VERSION 5.8 ;
BUSBITCHARS "[]" ;
DIVIDERCHAR "/" ;
UNITS
    DATABASE MICRONS 1000 ;
END UNITS

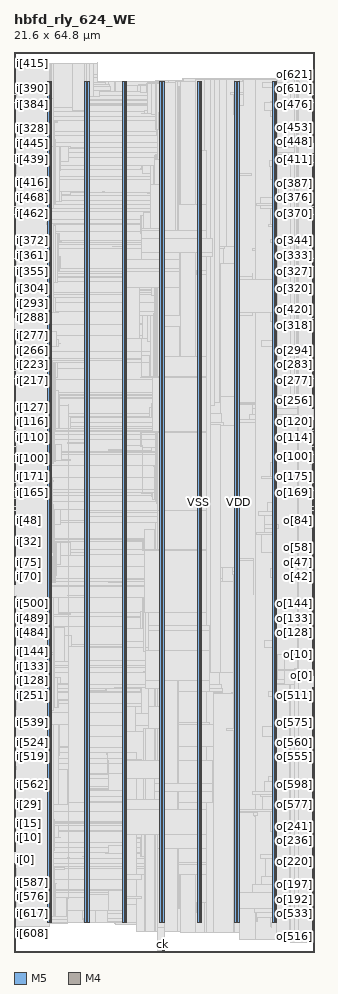
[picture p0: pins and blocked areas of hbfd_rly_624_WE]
MACRO hbfd_rly_624_WE
  FOREIGN hbfd_rly_624_WE 0 0 ;
  CLASS BLOCK ;
  SIZE 21.6 BY 64.8 ;
  PIN ck
    DIRECTION INPUT ;
    USE SIGNAL ;
    PORT
      LAYER M5 ;
        RECT  10.704 0 10.728 0.084 ;
    END
  END ck
  PIN i[0]
    DIRECTION INPUT ;
    USE SIGNAL ;
    PORT
      LAYER M4 ;
        RECT  0 7.248 0.084 7.272 ;
    END
  END i[0]
  PIN i[100]
    DIRECTION INPUT ;
    USE SIGNAL ;
    PORT
      LAYER M4 ;
        RECT  0 36.048 0.084 36.072 ;
    END
  END i[100]
  PIN i[101]
    DIRECTION INPUT ;
    USE SIGNAL ;
    PORT
      LAYER M4 ;
        RECT  0 36.144 0.084 36.168 ;
    END
  END i[101]
  PIN i[102]
    DIRECTION INPUT ;
    USE SIGNAL ;
    PORT
      LAYER M4 ;
        RECT  0 36.24 0.084 36.264 ;
    END
  END i[102]
  PIN i[103]
    DIRECTION INPUT ;
    USE SIGNAL ;
    PORT
      LAYER M4 ;
        RECT  0 36.336 0.084 36.36 ;
    END
  END i[103]
  PIN i[104]
    DIRECTION INPUT ;
    USE SIGNAL ;
    PORT
      LAYER M4 ;
        RECT  0 36.432 0.084 36.456 ;
    END
  END i[104]
  PIN i[105]
    DIRECTION INPUT ;
    USE SIGNAL ;
    PORT
      LAYER M4 ;
        RECT  0 36.528 0.084 36.552 ;
    END
  END i[105]
  PIN i[106]
    DIRECTION INPUT ;
    USE SIGNAL ;
    PORT
      LAYER M4 ;
        RECT  0 36.624 0.084 36.648 ;
    END
  END i[106]
  PIN i[107]
    DIRECTION INPUT ;
    USE SIGNAL ;
    PORT
      LAYER M4 ;
        RECT  0 36.72 0.084 36.744 ;
    END
  END i[107]
  PIN i[108]
    DIRECTION INPUT ;
    USE SIGNAL ;
    PORT
      LAYER M4 ;
        RECT  0 36.816 0.084 36.84 ;
    END
  END i[108]
  PIN i[109]
    DIRECTION INPUT ;
    USE SIGNAL ;
    PORT
      LAYER M4 ;
        RECT  0 36.912 0.084 36.936 ;
    END
  END i[109]
  PIN i[10]
    DIRECTION INPUT ;
    USE SIGNAL ;
    PORT
      LAYER M4 ;
        RECT  0 8.208 0.084 8.232 ;
    END
  END i[10]
  PIN i[110]
    DIRECTION INPUT ;
    USE SIGNAL ;
    PORT
      LAYER M4 ;
        RECT  0 37.008 0.084 37.032 ;
    END
  END i[110]
  PIN i[111]
    DIRECTION INPUT ;
    USE SIGNAL ;
    PORT
      LAYER M4 ;
        RECT  0 37.104 0.084 37.128 ;
    END
  END i[111]
  PIN i[112]
    DIRECTION INPUT ;
    USE SIGNAL ;
    PORT
      LAYER M4 ;
        RECT  0 37.2 0.084 37.224 ;
    END
  END i[112]
  PIN i[113]
    DIRECTION INPUT ;
    USE SIGNAL ;
    PORT
      LAYER M4 ;
        RECT  0 37.296 0.084 37.32 ;
    END
  END i[113]
  PIN i[114]
    DIRECTION INPUT ;
    USE SIGNAL ;
    PORT
      LAYER M4 ;
        RECT  0 37.392 0.084 37.416 ;
    END
  END i[114]
  PIN i[115]
    DIRECTION INPUT ;
    USE SIGNAL ;
    PORT
      LAYER M4 ;
        RECT  0 37.488 0.084 37.512 ;
    END
  END i[115]
  PIN i[116]
    DIRECTION INPUT ;
    USE SIGNAL ;
    PORT
      LAYER M4 ;
        RECT  0 37.584 0.084 37.608 ;
    END
  END i[116]
  PIN i[117]
    DIRECTION INPUT ;
    USE SIGNAL ;
    PORT
      LAYER M4 ;
        RECT  0 37.68 0.084 37.704 ;
    END
  END i[117]
  PIN i[118]
    DIRECTION INPUT ;
    USE SIGNAL ;
    PORT
      LAYER M4 ;
        RECT  0 37.776 0.084 37.8 ;
    END
  END i[118]
  PIN i[119]
    DIRECTION INPUT ;
    USE SIGNAL ;
    PORT
      LAYER M4 ;
        RECT  0 37.872 0.084 37.896 ;
    END
  END i[119]
  PIN i[11]
    DIRECTION INPUT ;
    USE SIGNAL ;
    PORT
      LAYER M4 ;
        RECT  0 8.304 0.084 8.328 ;
    END
  END i[11]
  PIN i[120]
    DIRECTION INPUT ;
    USE SIGNAL ;
    PORT
      LAYER M4 ;
        RECT  0 37.968 0.084 37.992 ;
    END
  END i[120]
  PIN i[121]
    DIRECTION INPUT ;
    USE SIGNAL ;
    PORT
      LAYER M4 ;
        RECT  0 38.064 0.084 38.088 ;
    END
  END i[121]
  PIN i[122]
    DIRECTION INPUT ;
    USE SIGNAL ;
    PORT
      LAYER M4 ;
        RECT  0 38.16 0.084 38.184 ;
    END
  END i[122]
  PIN i[123]
    DIRECTION INPUT ;
    USE SIGNAL ;
    PORT
      LAYER M4 ;
        RECT  0 38.256 0.084 38.28 ;
    END
  END i[123]
  PIN i[124]
    DIRECTION INPUT ;
    USE SIGNAL ;
    PORT
      LAYER M4 ;
        RECT  0 38.352 0.084 38.376 ;
    END
  END i[124]
  PIN i[125]
    DIRECTION INPUT ;
    USE SIGNAL ;
    PORT
      LAYER M4 ;
        RECT  0 38.448 0.084 38.472 ;
    END
  END i[125]
  PIN i[126]
    DIRECTION INPUT ;
    USE SIGNAL ;
    PORT
      LAYER M4 ;
        RECT  0 38.544 0.084 38.568 ;
    END
  END i[126]
  PIN i[127]
    DIRECTION INPUT ;
    USE SIGNAL ;
    PORT
      LAYER M4 ;
        RECT  0 38.64 0.084 38.664 ;
    END
  END i[127]
  PIN i[128]
    DIRECTION INPUT ;
    USE SIGNAL ;
    PORT
      LAYER M4 ;
        RECT  0 19.536 0.084 19.56 ;
    END
  END i[128]
  PIN i[129]
    DIRECTION INPUT ;
    USE SIGNAL ;
    PORT
      LAYER M4 ;
        RECT  0 19.632 0.084 19.656 ;
    END
  END i[129]
  PIN i[12]
    DIRECTION INPUT ;
    USE SIGNAL ;
    PORT
      LAYER M4 ;
        RECT  0 8.4 0.084 8.424 ;
    END
  END i[12]
  PIN i[130]
    DIRECTION INPUT ;
    USE SIGNAL ;
    PORT
      LAYER M4 ;
        RECT  0 19.728 0.084 19.752 ;
    END
  END i[130]
  PIN i[131]
    DIRECTION INPUT ;
    USE SIGNAL ;
    PORT
      LAYER M4 ;
        RECT  0 19.824 0.084 19.848 ;
    END
  END i[131]
  PIN i[132]
    DIRECTION INPUT ;
    USE SIGNAL ;
    PORT
      LAYER M4 ;
        RECT  0 19.92 0.084 19.944 ;
    END
  END i[132]
  PIN i[133]
    DIRECTION INPUT ;
    USE SIGNAL ;
    PORT
      LAYER M4 ;
        RECT  0 20.016 0.084 20.04 ;
    END
  END i[133]
  PIN i[134]
    DIRECTION INPUT ;
    USE SIGNAL ;
    PORT
      LAYER M4 ;
        RECT  0 20.112 0.084 20.136 ;
    END
  END i[134]
  PIN i[135]
    DIRECTION INPUT ;
    USE SIGNAL ;
    PORT
      LAYER M4 ;
        RECT  0 20.208 0.084 20.232 ;
    END
  END i[135]
  PIN i[136]
    DIRECTION INPUT ;
    USE SIGNAL ;
    PORT
      LAYER M4 ;
        RECT  0 20.304 0.084 20.328 ;
    END
  END i[136]
  PIN i[137]
    DIRECTION INPUT ;
    USE SIGNAL ;
    PORT
      LAYER M4 ;
        RECT  0 20.4 0.084 20.424 ;
    END
  END i[137]
  PIN i[138]
    DIRECTION INPUT ;
    USE SIGNAL ;
    PORT
      LAYER M4 ;
        RECT  0 20.496 0.084 20.52 ;
    END
  END i[138]
  PIN i[139]
    DIRECTION INPUT ;
    USE SIGNAL ;
    PORT
      LAYER M4 ;
        RECT  0 20.592 0.084 20.616 ;
    END
  END i[139]
  PIN i[13]
    DIRECTION INPUT ;
    USE SIGNAL ;
    PORT
      LAYER M4 ;
        RECT  0 8.496 0.084 8.52 ;
    END
  END i[13]
  PIN i[140]
    DIRECTION INPUT ;
    USE SIGNAL ;
    PORT
      LAYER M4 ;
        RECT  0 20.688 0.084 20.712 ;
    END
  END i[140]
  PIN i[141]
    DIRECTION INPUT ;
    USE SIGNAL ;
    PORT
      LAYER M4 ;
        RECT  0 20.784 0.084 20.808 ;
    END
  END i[141]
  PIN i[142]
    DIRECTION INPUT ;
    USE SIGNAL ;
    PORT
      LAYER M4 ;
        RECT  0 20.88 0.084 20.904 ;
    END
  END i[142]
  PIN i[143]
    DIRECTION INPUT ;
    USE SIGNAL ;
    PORT
      LAYER M4 ;
        RECT  0 20.976 0.084 21 ;
    END
  END i[143]
  PIN i[144]
    DIRECTION INPUT ;
    USE SIGNAL ;
    PORT
      LAYER M4 ;
        RECT  0 21.072 0.084 21.096 ;
    END
  END i[144]
  PIN i[145]
    DIRECTION INPUT ;
    USE SIGNAL ;
    PORT
      LAYER M4 ;
        RECT  0 21.168 0.084 21.192 ;
    END
  END i[145]
  PIN i[146]
    DIRECTION INPUT ;
    USE SIGNAL ;
    PORT
      LAYER M4 ;
        RECT  0 21.264 0.084 21.288 ;
    END
  END i[146]
  PIN i[147]
    DIRECTION INPUT ;
    USE SIGNAL ;
    PORT
      LAYER M4 ;
        RECT  0 21.36 0.084 21.384 ;
    END
  END i[147]
  PIN i[148]
    DIRECTION INPUT ;
    USE SIGNAL ;
    PORT
      LAYER M4 ;
        RECT  0 21.456 0.084 21.48 ;
    END
  END i[148]
  PIN i[149]
    DIRECTION INPUT ;
    USE SIGNAL ;
    PORT
      LAYER M4 ;
        RECT  0 21.552 0.084 21.576 ;
    END
  END i[149]
  PIN i[14]
    DIRECTION INPUT ;
    USE SIGNAL ;
    PORT
      LAYER M4 ;
        RECT  0 8.592 0.084 8.616 ;
    END
  END i[14]
  PIN i[150]
    DIRECTION INPUT ;
    USE SIGNAL ;
    PORT
      LAYER M4 ;
        RECT  0 21.648 0.084 21.672 ;
    END
  END i[150]
  PIN i[151]
    DIRECTION INPUT ;
    USE SIGNAL ;
    PORT
      LAYER M4 ;
        RECT  0 21.744 0.084 21.768 ;
    END
  END i[151]
  PIN i[152]
    DIRECTION INPUT ;
    USE SIGNAL ;
    PORT
      LAYER M4 ;
        RECT  0 21.84 0.084 21.864 ;
    END
  END i[152]
  PIN i[153]
    DIRECTION INPUT ;
    USE SIGNAL ;
    PORT
      LAYER M4 ;
        RECT  0 21.936 0.084 21.96 ;
    END
  END i[153]
  PIN i[154]
    DIRECTION INPUT ;
    USE SIGNAL ;
    PORT
      LAYER M4 ;
        RECT  0 22.032 0.084 22.056 ;
    END
  END i[154]
  PIN i[155]
    DIRECTION INPUT ;
    USE SIGNAL ;
    PORT
      LAYER M4 ;
        RECT  0 22.128 0.084 22.152 ;
    END
  END i[155]
  PIN i[156]
    DIRECTION INPUT ;
    USE SIGNAL ;
    PORT
      LAYER M4 ;
        RECT  0 22.224 0.084 22.248 ;
    END
  END i[156]
  PIN i[157]
    DIRECTION INPUT ;
    USE SIGNAL ;
    PORT
      LAYER M4 ;
        RECT  0 22.32 0.084 22.344 ;
    END
  END i[157]
  PIN i[158]
    DIRECTION INPUT ;
    USE SIGNAL ;
    PORT
      LAYER M4 ;
        RECT  0 22.416 0.084 22.44 ;
    END
  END i[158]
  PIN i[159]
    DIRECTION INPUT ;
    USE SIGNAL ;
    PORT
      LAYER M4 ;
        RECT  0 22.512 0.084 22.536 ;
    END
  END i[159]
  PIN i[15]
    DIRECTION INPUT ;
    USE SIGNAL ;
    PORT
      LAYER M4 ;
        RECT  0 8.688 0.084 8.712 ;
    END
  END i[15]
  PIN i[160]
    DIRECTION INPUT ;
    USE SIGNAL ;
    PORT
      LAYER M4 ;
        RECT  0 32.592 0.084 32.616 ;
    END
  END i[160]
  PIN i[161]
    DIRECTION INPUT ;
    USE SIGNAL ;
    PORT
      LAYER M4 ;
        RECT  0 32.688 0.084 32.712 ;
    END
  END i[161]
  PIN i[162]
    DIRECTION INPUT ;
    USE SIGNAL ;
    PORT
      LAYER M4 ;
        RECT  0 32.784 0.084 32.808 ;
    END
  END i[162]
  PIN i[163]
    DIRECTION INPUT ;
    USE SIGNAL ;
    PORT
      LAYER M4 ;
        RECT  0 32.88 0.084 32.904 ;
    END
  END i[163]
  PIN i[164]
    DIRECTION INPUT ;
    USE SIGNAL ;
    PORT
      LAYER M4 ;
        RECT  0 32.976 0.084 33 ;
    END
  END i[164]
  PIN i[165]
    DIRECTION INPUT ;
    USE SIGNAL ;
    PORT
      LAYER M4 ;
        RECT  0 33.072 0.084 33.096 ;
    END
  END i[165]
  PIN i[166]
    DIRECTION INPUT ;
    USE SIGNAL ;
    PORT
      LAYER M4 ;
        RECT  0 33.168 0.084 33.192 ;
    END
  END i[166]
  PIN i[167]
    DIRECTION INPUT ;
    USE SIGNAL ;
    PORT
      LAYER M4 ;
        RECT  0 33.264 0.084 33.288 ;
    END
  END i[167]
  PIN i[168]
    DIRECTION INPUT ;
    USE SIGNAL ;
    PORT
      LAYER M4 ;
        RECT  0 33.36 0.084 33.384 ;
    END
  END i[168]
  PIN i[169]
    DIRECTION INPUT ;
    USE SIGNAL ;
    PORT
      LAYER M4 ;
        RECT  0 33.456 0.084 33.48 ;
    END
  END i[169]
  PIN i[16]
    DIRECTION INPUT ;
    USE SIGNAL ;
    PORT
      LAYER M4 ;
        RECT  0 8.784 0.084 8.808 ;
    END
  END i[16]
  PIN i[170]
    DIRECTION INPUT ;
    USE SIGNAL ;
    PORT
      LAYER M4 ;
        RECT  0 33.552 0.084 33.576 ;
    END
  END i[170]
  PIN i[171]
    DIRECTION INPUT ;
    USE SIGNAL ;
    PORT
      LAYER M4 ;
        RECT  0 33.648 0.084 33.672 ;
    END
  END i[171]
  PIN i[172]
    DIRECTION INPUT ;
    USE SIGNAL ;
    PORT
      LAYER M4 ;
        RECT  0 33.744 0.084 33.768 ;
    END
  END i[172]
  PIN i[173]
    DIRECTION INPUT ;
    USE SIGNAL ;
    PORT
      LAYER M4 ;
        RECT  0 33.84 0.084 33.864 ;
    END
  END i[173]
  PIN i[174]
    DIRECTION INPUT ;
    USE SIGNAL ;
    PORT
      LAYER M4 ;
        RECT  0 33.936 0.084 33.96 ;
    END
  END i[174]
  PIN i[175]
    DIRECTION INPUT ;
    USE SIGNAL ;
    PORT
      LAYER M4 ;
        RECT  0 34.032 0.084 34.056 ;
    END
  END i[175]
  PIN i[176]
    DIRECTION INPUT ;
    USE SIGNAL ;
    PORT
      LAYER M4 ;
        RECT  0 34.128 0.084 34.152 ;
    END
  END i[176]
  PIN i[177]
    DIRECTION INPUT ;
    USE SIGNAL ;
    PORT
      LAYER M4 ;
        RECT  0 34.224 0.084 34.248 ;
    END
  END i[177]
  PIN i[178]
    DIRECTION INPUT ;
    USE SIGNAL ;
    PORT
      LAYER M4 ;
        RECT  0 34.32 0.084 34.344 ;
    END
  END i[178]
  PIN i[179]
    DIRECTION INPUT ;
    USE SIGNAL ;
    PORT
      LAYER M4 ;
        RECT  0 34.416 0.084 34.44 ;
    END
  END i[179]
  PIN i[17]
    DIRECTION INPUT ;
    USE SIGNAL ;
    PORT
      LAYER M4 ;
        RECT  0 8.88 0.084 8.904 ;
    END
  END i[17]
  PIN i[180]
    DIRECTION INPUT ;
    USE SIGNAL ;
    PORT
      LAYER M4 ;
        RECT  0 34.512 0.084 34.536 ;
    END
  END i[180]
  PIN i[181]
    DIRECTION INPUT ;
    USE SIGNAL ;
    PORT
      LAYER M4 ;
        RECT  0 34.608 0.084 34.632 ;
    END
  END i[181]
  PIN i[182]
    DIRECTION INPUT ;
    USE SIGNAL ;
    PORT
      LAYER M4 ;
        RECT  0 34.704 0.084 34.728 ;
    END
  END i[182]
  PIN i[183]
    DIRECTION INPUT ;
    USE SIGNAL ;
    PORT
      LAYER M4 ;
        RECT  0 34.8 0.084 34.824 ;
    END
  END i[183]
  PIN i[184]
    DIRECTION INPUT ;
    USE SIGNAL ;
    PORT
      LAYER M4 ;
        RECT  0 34.896 0.084 34.92 ;
    END
  END i[184]
  PIN i[185]
    DIRECTION INPUT ;
    USE SIGNAL ;
    PORT
      LAYER M4 ;
        RECT  0 34.992 0.084 35.016 ;
    END
  END i[185]
  PIN i[186]
    DIRECTION INPUT ;
    USE SIGNAL ;
    PORT
      LAYER M4 ;
        RECT  0 35.088 0.084 35.112 ;
    END
  END i[186]
  PIN i[187]
    DIRECTION INPUT ;
    USE SIGNAL ;
    PORT
      LAYER M4 ;
        RECT  0 35.184 0.084 35.208 ;
    END
  END i[187]
  PIN i[188]
    DIRECTION INPUT ;
    USE SIGNAL ;
    PORT
      LAYER M4 ;
        RECT  0 35.28 0.084 35.304 ;
    END
  END i[188]
  PIN i[189]
    DIRECTION INPUT ;
    USE SIGNAL ;
    PORT
      LAYER M4 ;
        RECT  0 35.376 0.084 35.4 ;
    END
  END i[189]
  PIN i[18]
    DIRECTION INPUT ;
    USE SIGNAL ;
    PORT
      LAYER M4 ;
        RECT  0 8.976 0.084 9 ;
    END
  END i[18]
  PIN i[190]
    DIRECTION INPUT ;
    USE SIGNAL ;
    PORT
      LAYER M4 ;
        RECT  0 35.472 0.084 35.496 ;
    END
  END i[190]
  PIN i[191]
    DIRECTION INPUT ;
    USE SIGNAL ;
    PORT
      LAYER M4 ;
        RECT  0 35.568 0.084 35.592 ;
    END
  END i[191]
  PIN i[192]
    DIRECTION INPUT ;
    USE SIGNAL ;
    PORT
      LAYER M4 ;
        RECT  0 38.736 0.084 38.76 ;
    END
  END i[192]
  PIN i[193]
    DIRECTION INPUT ;
    USE SIGNAL ;
    PORT
      LAYER M4 ;
        RECT  0 38.832 0.084 38.856 ;
    END
  END i[193]
  PIN i[194]
    DIRECTION INPUT ;
    USE SIGNAL ;
    PORT
      LAYER M4 ;
        RECT  0 38.928 0.084 38.952 ;
    END
  END i[194]
  PIN i[195]
    DIRECTION INPUT ;
    USE SIGNAL ;
    PORT
      LAYER M4 ;
        RECT  0 39.024 0.084 39.048 ;
    END
  END i[195]
  PIN i[196]
    DIRECTION INPUT ;
    USE SIGNAL ;
    PORT
      LAYER M4 ;
        RECT  0 39.12 0.084 39.144 ;
    END
  END i[196]
  PIN i[197]
    DIRECTION INPUT ;
    USE SIGNAL ;
    PORT
      LAYER M4 ;
        RECT  0 39.216 0.084 39.24 ;
    END
  END i[197]
  PIN i[198]
    DIRECTION INPUT ;
    USE SIGNAL ;
    PORT
      LAYER M4 ;
        RECT  0 39.312 0.084 39.336 ;
    END
  END i[198]
  PIN i[199]
    DIRECTION INPUT ;
    USE SIGNAL ;
    PORT
      LAYER M4 ;
        RECT  0 39.408 0.084 39.432 ;
    END
  END i[199]
  PIN i[19]
    DIRECTION INPUT ;
    USE SIGNAL ;
    PORT
      LAYER M4 ;
        RECT  0 9.072 0.084 9.096 ;
    END
  END i[19]
  PIN i[1]
    DIRECTION INPUT ;
    USE SIGNAL ;
    PORT
      LAYER M4 ;
        RECT  0 7.344 0.084 7.368 ;
    END
  END i[1]
  PIN i[200]
    DIRECTION INPUT ;
    USE SIGNAL ;
    PORT
      LAYER M4 ;
        RECT  0 39.504 0.084 39.528 ;
    END
  END i[200]
  PIN i[201]
    DIRECTION INPUT ;
    USE SIGNAL ;
    PORT
      LAYER M4 ;
        RECT  0 39.6 0.084 39.624 ;
    END
  END i[201]
  PIN i[202]
    DIRECTION INPUT ;
    USE SIGNAL ;
    PORT
      LAYER M4 ;
        RECT  0 39.696 0.084 39.72 ;
    END
  END i[202]
  PIN i[203]
    DIRECTION INPUT ;
    USE SIGNAL ;
    PORT
      LAYER M4 ;
        RECT  0 39.792 0.084 39.816 ;
    END
  END i[203]
  PIN i[204]
    DIRECTION INPUT ;
    USE SIGNAL ;
    PORT
      LAYER M4 ;
        RECT  0 39.888 0.084 39.912 ;
    END
  END i[204]
  PIN i[205]
    DIRECTION INPUT ;
    USE SIGNAL ;
    PORT
      LAYER M4 ;
        RECT  0 39.984 0.084 40.008 ;
    END
  END i[205]
  PIN i[206]
    DIRECTION INPUT ;
    USE SIGNAL ;
    PORT
      LAYER M4 ;
        RECT  0 40.08 0.084 40.104 ;
    END
  END i[206]
  PIN i[207]
    DIRECTION INPUT ;
    USE SIGNAL ;
    PORT
      LAYER M4 ;
        RECT  0 40.176 0.084 40.2 ;
    END
  END i[207]
  PIN i[208]
    DIRECTION INPUT ;
    USE SIGNAL ;
    PORT
      LAYER M4 ;
        RECT  0 40.272 0.084 40.296 ;
    END
  END i[208]
  PIN i[209]
    DIRECTION INPUT ;
    USE SIGNAL ;
    PORT
      LAYER M4 ;
        RECT  0 40.368 0.084 40.392 ;
    END
  END i[209]
  PIN i[20]
    DIRECTION INPUT ;
    USE SIGNAL ;
    PORT
      LAYER M4 ;
        RECT  0 9.168 0.084 9.192 ;
    END
  END i[20]
  PIN i[210]
    DIRECTION INPUT ;
    USE SIGNAL ;
    PORT
      LAYER M4 ;
        RECT  0 40.464 0.084 40.488 ;
    END
  END i[210]
  PIN i[211]
    DIRECTION INPUT ;
    USE SIGNAL ;
    PORT
      LAYER M4 ;
        RECT  0 40.56 0.084 40.584 ;
    END
  END i[211]
  PIN i[212]
    DIRECTION INPUT ;
    USE SIGNAL ;
    PORT
      LAYER M4 ;
        RECT  0 40.656 0.084 40.68 ;
    END
  END i[212]
  PIN i[213]
    DIRECTION INPUT ;
    USE SIGNAL ;
    PORT
      LAYER M4 ;
        RECT  0 40.752 0.084 40.776 ;
    END
  END i[213]
  PIN i[214]
    DIRECTION INPUT ;
    USE SIGNAL ;
    PORT
      LAYER M4 ;
        RECT  0 40.848 0.084 40.872 ;
    END
  END i[214]
  PIN i[215]
    DIRECTION INPUT ;
    USE SIGNAL ;
    PORT
      LAYER M4 ;
        RECT  0 40.944 0.084 40.968 ;
    END
  END i[215]
  PIN i[216]
    DIRECTION INPUT ;
    USE SIGNAL ;
    PORT
      LAYER M4 ;
        RECT  0 41.04 0.084 41.064 ;
    END
  END i[216]
  PIN i[217]
    DIRECTION INPUT ;
    USE SIGNAL ;
    PORT
      LAYER M4 ;
        RECT  0 41.136 0.084 41.16 ;
    END
  END i[217]
  PIN i[218]
    DIRECTION INPUT ;
    USE SIGNAL ;
    PORT
      LAYER M4 ;
        RECT  0 41.232 0.084 41.256 ;
    END
  END i[218]
  PIN i[219]
    DIRECTION INPUT ;
    USE SIGNAL ;
    PORT
      LAYER M4 ;
        RECT  0 41.328 0.084 41.352 ;
    END
  END i[219]
  PIN i[21]
    DIRECTION INPUT ;
    USE SIGNAL ;
    PORT
      LAYER M4 ;
        RECT  0 9.264 0.084 9.288 ;
    END
  END i[21]
  PIN i[220]
    DIRECTION INPUT ;
    USE SIGNAL ;
    PORT
      LAYER M4 ;
        RECT  0 41.424 0.084 41.448 ;
    END
  END i[220]
  PIN i[221]
    DIRECTION INPUT ;
    USE SIGNAL ;
    PORT
      LAYER M4 ;
        RECT  0 41.52 0.084 41.544 ;
    END
  END i[221]
  PIN i[222]
    DIRECTION INPUT ;
    USE SIGNAL ;
    PORT
      LAYER M4 ;
        RECT  0 41.616 0.084 41.64 ;
    END
  END i[222]
  PIN i[223]
    DIRECTION INPUT ;
    USE SIGNAL ;
    PORT
      LAYER M4 ;
        RECT  0 41.712 0.084 41.736 ;
    END
  END i[223]
  PIN i[224]
    DIRECTION INPUT ;
    USE SIGNAL ;
    PORT
      LAYER M4 ;
        RECT  0 16.464 0.084 16.488 ;
    END
  END i[224]
  PIN i[225]
    DIRECTION INPUT ;
    USE SIGNAL ;
    PORT
      LAYER M4 ;
        RECT  0 16.56 0.084 16.584 ;
    END
  END i[225]
  PIN i[226]
    DIRECTION INPUT ;
    USE SIGNAL ;
    PORT
      LAYER M4 ;
        RECT  0 16.656 0.084 16.68 ;
    END
  END i[226]
  PIN i[227]
    DIRECTION INPUT ;
    USE SIGNAL ;
    PORT
      LAYER M4 ;
        RECT  0 16.752 0.084 16.776 ;
    END
  END i[227]
  PIN i[228]
    DIRECTION INPUT ;
    USE SIGNAL ;
    PORT
      LAYER M4 ;
        RECT  0 16.848 0.084 16.872 ;
    END
  END i[228]
  PIN i[229]
    DIRECTION INPUT ;
    USE SIGNAL ;
    PORT
      LAYER M4 ;
        RECT  0 16.944 0.084 16.968 ;
    END
  END i[229]
  PIN i[22]
    DIRECTION INPUT ;
    USE SIGNAL ;
    PORT
      LAYER M4 ;
        RECT  0 9.36 0.084 9.384 ;
    END
  END i[22]
  PIN i[230]
    DIRECTION INPUT ;
    USE SIGNAL ;
    PORT
      LAYER M4 ;
        RECT  0 17.04 0.084 17.064 ;
    END
  END i[230]
  PIN i[231]
    DIRECTION INPUT ;
    USE SIGNAL ;
    PORT
      LAYER M4 ;
        RECT  0 17.136 0.084 17.16 ;
    END
  END i[231]
  PIN i[232]
    DIRECTION INPUT ;
    USE SIGNAL ;
    PORT
      LAYER M4 ;
        RECT  0 17.232 0.084 17.256 ;
    END
  END i[232]
  PIN i[233]
    DIRECTION INPUT ;
    USE SIGNAL ;
    PORT
      LAYER M4 ;
        RECT  0 17.328 0.084 17.352 ;
    END
  END i[233]
  PIN i[234]
    DIRECTION INPUT ;
    USE SIGNAL ;
    PORT
      LAYER M4 ;
        RECT  0 17.424 0.084 17.448 ;
    END
  END i[234]
  PIN i[235]
    DIRECTION INPUT ;
    USE SIGNAL ;
    PORT
      LAYER M4 ;
        RECT  0 17.52 0.084 17.544 ;
    END
  END i[235]
  PIN i[236]
    DIRECTION INPUT ;
    USE SIGNAL ;
    PORT
      LAYER M4 ;
        RECT  0 17.616 0.084 17.64 ;
    END
  END i[236]
  PIN i[237]
    DIRECTION INPUT ;
    USE SIGNAL ;
    PORT
      LAYER M4 ;
        RECT  0 17.712 0.084 17.736 ;
    END
  END i[237]
  PIN i[238]
    DIRECTION INPUT ;
    USE SIGNAL ;
    PORT
      LAYER M4 ;
        RECT  0 17.808 0.084 17.832 ;
    END
  END i[238]
  PIN i[239]
    DIRECTION INPUT ;
    USE SIGNAL ;
    PORT
      LAYER M4 ;
        RECT  0 17.904 0.084 17.928 ;
    END
  END i[239]
  PIN i[23]
    DIRECTION INPUT ;
    USE SIGNAL ;
    PORT
      LAYER M4 ;
        RECT  0 9.456 0.084 9.48 ;
    END
  END i[23]
  PIN i[240]
    DIRECTION INPUT ;
    USE SIGNAL ;
    PORT
      LAYER M4 ;
        RECT  0 18 0.084 18.024 ;
    END
  END i[240]
  PIN i[241]
    DIRECTION INPUT ;
    USE SIGNAL ;
    PORT
      LAYER M4 ;
        RECT  0 18.096 0.084 18.12 ;
    END
  END i[241]
  PIN i[242]
    DIRECTION INPUT ;
    USE SIGNAL ;
    PORT
      LAYER M4 ;
        RECT  0 18.192 0.084 18.216 ;
    END
  END i[242]
  PIN i[243]
    DIRECTION INPUT ;
    USE SIGNAL ;
    PORT
      LAYER M4 ;
        RECT  0 18.288 0.084 18.312 ;
    END
  END i[243]
  PIN i[244]
    DIRECTION INPUT ;
    USE SIGNAL ;
    PORT
      LAYER M4 ;
        RECT  0 18.384 0.084 18.408 ;
    END
  END i[244]
  PIN i[245]
    DIRECTION INPUT ;
    USE SIGNAL ;
    PORT
      LAYER M4 ;
        RECT  0 18.48 0.084 18.504 ;
    END
  END i[245]
  PIN i[246]
    DIRECTION INPUT ;
    USE SIGNAL ;
    PORT
      LAYER M4 ;
        RECT  0 18.576 0.084 18.6 ;
    END
  END i[246]
  PIN i[247]
    DIRECTION INPUT ;
    USE SIGNAL ;
    PORT
      LAYER M4 ;
        RECT  0 18.672 0.084 18.696 ;
    END
  END i[247]
  PIN i[248]
    DIRECTION INPUT ;
    USE SIGNAL ;
    PORT
      LAYER M4 ;
        RECT  0 18.768 0.084 18.792 ;
    END
  END i[248]
  PIN i[249]
    DIRECTION INPUT ;
    USE SIGNAL ;
    PORT
      LAYER M4 ;
        RECT  0 18.864 0.084 18.888 ;
    END
  END i[249]
  PIN i[24]
    DIRECTION INPUT ;
    USE SIGNAL ;
    PORT
      LAYER M4 ;
        RECT  0 9.552 0.084 9.576 ;
    END
  END i[24]
  PIN i[250]
    DIRECTION INPUT ;
    USE SIGNAL ;
    PORT
      LAYER M4 ;
        RECT  0 18.96 0.084 18.984 ;
    END
  END i[250]
  PIN i[251]
    DIRECTION INPUT ;
    USE SIGNAL ;
    PORT
      LAYER M4 ;
        RECT  0 19.056 0.084 19.08 ;
    END
  END i[251]
  PIN i[252]
    DIRECTION INPUT ;
    USE SIGNAL ;
    PORT
      LAYER M4 ;
        RECT  0 19.152 0.084 19.176 ;
    END
  END i[252]
  PIN i[253]
    DIRECTION INPUT ;
    USE SIGNAL ;
    PORT
      LAYER M4 ;
        RECT  0 19.248 0.084 19.272 ;
    END
  END i[253]
  PIN i[254]
    DIRECTION INPUT ;
    USE SIGNAL ;
    PORT
      LAYER M4 ;
        RECT  0 19.344 0.084 19.368 ;
    END
  END i[254]
  PIN i[255]
    DIRECTION INPUT ;
    USE SIGNAL ;
    PORT
      LAYER M4 ;
        RECT  0 19.44 0.084 19.464 ;
    END
  END i[255]
  PIN i[256]
    DIRECTION INPUT ;
    USE SIGNAL ;
    PORT
      LAYER M4 ;
        RECT  0 41.808 0.084 41.832 ;
    END
  END i[256]
  PIN i[257]
    DIRECTION INPUT ;
    USE SIGNAL ;
    PORT
      LAYER M4 ;
        RECT  0 41.904 0.084 41.928 ;
    END
  END i[257]
  PIN i[258]
    DIRECTION INPUT ;
    USE SIGNAL ;
    PORT
      LAYER M4 ;
        RECT  0 42 0.084 42.024 ;
    END
  END i[258]
  PIN i[259]
    DIRECTION INPUT ;
    USE SIGNAL ;
    PORT
      LAYER M4 ;
        RECT  0 42.096 0.084 42.12 ;
    END
  END i[259]
  PIN i[25]
    DIRECTION INPUT ;
    USE SIGNAL ;
    PORT
      LAYER M4 ;
        RECT  0 9.648 0.084 9.672 ;
    END
  END i[25]
  PIN i[260]
    DIRECTION INPUT ;
    USE SIGNAL ;
    PORT
      LAYER M4 ;
        RECT  0 42.192 0.084 42.216 ;
    END
  END i[260]
  PIN i[261]
    DIRECTION INPUT ;
    USE SIGNAL ;
    PORT
      LAYER M4 ;
        RECT  0 42.288 0.084 42.312 ;
    END
  END i[261]
  PIN i[262]
    DIRECTION INPUT ;
    USE SIGNAL ;
    PORT
      LAYER M4 ;
        RECT  0 42.384 0.084 42.408 ;
    END
  END i[262]
  PIN i[263]
    DIRECTION INPUT ;
    USE SIGNAL ;
    PORT
      LAYER M4 ;
        RECT  0 42.48 0.084 42.504 ;
    END
  END i[263]
  PIN i[264]
    DIRECTION INPUT ;
    USE SIGNAL ;
    PORT
      LAYER M4 ;
        RECT  0 42.576 0.084 42.6 ;
    END
  END i[264]
  PIN i[265]
    DIRECTION INPUT ;
    USE SIGNAL ;
    PORT
      LAYER M4 ;
        RECT  0 42.672 0.084 42.696 ;
    END
  END i[265]
  PIN i[266]
    DIRECTION INPUT ;
    USE SIGNAL ;
    PORT
      LAYER M4 ;
        RECT  0 42.768 0.084 42.792 ;
    END
  END i[266]
  PIN i[267]
    DIRECTION INPUT ;
    USE SIGNAL ;
    PORT
      LAYER M4 ;
        RECT  0 42.864 0.084 42.888 ;
    END
  END i[267]
  PIN i[268]
    DIRECTION INPUT ;
    USE SIGNAL ;
    PORT
      LAYER M4 ;
        RECT  0 42.96 0.084 42.984 ;
    END
  END i[268]
  PIN i[269]
    DIRECTION INPUT ;
    USE SIGNAL ;
    PORT
      LAYER M4 ;
        RECT  0 43.056 0.084 43.08 ;
    END
  END i[269]
  PIN i[26]
    DIRECTION INPUT ;
    USE SIGNAL ;
    PORT
      LAYER M4 ;
        RECT  0 9.744 0.084 9.768 ;
    END
  END i[26]
  PIN i[270]
    DIRECTION INPUT ;
    USE SIGNAL ;
    PORT
      LAYER M4 ;
        RECT  0 43.152 0.084 43.176 ;
    END
  END i[270]
  PIN i[271]
    DIRECTION INPUT ;
    USE SIGNAL ;
    PORT
      LAYER M4 ;
        RECT  0 43.248 0.084 43.272 ;
    END
  END i[271]
  PIN i[272]
    DIRECTION INPUT ;
    USE SIGNAL ;
    PORT
      LAYER M4 ;
        RECT  0 43.344 0.084 43.368 ;
    END
  END i[272]
  PIN i[273]
    DIRECTION INPUT ;
    USE SIGNAL ;
    PORT
      LAYER M4 ;
        RECT  0 43.44 0.084 43.464 ;
    END
  END i[273]
  PIN i[274]
    DIRECTION INPUT ;
    USE SIGNAL ;
    PORT
      LAYER M4 ;
        RECT  0 43.536 0.084 43.56 ;
    END
  END i[274]
  PIN i[275]
    DIRECTION INPUT ;
    USE SIGNAL ;
    PORT
      LAYER M4 ;
        RECT  0 43.632 0.084 43.656 ;
    END
  END i[275]
  PIN i[276]
    DIRECTION INPUT ;
    USE SIGNAL ;
    PORT
      LAYER M4 ;
        RECT  0 43.728 0.084 43.752 ;
    END
  END i[276]
  PIN i[277]
    DIRECTION INPUT ;
    USE SIGNAL ;
    PORT
      LAYER M4 ;
        RECT  0 43.824 0.084 43.848 ;
    END
  END i[277]
  PIN i[278]
    DIRECTION INPUT ;
    USE SIGNAL ;
    PORT
      LAYER M4 ;
        RECT  0 43.92 0.084 43.944 ;
    END
  END i[278]
  PIN i[279]
    DIRECTION INPUT ;
    USE SIGNAL ;
    PORT
      LAYER M4 ;
        RECT  0 44.016 0.084 44.04 ;
    END
  END i[279]
  PIN i[27]
    DIRECTION INPUT ;
    USE SIGNAL ;
    PORT
      LAYER M4 ;
        RECT  0 9.84 0.084 9.864 ;
    END
  END i[27]
  PIN i[280]
    DIRECTION INPUT ;
    USE SIGNAL ;
    PORT
      LAYER M4 ;
        RECT  0 44.112 0.084 44.136 ;
    END
  END i[280]
  PIN i[281]
    DIRECTION INPUT ;
    USE SIGNAL ;
    PORT
      LAYER M4 ;
        RECT  0 44.208 0.084 44.232 ;
    END
  END i[281]
  PIN i[282]
    DIRECTION INPUT ;
    USE SIGNAL ;
    PORT
      LAYER M4 ;
        RECT  0 44.304 0.084 44.328 ;
    END
  END i[282]
  PIN i[283]
    DIRECTION INPUT ;
    USE SIGNAL ;
    PORT
      LAYER M4 ;
        RECT  0 44.4 0.084 44.424 ;
    END
  END i[283]
  PIN i[284]
    DIRECTION INPUT ;
    USE SIGNAL ;
    PORT
      LAYER M4 ;
        RECT  0 44.496 0.084 44.52 ;
    END
  END i[284]
  PIN i[285]
    DIRECTION INPUT ;
    USE SIGNAL ;
    PORT
      LAYER M4 ;
        RECT  0 44.592 0.084 44.616 ;
    END
  END i[285]
  PIN i[286]
    DIRECTION INPUT ;
    USE SIGNAL ;
    PORT
      LAYER M4 ;
        RECT  0 44.688 0.084 44.712 ;
    END
  END i[286]
  PIN i[287]
    DIRECTION INPUT ;
    USE SIGNAL ;
    PORT
      LAYER M4 ;
        RECT  0 44.784 0.084 44.808 ;
    END
  END i[287]
  PIN i[288]
    DIRECTION INPUT ;
    USE SIGNAL ;
    PORT
      LAYER M4 ;
        RECT  0 45.648 0.084 45.672 ;
    END
  END i[288]
  PIN i[289]
    DIRECTION INPUT ;
    USE SIGNAL ;
    PORT
      LAYER M4 ;
        RECT  0 45.744 0.084 45.768 ;
    END
  END i[289]
  PIN i[28]
    DIRECTION INPUT ;
    USE SIGNAL ;
    PORT
      LAYER M4 ;
        RECT  0 9.936 0.084 9.96 ;
    END
  END i[28]
  PIN i[290]
    DIRECTION INPUT ;
    USE SIGNAL ;
    PORT
      LAYER M4 ;
        RECT  0 45.84 0.084 45.864 ;
    END
  END i[290]
  PIN i[291]
    DIRECTION INPUT ;
    USE SIGNAL ;
    PORT
      LAYER M4 ;
        RECT  0 45.936 0.084 45.96 ;
    END
  END i[291]
  PIN i[292]
    DIRECTION INPUT ;
    USE SIGNAL ;
    PORT
      LAYER M4 ;
        RECT  0 46.032 0.084 46.056 ;
    END
  END i[292]
  PIN i[293]
    DIRECTION INPUT ;
    USE SIGNAL ;
    PORT
      LAYER M4 ;
        RECT  0 46.128 0.084 46.152 ;
    END
  END i[293]
  PIN i[294]
    DIRECTION INPUT ;
    USE SIGNAL ;
    PORT
      LAYER M4 ;
        RECT  0 46.224 0.084 46.248 ;
    END
  END i[294]
  PIN i[295]
    DIRECTION INPUT ;
    USE SIGNAL ;
    PORT
      LAYER M4 ;
        RECT  0 46.32 0.084 46.344 ;
    END
  END i[295]
  PIN i[296]
    DIRECTION INPUT ;
    USE SIGNAL ;
    PORT
      LAYER M4 ;
        RECT  0 46.416 0.084 46.44 ;
    END
  END i[296]
  PIN i[297]
    DIRECTION INPUT ;
    USE SIGNAL ;
    PORT
      LAYER M4 ;
        RECT  0 46.512 0.084 46.536 ;
    END
  END i[297]
  PIN i[298]
    DIRECTION INPUT ;
    USE SIGNAL ;
    PORT
      LAYER M4 ;
        RECT  0 46.608 0.084 46.632 ;
    END
  END i[298]
  PIN i[299]
    DIRECTION INPUT ;
    USE SIGNAL ;
    PORT
      LAYER M4 ;
        RECT  0 46.704 0.084 46.728 ;
    END
  END i[299]
  PIN i[29]
    DIRECTION INPUT ;
    USE SIGNAL ;
    PORT
      LAYER M4 ;
        RECT  0 10.032 0.084 10.056 ;
    END
  END i[29]
  PIN i[2]
    DIRECTION INPUT ;
    USE SIGNAL ;
    PORT
      LAYER M4 ;
        RECT  0 7.44 0.084 7.464 ;
    END
  END i[2]
  PIN i[300]
    DIRECTION INPUT ;
    USE SIGNAL ;
    PORT
      LAYER M4 ;
        RECT  0 46.8 0.084 46.824 ;
    END
  END i[300]
  PIN i[301]
    DIRECTION INPUT ;
    USE SIGNAL ;
    PORT
      LAYER M4 ;
        RECT  0 46.896 0.084 46.92 ;
    END
  END i[301]
  PIN i[302]
    DIRECTION INPUT ;
    USE SIGNAL ;
    PORT
      LAYER M4 ;
        RECT  0 46.992 0.084 47.016 ;
    END
  END i[302]
  PIN i[303]
    DIRECTION INPUT ;
    USE SIGNAL ;
    PORT
      LAYER M4 ;
        RECT  0 47.088 0.084 47.112 ;
    END
  END i[303]
  PIN i[304]
    DIRECTION INPUT ;
    USE SIGNAL ;
    PORT
      LAYER M4 ;
        RECT  0 47.184 0.084 47.208 ;
    END
  END i[304]
  PIN i[305]
    DIRECTION INPUT ;
    USE SIGNAL ;
    PORT
      LAYER M4 ;
        RECT  0 47.28 0.084 47.304 ;
    END
  END i[305]
  PIN i[306]
    DIRECTION INPUT ;
    USE SIGNAL ;
    PORT
      LAYER M4 ;
        RECT  0 47.376 0.084 47.4 ;
    END
  END i[306]
  PIN i[307]
    DIRECTION INPUT ;
    USE SIGNAL ;
    PORT
      LAYER M4 ;
        RECT  0 47.472 0.084 47.496 ;
    END
  END i[307]
  PIN i[308]
    DIRECTION INPUT ;
    USE SIGNAL ;
    PORT
      LAYER M4 ;
        RECT  0 47.568 0.084 47.592 ;
    END
  END i[308]
  PIN i[309]
    DIRECTION INPUT ;
    USE SIGNAL ;
    PORT
      LAYER M4 ;
        RECT  0 47.664 0.084 47.688 ;
    END
  END i[309]
  PIN i[30]
    DIRECTION INPUT ;
    USE SIGNAL ;
    PORT
      LAYER M4 ;
        RECT  0 10.128 0.084 10.152 ;
    END
  END i[30]
  PIN i[310]
    DIRECTION INPUT ;
    USE SIGNAL ;
    PORT
      LAYER M4 ;
        RECT  0 47.76 0.084 47.784 ;
    END
  END i[310]
  PIN i[311]
    DIRECTION INPUT ;
    USE SIGNAL ;
    PORT
      LAYER M4 ;
        RECT  0 47.856 0.084 47.88 ;
    END
  END i[311]
  PIN i[312]
    DIRECTION INPUT ;
    USE SIGNAL ;
    PORT
      LAYER M4 ;
        RECT  0 47.952 0.084 47.976 ;
    END
  END i[312]
  PIN i[313]
    DIRECTION INPUT ;
    USE SIGNAL ;
    PORT
      LAYER M4 ;
        RECT  0 48.048 0.084 48.072 ;
    END
  END i[313]
  PIN i[314]
    DIRECTION INPUT ;
    USE SIGNAL ;
    PORT
      LAYER M4 ;
        RECT  0 48.144 0.084 48.168 ;
    END
  END i[314]
  PIN i[315]
    DIRECTION INPUT ;
    USE SIGNAL ;
    PORT
      LAYER M4 ;
        RECT  0 48.24 0.084 48.264 ;
    END
  END i[315]
  PIN i[316]
    DIRECTION INPUT ;
    USE SIGNAL ;
    PORT
      LAYER M4 ;
        RECT  0 48.336 0.084 48.36 ;
    END
  END i[316]
  PIN i[317]
    DIRECTION INPUT ;
    USE SIGNAL ;
    PORT
      LAYER M4 ;
        RECT  0 48.432 0.084 48.456 ;
    END
  END i[317]
  PIN i[318]
    DIRECTION INPUT ;
    USE SIGNAL ;
    PORT
      LAYER M4 ;
        RECT  0 48.528 0.084 48.552 ;
    END
  END i[318]
  PIN i[319]
    DIRECTION INPUT ;
    USE SIGNAL ;
    PORT
      LAYER M4 ;
        RECT  0 48.624 0.084 48.648 ;
    END
  END i[319]
  PIN i[31]
    DIRECTION INPUT ;
    USE SIGNAL ;
    PORT
      LAYER M4 ;
        RECT  0 10.224 0.084 10.248 ;
    END
  END i[31]
  PIN i[320]
    DIRECTION INPUT ;
    USE SIGNAL ;
    PORT
      LAYER M4 ;
        RECT  0 57.936 0.084 57.96 ;
    END
  END i[320]
  PIN i[321]
    DIRECTION INPUT ;
    USE SIGNAL ;
    PORT
      LAYER M4 ;
        RECT  0 58.032 0.084 58.056 ;
    END
  END i[321]
  PIN i[322]
    DIRECTION INPUT ;
    USE SIGNAL ;
    PORT
      LAYER M4 ;
        RECT  0 58.128 0.084 58.152 ;
    END
  END i[322]
  PIN i[323]
    DIRECTION INPUT ;
    USE SIGNAL ;
    PORT
      LAYER M4 ;
        RECT  0 58.224 0.084 58.248 ;
    END
  END i[323]
  PIN i[324]
    DIRECTION INPUT ;
    USE SIGNAL ;
    PORT
      LAYER M4 ;
        RECT  0 58.32 0.084 58.344 ;
    END
  END i[324]
  PIN i[325]
    DIRECTION INPUT ;
    USE SIGNAL ;
    PORT
      LAYER M4 ;
        RECT  0 58.416 0.084 58.44 ;
    END
  END i[325]
  PIN i[326]
    DIRECTION INPUT ;
    USE SIGNAL ;
    PORT
      LAYER M4 ;
        RECT  0 58.512 0.084 58.536 ;
    END
  END i[326]
  PIN i[327]
    DIRECTION INPUT ;
    USE SIGNAL ;
    PORT
      LAYER M4 ;
        RECT  0 58.608 0.084 58.632 ;
    END
  END i[327]
  PIN i[328]
    DIRECTION INPUT ;
    USE SIGNAL ;
    PORT
      LAYER M4 ;
        RECT  0 58.704 0.084 58.728 ;
    END
  END i[328]
  PIN i[329]
    DIRECTION INPUT ;
    USE SIGNAL ;
    PORT
      LAYER M4 ;
        RECT  0 58.8 0.084 58.824 ;
    END
  END i[329]
  PIN i[32]
    DIRECTION INPUT ;
    USE SIGNAL ;
    PORT
      LAYER M4 ;
        RECT  0 29.52 0.084 29.544 ;
    END
  END i[32]
  PIN i[330]
    DIRECTION INPUT ;
    USE SIGNAL ;
    PORT
      LAYER M4 ;
        RECT  0 58.896 0.084 58.92 ;
    END
  END i[330]
  PIN i[331]
    DIRECTION INPUT ;
    USE SIGNAL ;
    PORT
      LAYER M4 ;
        RECT  0 58.992 0.084 59.016 ;
    END
  END i[331]
  PIN i[332]
    DIRECTION INPUT ;
    USE SIGNAL ;
    PORT
      LAYER M4 ;
        RECT  0 59.088 0.084 59.112 ;
    END
  END i[332]
  PIN i[333]
    DIRECTION INPUT ;
    USE SIGNAL ;
    PORT
      LAYER M4 ;
        RECT  0 59.184 0.084 59.208 ;
    END
  END i[333]
  PIN i[334]
    DIRECTION INPUT ;
    USE SIGNAL ;
    PORT
      LAYER M4 ;
        RECT  0 59.28 0.084 59.304 ;
    END
  END i[334]
  PIN i[335]
    DIRECTION INPUT ;
    USE SIGNAL ;
    PORT
      LAYER M4 ;
        RECT  0 59.376 0.084 59.4 ;
    END
  END i[335]
  PIN i[336]
    DIRECTION INPUT ;
    USE SIGNAL ;
    PORT
      LAYER M4 ;
        RECT  0 59.472 0.084 59.496 ;
    END
  END i[336]
  PIN i[337]
    DIRECTION INPUT ;
    USE SIGNAL ;
    PORT
      LAYER M4 ;
        RECT  0 59.568 0.084 59.592 ;
    END
  END i[337]
  PIN i[338]
    DIRECTION INPUT ;
    USE SIGNAL ;
    PORT
      LAYER M4 ;
        RECT  0 59.664 0.084 59.688 ;
    END
  END i[338]
  PIN i[339]
    DIRECTION INPUT ;
    USE SIGNAL ;
    PORT
      LAYER M4 ;
        RECT  0 59.76 0.084 59.784 ;
    END
  END i[339]
  PIN i[33]
    DIRECTION INPUT ;
    USE SIGNAL ;
    PORT
      LAYER M4 ;
        RECT  0 29.616 0.084 29.64 ;
    END
  END i[33]
  PIN i[340]
    DIRECTION INPUT ;
    USE SIGNAL ;
    PORT
      LAYER M4 ;
        RECT  0 59.856 0.084 59.88 ;
    END
  END i[340]
  PIN i[341]
    DIRECTION INPUT ;
    USE SIGNAL ;
    PORT
      LAYER M4 ;
        RECT  0 59.952 0.084 59.976 ;
    END
  END i[341]
  PIN i[342]
    DIRECTION INPUT ;
    USE SIGNAL ;
    PORT
      LAYER M4 ;
        RECT  0 60.048 0.084 60.072 ;
    END
  END i[342]
  PIN i[343]
    DIRECTION INPUT ;
    USE SIGNAL ;
    PORT
      LAYER M4 ;
        RECT  0 60.144 0.084 60.168 ;
    END
  END i[343]
  PIN i[344]
    DIRECTION INPUT ;
    USE SIGNAL ;
    PORT
      LAYER M4 ;
        RECT  0 60.24 0.084 60.264 ;
    END
  END i[344]
  PIN i[345]
    DIRECTION INPUT ;
    USE SIGNAL ;
    PORT
      LAYER M4 ;
        RECT  0 60.336 0.084 60.36 ;
    END
  END i[345]
  PIN i[346]
    DIRECTION INPUT ;
    USE SIGNAL ;
    PORT
      LAYER M4 ;
        RECT  0 60.432 0.084 60.456 ;
    END
  END i[346]
  PIN i[347]
    DIRECTION INPUT ;
    USE SIGNAL ;
    PORT
      LAYER M4 ;
        RECT  0 60.528 0.084 60.552 ;
    END
  END i[347]
  PIN i[348]
    DIRECTION INPUT ;
    USE SIGNAL ;
    PORT
      LAYER M4 ;
        RECT  0 60.624 0.084 60.648 ;
    END
  END i[348]
  PIN i[349]
    DIRECTION INPUT ;
    USE SIGNAL ;
    PORT
      LAYER M4 ;
        RECT  0 60.72 0.084 60.744 ;
    END
  END i[349]
  PIN i[34]
    DIRECTION INPUT ;
    USE SIGNAL ;
    PORT
      LAYER M4 ;
        RECT  0 29.712 0.084 29.736 ;
    END
  END i[34]
  PIN i[350]
    DIRECTION INPUT ;
    USE SIGNAL ;
    PORT
      LAYER M4 ;
        RECT  0 60.816 0.084 60.84 ;
    END
  END i[350]
  PIN i[351]
    DIRECTION INPUT ;
    USE SIGNAL ;
    PORT
      LAYER M4 ;
        RECT  0 60.912 0.084 60.936 ;
    END
  END i[351]
  PIN i[352]
    DIRECTION INPUT ;
    USE SIGNAL ;
    PORT
      LAYER M4 ;
        RECT  0 48.72 0.084 48.744 ;
    END
  END i[352]
  PIN i[353]
    DIRECTION INPUT ;
    USE SIGNAL ;
    PORT
      LAYER M4 ;
        RECT  0 48.816 0.084 48.84 ;
    END
  END i[353]
  PIN i[354]
    DIRECTION INPUT ;
    USE SIGNAL ;
    PORT
      LAYER M4 ;
        RECT  0 48.912 0.084 48.936 ;
    END
  END i[354]
  PIN i[355]
    DIRECTION INPUT ;
    USE SIGNAL ;
    PORT
      LAYER M4 ;
        RECT  0 49.008 0.084 49.032 ;
    END
  END i[355]
  PIN i[356]
    DIRECTION INPUT ;
    USE SIGNAL ;
    PORT
      LAYER M4 ;
        RECT  0 49.104 0.084 49.128 ;
    END
  END i[356]
  PIN i[357]
    DIRECTION INPUT ;
    USE SIGNAL ;
    PORT
      LAYER M4 ;
        RECT  0 49.2 0.084 49.224 ;
    END
  END i[357]
  PIN i[358]
    DIRECTION INPUT ;
    USE SIGNAL ;
    PORT
      LAYER M4 ;
        RECT  0 49.296 0.084 49.32 ;
    END
  END i[358]
  PIN i[359]
    DIRECTION INPUT ;
    USE SIGNAL ;
    PORT
      LAYER M4 ;
        RECT  0 49.392 0.084 49.416 ;
    END
  END i[359]
  PIN i[35]
    DIRECTION INPUT ;
    USE SIGNAL ;
    PORT
      LAYER M4 ;
        RECT  0 29.808 0.084 29.832 ;
    END
  END i[35]
  PIN i[360]
    DIRECTION INPUT ;
    USE SIGNAL ;
    PORT
      LAYER M4 ;
        RECT  0 49.488 0.084 49.512 ;
    END
  END i[360]
  PIN i[361]
    DIRECTION INPUT ;
    USE SIGNAL ;
    PORT
      LAYER M4 ;
        RECT  0 49.584 0.084 49.608 ;
    END
  END i[361]
  PIN i[362]
    DIRECTION INPUT ;
    USE SIGNAL ;
    PORT
      LAYER M4 ;
        RECT  0 49.68 0.084 49.704 ;
    END
  END i[362]
  PIN i[363]
    DIRECTION INPUT ;
    USE SIGNAL ;
    PORT
      LAYER M4 ;
        RECT  0 49.776 0.084 49.8 ;
    END
  END i[363]
  PIN i[364]
    DIRECTION INPUT ;
    USE SIGNAL ;
    PORT
      LAYER M4 ;
        RECT  0 49.872 0.084 49.896 ;
    END
  END i[364]
  PIN i[365]
    DIRECTION INPUT ;
    USE SIGNAL ;
    PORT
      LAYER M4 ;
        RECT  0 49.968 0.084 49.992 ;
    END
  END i[365]
  PIN i[366]
    DIRECTION INPUT ;
    USE SIGNAL ;
    PORT
      LAYER M4 ;
        RECT  0 50.064 0.084 50.088 ;
    END
  END i[366]
  PIN i[367]
    DIRECTION INPUT ;
    USE SIGNAL ;
    PORT
      LAYER M4 ;
        RECT  0 50.16 0.084 50.184 ;
    END
  END i[367]
  PIN i[368]
    DIRECTION INPUT ;
    USE SIGNAL ;
    PORT
      LAYER M4 ;
        RECT  0 50.256 0.084 50.28 ;
    END
  END i[368]
  PIN i[369]
    DIRECTION INPUT ;
    USE SIGNAL ;
    PORT
      LAYER M4 ;
        RECT  0 50.352 0.084 50.376 ;
    END
  END i[369]
  PIN i[36]
    DIRECTION INPUT ;
    USE SIGNAL ;
    PORT
      LAYER M4 ;
        RECT  0 29.904 0.084 29.928 ;
    END
  END i[36]
  PIN i[370]
    DIRECTION INPUT ;
    USE SIGNAL ;
    PORT
      LAYER M4 ;
        RECT  0 50.448 0.084 50.472 ;
    END
  END i[370]
  PIN i[371]
    DIRECTION INPUT ;
    USE SIGNAL ;
    PORT
      LAYER M4 ;
        RECT  0 50.544 0.084 50.568 ;
    END
  END i[371]
  PIN i[372]
    DIRECTION INPUT ;
    USE SIGNAL ;
    PORT
      LAYER M4 ;
        RECT  0 50.64 0.084 50.664 ;
    END
  END i[372]
  PIN i[373]
    DIRECTION INPUT ;
    USE SIGNAL ;
    PORT
      LAYER M4 ;
        RECT  0 50.736 0.084 50.76 ;
    END
  END i[373]
  PIN i[374]
    DIRECTION INPUT ;
    USE SIGNAL ;
    PORT
      LAYER M4 ;
        RECT  0 50.832 0.084 50.856 ;
    END
  END i[374]
  PIN i[375]
    DIRECTION INPUT ;
    USE SIGNAL ;
    PORT
      LAYER M4 ;
        RECT  0 50.928 0.084 50.952 ;
    END
  END i[375]
  PIN i[376]
    DIRECTION INPUT ;
    USE SIGNAL ;
    PORT
      LAYER M4 ;
        RECT  0 51.024 0.084 51.048 ;
    END
  END i[376]
  PIN i[377]
    DIRECTION INPUT ;
    USE SIGNAL ;
    PORT
      LAYER M4 ;
        RECT  0 51.12 0.084 51.144 ;
    END
  END i[377]
  PIN i[378]
    DIRECTION INPUT ;
    USE SIGNAL ;
    PORT
      LAYER M4 ;
        RECT  0 51.216 0.084 51.24 ;
    END
  END i[378]
  PIN i[379]
    DIRECTION INPUT ;
    USE SIGNAL ;
    PORT
      LAYER M4 ;
        RECT  0 51.312 0.084 51.336 ;
    END
  END i[379]
  PIN i[37]
    DIRECTION INPUT ;
    USE SIGNAL ;
    PORT
      LAYER M4 ;
        RECT  0 30 0.084 30.024 ;
    END
  END i[37]
  PIN i[380]
    DIRECTION INPUT ;
    USE SIGNAL ;
    PORT
      LAYER M4 ;
        RECT  0 51.408 0.084 51.432 ;
    END
  END i[380]
  PIN i[381]
    DIRECTION INPUT ;
    USE SIGNAL ;
    PORT
      LAYER M4 ;
        RECT  0 51.504 0.084 51.528 ;
    END
  END i[381]
  PIN i[382]
    DIRECTION INPUT ;
    USE SIGNAL ;
    PORT
      LAYER M4 ;
        RECT  0 51.6 0.084 51.624 ;
    END
  END i[382]
  PIN i[383]
    DIRECTION INPUT ;
    USE SIGNAL ;
    PORT
      LAYER M4 ;
        RECT  0 51.696 0.084 51.72 ;
    END
  END i[383]
  PIN i[384]
    DIRECTION INPUT ;
    USE SIGNAL ;
    PORT
      LAYER M4 ;
        RECT  0 61.008 0.084 61.032 ;
    END
  END i[384]
  PIN i[385]
    DIRECTION INPUT ;
    USE SIGNAL ;
    PORT
      LAYER M4 ;
        RECT  0 61.104 0.084 61.128 ;
    END
  END i[385]
  PIN i[386]
    DIRECTION INPUT ;
    USE SIGNAL ;
    PORT
      LAYER M4 ;
        RECT  0 61.2 0.084 61.224 ;
    END
  END i[386]
  PIN i[387]
    DIRECTION INPUT ;
    USE SIGNAL ;
    PORT
      LAYER M4 ;
        RECT  0 61.296 0.084 61.32 ;
    END
  END i[387]
  PIN i[388]
    DIRECTION INPUT ;
    USE SIGNAL ;
    PORT
      LAYER M4 ;
        RECT  0 61.392 0.084 61.416 ;
    END
  END i[388]
  PIN i[389]
    DIRECTION INPUT ;
    USE SIGNAL ;
    PORT
      LAYER M4 ;
        RECT  0 61.488 0.084 61.512 ;
    END
  END i[389]
  PIN i[38]
    DIRECTION INPUT ;
    USE SIGNAL ;
    PORT
      LAYER M4 ;
        RECT  0 30.096 0.084 30.12 ;
    END
  END i[38]
  PIN i[390]
    DIRECTION INPUT ;
    USE SIGNAL ;
    PORT
      LAYER M4 ;
        RECT  0 61.584 0.084 61.608 ;
    END
  END i[390]
  PIN i[391]
    DIRECTION INPUT ;
    USE SIGNAL ;
    PORT
      LAYER M4 ;
        RECT  0 61.68 0.084 61.704 ;
    END
  END i[391]
  PIN i[392]
    DIRECTION INPUT ;
    USE SIGNAL ;
    PORT
      LAYER M4 ;
        RECT  0 61.776 0.084 61.8 ;
    END
  END i[392]
  PIN i[393]
    DIRECTION INPUT ;
    USE SIGNAL ;
    PORT
      LAYER M4 ;
        RECT  0 61.872 0.084 61.896 ;
    END
  END i[393]
  PIN i[394]
    DIRECTION INPUT ;
    USE SIGNAL ;
    PORT
      LAYER M4 ;
        RECT  0 61.968 0.084 61.992 ;
    END
  END i[394]
  PIN i[395]
    DIRECTION INPUT ;
    USE SIGNAL ;
    PORT
      LAYER M4 ;
        RECT  0 62.064 0.084 62.088 ;
    END
  END i[395]
  PIN i[396]
    DIRECTION INPUT ;
    USE SIGNAL ;
    PORT
      LAYER M4 ;
        RECT  0 62.16 0.084 62.184 ;
    END
  END i[396]
  PIN i[397]
    DIRECTION INPUT ;
    USE SIGNAL ;
    PORT
      LAYER M4 ;
        RECT  0 62.256 0.084 62.28 ;
    END
  END i[397]
  PIN i[398]
    DIRECTION INPUT ;
    USE SIGNAL ;
    PORT
      LAYER M4 ;
        RECT  0 62.352 0.084 62.376 ;
    END
  END i[398]
  PIN i[399]
    DIRECTION INPUT ;
    USE SIGNAL ;
    PORT
      LAYER M4 ;
        RECT  0 62.448 0.084 62.472 ;
    END
  END i[399]
  PIN i[39]
    DIRECTION INPUT ;
    USE SIGNAL ;
    PORT
      LAYER M4 ;
        RECT  0 30.192 0.084 30.216 ;
    END
  END i[39]
  PIN i[3]
    DIRECTION INPUT ;
    USE SIGNAL ;
    PORT
      LAYER M4 ;
        RECT  0 7.536 0.084 7.56 ;
    END
  END i[3]
  PIN i[400]
    DIRECTION INPUT ;
    USE SIGNAL ;
    PORT
      LAYER M4 ;
        RECT  0 62.544 0.084 62.568 ;
    END
  END i[400]
  PIN i[401]
    DIRECTION INPUT ;
    USE SIGNAL ;
    PORT
      LAYER M4 ;
        RECT  0 62.64 0.084 62.664 ;
    END
  END i[401]
  PIN i[402]
    DIRECTION INPUT ;
    USE SIGNAL ;
    PORT
      LAYER M4 ;
        RECT  0 62.736 0.084 62.76 ;
    END
  END i[402]
  PIN i[403]
    DIRECTION INPUT ;
    USE SIGNAL ;
    PORT
      LAYER M4 ;
        RECT  0 62.832 0.084 62.856 ;
    END
  END i[403]
  PIN i[404]
    DIRECTION INPUT ;
    USE SIGNAL ;
    PORT
      LAYER M4 ;
        RECT  0 62.928 0.084 62.952 ;
    END
  END i[404]
  PIN i[405]
    DIRECTION INPUT ;
    USE SIGNAL ;
    PORT
      LAYER M4 ;
        RECT  0 63.024 0.084 63.048 ;
    END
  END i[405]
  PIN i[406]
    DIRECTION INPUT ;
    USE SIGNAL ;
    PORT
      LAYER M4 ;
        RECT  0 63.12 0.084 63.144 ;
    END
  END i[406]
  PIN i[407]
    DIRECTION INPUT ;
    USE SIGNAL ;
    PORT
      LAYER M4 ;
        RECT  0 63.216 0.084 63.24 ;
    END
  END i[407]
  PIN i[408]
    DIRECTION INPUT ;
    USE SIGNAL ;
    PORT
      LAYER M4 ;
        RECT  0 63.312 0.084 63.336 ;
    END
  END i[408]
  PIN i[409]
    DIRECTION INPUT ;
    USE SIGNAL ;
    PORT
      LAYER M4 ;
        RECT  0 63.408 0.084 63.432 ;
    END
  END i[409]
  PIN i[40]
    DIRECTION INPUT ;
    USE SIGNAL ;
    PORT
      LAYER M4 ;
        RECT  0 30.288 0.084 30.312 ;
    END
  END i[40]
  PIN i[410]
    DIRECTION INPUT ;
    USE SIGNAL ;
    PORT
      LAYER M4 ;
        RECT  0 63.504 0.084 63.528 ;
    END
  END i[410]
  PIN i[411]
    DIRECTION INPUT ;
    USE SIGNAL ;
    PORT
      LAYER M4 ;
        RECT  0 63.6 0.084 63.624 ;
    END
  END i[411]
  PIN i[412]
    DIRECTION INPUT ;
    USE SIGNAL ;
    PORT
      LAYER M4 ;
        RECT  0 63.696 0.084 63.72 ;
    END
  END i[412]
  PIN i[413]
    DIRECTION INPUT ;
    USE SIGNAL ;
    PORT
      LAYER M4 ;
        RECT  0 63.792 0.084 63.816 ;
    END
  END i[413]
  PIN i[414]
    DIRECTION INPUT ;
    USE SIGNAL ;
    PORT
      LAYER M4 ;
        RECT  0 63.888 0.084 63.912 ;
    END
  END i[414]
  PIN i[415]
    DIRECTION INPUT ;
    USE SIGNAL ;
    PORT
      LAYER M4 ;
        RECT  0 63.984 0.084 64.008 ;
    END
  END i[415]
  PIN i[416]
    DIRECTION INPUT ;
    USE SIGNAL ;
    PORT
      LAYER M4 ;
        RECT  0 54.864 0.084 54.888 ;
    END
  END i[416]
  PIN i[417]
    DIRECTION INPUT ;
    USE SIGNAL ;
    PORT
      LAYER M4 ;
        RECT  0 54.96 0.084 54.984 ;
    END
  END i[417]
  PIN i[418]
    DIRECTION INPUT ;
    USE SIGNAL ;
    PORT
      LAYER M4 ;
        RECT  0 55.056 0.084 55.08 ;
    END
  END i[418]
  PIN i[419]
    DIRECTION INPUT ;
    USE SIGNAL ;
    PORT
      LAYER M4 ;
        RECT  0 55.152 0.084 55.176 ;
    END
  END i[419]
  PIN i[41]
    DIRECTION INPUT ;
    USE SIGNAL ;
    PORT
      LAYER M4 ;
        RECT  0 30.384 0.084 30.408 ;
    END
  END i[41]
  PIN i[420]
    DIRECTION INPUT ;
    USE SIGNAL ;
    PORT
      LAYER M4 ;
        RECT  0 55.248 0.084 55.272 ;
    END
  END i[420]
  PIN i[421]
    DIRECTION INPUT ;
    USE SIGNAL ;
    PORT
      LAYER M4 ;
        RECT  0 55.344 0.084 55.368 ;
    END
  END i[421]
  PIN i[422]
    DIRECTION INPUT ;
    USE SIGNAL ;
    PORT
      LAYER M4 ;
        RECT  0 55.44 0.084 55.464 ;
    END
  END i[422]
  PIN i[423]
    DIRECTION INPUT ;
    USE SIGNAL ;
    PORT
      LAYER M4 ;
        RECT  0 55.536 0.084 55.56 ;
    END
  END i[423]
  PIN i[424]
    DIRECTION INPUT ;
    USE SIGNAL ;
    PORT
      LAYER M4 ;
        RECT  0 55.632 0.084 55.656 ;
    END
  END i[424]
  PIN i[425]
    DIRECTION INPUT ;
    USE SIGNAL ;
    PORT
      LAYER M4 ;
        RECT  0 55.728 0.084 55.752 ;
    END
  END i[425]
  PIN i[426]
    DIRECTION INPUT ;
    USE SIGNAL ;
    PORT
      LAYER M4 ;
        RECT  0 55.824 0.084 55.848 ;
    END
  END i[426]
  PIN i[427]
    DIRECTION INPUT ;
    USE SIGNAL ;
    PORT
      LAYER M4 ;
        RECT  0 55.92 0.084 55.944 ;
    END
  END i[427]
  PIN i[428]
    DIRECTION INPUT ;
    USE SIGNAL ;
    PORT
      LAYER M4 ;
        RECT  0 56.016 0.084 56.04 ;
    END
  END i[428]
  PIN i[429]
    DIRECTION INPUT ;
    USE SIGNAL ;
    PORT
      LAYER M4 ;
        RECT  0 56.112 0.084 56.136 ;
    END
  END i[429]
  PIN i[42]
    DIRECTION INPUT ;
    USE SIGNAL ;
    PORT
      LAYER M4 ;
        RECT  0 30.48 0.084 30.504 ;
    END
  END i[42]
  PIN i[430]
    DIRECTION INPUT ;
    USE SIGNAL ;
    PORT
      LAYER M4 ;
        RECT  0 56.208 0.084 56.232 ;
    END
  END i[430]
  PIN i[431]
    DIRECTION INPUT ;
    USE SIGNAL ;
    PORT
      LAYER M4 ;
        RECT  0 56.304 0.084 56.328 ;
    END
  END i[431]
  PIN i[432]
    DIRECTION INPUT ;
    USE SIGNAL ;
    PORT
      LAYER M4 ;
        RECT  0 56.4 0.084 56.424 ;
    END
  END i[432]
  PIN i[433]
    DIRECTION INPUT ;
    USE SIGNAL ;
    PORT
      LAYER M4 ;
        RECT  0 56.496 0.084 56.52 ;
    END
  END i[433]
  PIN i[434]
    DIRECTION INPUT ;
    USE SIGNAL ;
    PORT
      LAYER M4 ;
        RECT  0 56.592 0.084 56.616 ;
    END
  END i[434]
  PIN i[435]
    DIRECTION INPUT ;
    USE SIGNAL ;
    PORT
      LAYER M4 ;
        RECT  0 56.688 0.084 56.712 ;
    END
  END i[435]
  PIN i[436]
    DIRECTION INPUT ;
    USE SIGNAL ;
    PORT
      LAYER M4 ;
        RECT  0 56.784 0.084 56.808 ;
    END
  END i[436]
  PIN i[437]
    DIRECTION INPUT ;
    USE SIGNAL ;
    PORT
      LAYER M4 ;
        RECT  0 56.88 0.084 56.904 ;
    END
  END i[437]
  PIN i[438]
    DIRECTION INPUT ;
    USE SIGNAL ;
    PORT
      LAYER M4 ;
        RECT  0 56.976 0.084 57 ;
    END
  END i[438]
  PIN i[439]
    DIRECTION INPUT ;
    USE SIGNAL ;
    PORT
      LAYER M4 ;
        RECT  0 57.072 0.084 57.096 ;
    END
  END i[439]
  PIN i[43]
    DIRECTION INPUT ;
    USE SIGNAL ;
    PORT
      LAYER M4 ;
        RECT  0 30.576 0.084 30.6 ;
    END
  END i[43]
  PIN i[440]
    DIRECTION INPUT ;
    USE SIGNAL ;
    PORT
      LAYER M4 ;
        RECT  0 57.168 0.084 57.192 ;
    END
  END i[440]
  PIN i[441]
    DIRECTION INPUT ;
    USE SIGNAL ;
    PORT
      LAYER M4 ;
        RECT  0 57.264 0.084 57.288 ;
    END
  END i[441]
  PIN i[442]
    DIRECTION INPUT ;
    USE SIGNAL ;
    PORT
      LAYER M4 ;
        RECT  0 57.36 0.084 57.384 ;
    END
  END i[442]
  PIN i[443]
    DIRECTION INPUT ;
    USE SIGNAL ;
    PORT
      LAYER M4 ;
        RECT  0 57.456 0.084 57.48 ;
    END
  END i[443]
  PIN i[444]
    DIRECTION INPUT ;
    USE SIGNAL ;
    PORT
      LAYER M4 ;
        RECT  0 57.552 0.084 57.576 ;
    END
  END i[444]
  PIN i[445]
    DIRECTION INPUT ;
    USE SIGNAL ;
    PORT
      LAYER M4 ;
        RECT  0 57.648 0.084 57.672 ;
    END
  END i[445]
  PIN i[446]
    DIRECTION INPUT ;
    USE SIGNAL ;
    PORT
      LAYER M4 ;
        RECT  0 57.744 0.084 57.768 ;
    END
  END i[446]
  PIN i[447]
    DIRECTION INPUT ;
    USE SIGNAL ;
    PORT
      LAYER M4 ;
        RECT  0 57.84 0.084 57.864 ;
    END
  END i[447]
  PIN i[448]
    DIRECTION INPUT ;
    USE SIGNAL ;
    PORT
      LAYER M4 ;
        RECT  0 51.792 0.084 51.816 ;
    END
  END i[448]
  PIN i[449]
    DIRECTION INPUT ;
    USE SIGNAL ;
    PORT
      LAYER M4 ;
        RECT  0 51.888 0.084 51.912 ;
    END
  END i[449]
  PIN i[44]
    DIRECTION INPUT ;
    USE SIGNAL ;
    PORT
      LAYER M4 ;
        RECT  0 30.672 0.084 30.696 ;
    END
  END i[44]
  PIN i[450]
    DIRECTION INPUT ;
    USE SIGNAL ;
    PORT
      LAYER M4 ;
        RECT  0 51.984 0.084 52.008 ;
    END
  END i[450]
  PIN i[451]
    DIRECTION INPUT ;
    USE SIGNAL ;
    PORT
      LAYER M4 ;
        RECT  0 52.08 0.084 52.104 ;
    END
  END i[451]
  PIN i[452]
    DIRECTION INPUT ;
    USE SIGNAL ;
    PORT
      LAYER M4 ;
        RECT  0 52.176 0.084 52.2 ;
    END
  END i[452]
  PIN i[453]
    DIRECTION INPUT ;
    USE SIGNAL ;
    PORT
      LAYER M4 ;
        RECT  0 52.272 0.084 52.296 ;
    END
  END i[453]
  PIN i[454]
    DIRECTION INPUT ;
    USE SIGNAL ;
    PORT
      LAYER M4 ;
        RECT  0 52.368 0.084 52.392 ;
    END
  END i[454]
  PIN i[455]
    DIRECTION INPUT ;
    USE SIGNAL ;
    PORT
      LAYER M4 ;
        RECT  0 52.464 0.084 52.488 ;
    END
  END i[455]
  PIN i[456]
    DIRECTION INPUT ;
    USE SIGNAL ;
    PORT
      LAYER M4 ;
        RECT  0 52.56 0.084 52.584 ;
    END
  END i[456]
  PIN i[457]
    DIRECTION INPUT ;
    USE SIGNAL ;
    PORT
      LAYER M4 ;
        RECT  0 52.656 0.084 52.68 ;
    END
  END i[457]
  PIN i[458]
    DIRECTION INPUT ;
    USE SIGNAL ;
    PORT
      LAYER M4 ;
        RECT  0 52.752 0.084 52.776 ;
    END
  END i[458]
  PIN i[459]
    DIRECTION INPUT ;
    USE SIGNAL ;
    PORT
      LAYER M4 ;
        RECT  0 52.848 0.084 52.872 ;
    END
  END i[459]
  PIN i[45]
    DIRECTION INPUT ;
    USE SIGNAL ;
    PORT
      LAYER M4 ;
        RECT  0 30.768 0.084 30.792 ;
    END
  END i[45]
  PIN i[460]
    DIRECTION INPUT ;
    USE SIGNAL ;
    PORT
      LAYER M4 ;
        RECT  0 52.944 0.084 52.968 ;
    END
  END i[460]
  PIN i[461]
    DIRECTION INPUT ;
    USE SIGNAL ;
    PORT
      LAYER M4 ;
        RECT  0 53.04 0.084 53.064 ;
    END
  END i[461]
  PIN i[462]
    DIRECTION INPUT ;
    USE SIGNAL ;
    PORT
      LAYER M4 ;
        RECT  0 53.136 0.084 53.16 ;
    END
  END i[462]
  PIN i[463]
    DIRECTION INPUT ;
    USE SIGNAL ;
    PORT
      LAYER M4 ;
        RECT  0 53.232 0.084 53.256 ;
    END
  END i[463]
  PIN i[464]
    DIRECTION INPUT ;
    USE SIGNAL ;
    PORT
      LAYER M4 ;
        RECT  0 53.328 0.084 53.352 ;
    END
  END i[464]
  PIN i[465]
    DIRECTION INPUT ;
    USE SIGNAL ;
    PORT
      LAYER M4 ;
        RECT  0 53.424 0.084 53.448 ;
    END
  END i[465]
  PIN i[466]
    DIRECTION INPUT ;
    USE SIGNAL ;
    PORT
      LAYER M4 ;
        RECT  0 53.52 0.084 53.544 ;
    END
  END i[466]
  PIN i[467]
    DIRECTION INPUT ;
    USE SIGNAL ;
    PORT
      LAYER M4 ;
        RECT  0 53.616 0.084 53.64 ;
    END
  END i[467]
  PIN i[468]
    DIRECTION INPUT ;
    USE SIGNAL ;
    PORT
      LAYER M4 ;
        RECT  0 53.712 0.084 53.736 ;
    END
  END i[468]
  PIN i[469]
    DIRECTION INPUT ;
    USE SIGNAL ;
    PORT
      LAYER M4 ;
        RECT  0 53.808 0.084 53.832 ;
    END
  END i[469]
  PIN i[46]
    DIRECTION INPUT ;
    USE SIGNAL ;
    PORT
      LAYER M4 ;
        RECT  0 30.864 0.084 30.888 ;
    END
  END i[46]
  PIN i[470]
    DIRECTION INPUT ;
    USE SIGNAL ;
    PORT
      LAYER M4 ;
        RECT  0 53.904 0.084 53.928 ;
    END
  END i[470]
  PIN i[471]
    DIRECTION INPUT ;
    USE SIGNAL ;
    PORT
      LAYER M4 ;
        RECT  0 54 0.084 54.024 ;
    END
  END i[471]
  PIN i[472]
    DIRECTION INPUT ;
    USE SIGNAL ;
    PORT
      LAYER M4 ;
        RECT  0 54.096 0.084 54.12 ;
    END
  END i[472]
  PIN i[473]
    DIRECTION INPUT ;
    USE SIGNAL ;
    PORT
      LAYER M4 ;
        RECT  0 54.192 0.084 54.216 ;
    END
  END i[473]
  PIN i[474]
    DIRECTION INPUT ;
    USE SIGNAL ;
    PORT
      LAYER M4 ;
        RECT  0 54.288 0.084 54.312 ;
    END
  END i[474]
  PIN i[475]
    DIRECTION INPUT ;
    USE SIGNAL ;
    PORT
      LAYER M4 ;
        RECT  0 54.384 0.084 54.408 ;
    END
  END i[475]
  PIN i[476]
    DIRECTION INPUT ;
    USE SIGNAL ;
    PORT
      LAYER M4 ;
        RECT  0 54.48 0.084 54.504 ;
    END
  END i[476]
  PIN i[477]
    DIRECTION INPUT ;
    USE SIGNAL ;
    PORT
      LAYER M4 ;
        RECT  0 54.576 0.084 54.6 ;
    END
  END i[477]
  PIN i[478]
    DIRECTION INPUT ;
    USE SIGNAL ;
    PORT
      LAYER M4 ;
        RECT  0 54.672 0.084 54.696 ;
    END
  END i[478]
  PIN i[479]
    DIRECTION INPUT ;
    USE SIGNAL ;
    PORT
      LAYER M4 ;
        RECT  0 54.768 0.084 54.792 ;
    END
  END i[479]
  PIN i[47]
    DIRECTION INPUT ;
    USE SIGNAL ;
    PORT
      LAYER M4 ;
        RECT  0 30.96 0.084 30.984 ;
    END
  END i[47]
  PIN i[480]
    DIRECTION INPUT ;
    USE SIGNAL ;
    PORT
      LAYER M4 ;
        RECT  0 22.608 0.084 22.632 ;
    END
  END i[480]
  PIN i[481]
    DIRECTION INPUT ;
    USE SIGNAL ;
    PORT
      LAYER M4 ;
        RECT  0 22.704 0.084 22.728 ;
    END
  END i[481]
  PIN i[482]
    DIRECTION INPUT ;
    USE SIGNAL ;
    PORT
      LAYER M4 ;
        RECT  0 22.8 0.084 22.824 ;
    END
  END i[482]
  PIN i[483]
    DIRECTION INPUT ;
    USE SIGNAL ;
    PORT
      LAYER M4 ;
        RECT  0 22.896 0.084 22.92 ;
    END
  END i[483]
  PIN i[484]
    DIRECTION INPUT ;
    USE SIGNAL ;
    PORT
      LAYER M4 ;
        RECT  0 22.992 0.084 23.016 ;
    END
  END i[484]
  PIN i[485]
    DIRECTION INPUT ;
    USE SIGNAL ;
    PORT
      LAYER M4 ;
        RECT  0 23.088 0.084 23.112 ;
    END
  END i[485]
  PIN i[486]
    DIRECTION INPUT ;
    USE SIGNAL ;
    PORT
      LAYER M4 ;
        RECT  0 23.184 0.084 23.208 ;
    END
  END i[486]
  PIN i[487]
    DIRECTION INPUT ;
    USE SIGNAL ;
    PORT
      LAYER M4 ;
        RECT  0 23.28 0.084 23.304 ;
    END
  END i[487]
  PIN i[488]
    DIRECTION INPUT ;
    USE SIGNAL ;
    PORT
      LAYER M4 ;
        RECT  0 23.376 0.084 23.4 ;
    END
  END i[488]
  PIN i[489]
    DIRECTION INPUT ;
    USE SIGNAL ;
    PORT
      LAYER M4 ;
        RECT  0 23.472 0.084 23.496 ;
    END
  END i[489]
  PIN i[48]
    DIRECTION INPUT ;
    USE SIGNAL ;
    PORT
      LAYER M4 ;
        RECT  0 31.056 0.084 31.08 ;
    END
  END i[48]
  PIN i[490]
    DIRECTION INPUT ;
    USE SIGNAL ;
    PORT
      LAYER M4 ;
        RECT  0 23.568 0.084 23.592 ;
    END
  END i[490]
  PIN i[491]
    DIRECTION INPUT ;
    USE SIGNAL ;
    PORT
      LAYER M4 ;
        RECT  0 23.664 0.084 23.688 ;
    END
  END i[491]
  PIN i[492]
    DIRECTION INPUT ;
    USE SIGNAL ;
    PORT
      LAYER M4 ;
        RECT  0 23.76 0.084 23.784 ;
    END
  END i[492]
  PIN i[493]
    DIRECTION INPUT ;
    USE SIGNAL ;
    PORT
      LAYER M4 ;
        RECT  0 23.856 0.084 23.88 ;
    END
  END i[493]
  PIN i[494]
    DIRECTION INPUT ;
    USE SIGNAL ;
    PORT
      LAYER M4 ;
        RECT  0 23.952 0.084 23.976 ;
    END
  END i[494]
  PIN i[495]
    DIRECTION INPUT ;
    USE SIGNAL ;
    PORT
      LAYER M4 ;
        RECT  0 24.048 0.084 24.072 ;
    END
  END i[495]
  PIN i[496]
    DIRECTION INPUT ;
    USE SIGNAL ;
    PORT
      LAYER M4 ;
        RECT  0 24.144 0.084 24.168 ;
    END
  END i[496]
  PIN i[497]
    DIRECTION INPUT ;
    USE SIGNAL ;
    PORT
      LAYER M4 ;
        RECT  0 24.24 0.084 24.264 ;
    END
  END i[497]
  PIN i[498]
    DIRECTION INPUT ;
    USE SIGNAL ;
    PORT
      LAYER M4 ;
        RECT  0 24.336 0.084 24.36 ;
    END
  END i[498]
  PIN i[499]
    DIRECTION INPUT ;
    USE SIGNAL ;
    PORT
      LAYER M4 ;
        RECT  0 24.432 0.084 24.456 ;
    END
  END i[499]
  PIN i[49]
    DIRECTION INPUT ;
    USE SIGNAL ;
    PORT
      LAYER M4 ;
        RECT  0 31.152 0.084 31.176 ;
    END
  END i[49]
  PIN i[4]
    DIRECTION INPUT ;
    USE SIGNAL ;
    PORT
      LAYER M4 ;
        RECT  0 7.632 0.084 7.656 ;
    END
  END i[4]
  PIN i[500]
    DIRECTION INPUT ;
    USE SIGNAL ;
    PORT
      LAYER M4 ;
        RECT  0 24.528 0.084 24.552 ;
    END
  END i[500]
  PIN i[501]
    DIRECTION INPUT ;
    USE SIGNAL ;
    PORT
      LAYER M4 ;
        RECT  0 24.624 0.084 24.648 ;
    END
  END i[501]
  PIN i[502]
    DIRECTION INPUT ;
    USE SIGNAL ;
    PORT
      LAYER M4 ;
        RECT  0 24.72 0.084 24.744 ;
    END
  END i[502]
  PIN i[503]
    DIRECTION INPUT ;
    USE SIGNAL ;
    PORT
      LAYER M4 ;
        RECT  0 24.816 0.084 24.84 ;
    END
  END i[503]
  PIN i[504]
    DIRECTION INPUT ;
    USE SIGNAL ;
    PORT
      LAYER M4 ;
        RECT  0 24.912 0.084 24.936 ;
    END
  END i[504]
  PIN i[505]
    DIRECTION INPUT ;
    USE SIGNAL ;
    PORT
      LAYER M4 ;
        RECT  0 25.008 0.084 25.032 ;
    END
  END i[505]
  PIN i[506]
    DIRECTION INPUT ;
    USE SIGNAL ;
    PORT
      LAYER M4 ;
        RECT  0 25.104 0.084 25.128 ;
    END
  END i[506]
  PIN i[507]
    DIRECTION INPUT ;
    USE SIGNAL ;
    PORT
      LAYER M4 ;
        RECT  0 25.2 0.084 25.224 ;
    END
  END i[507]
  PIN i[508]
    DIRECTION INPUT ;
    USE SIGNAL ;
    PORT
      LAYER M4 ;
        RECT  0 25.296 0.084 25.32 ;
    END
  END i[508]
  PIN i[509]
    DIRECTION INPUT ;
    USE SIGNAL ;
    PORT
      LAYER M4 ;
        RECT  0 25.392 0.084 25.416 ;
    END
  END i[509]
  PIN i[50]
    DIRECTION INPUT ;
    USE SIGNAL ;
    PORT
      LAYER M4 ;
        RECT  0 31.248 0.084 31.272 ;
    END
  END i[50]
  PIN i[510]
    DIRECTION INPUT ;
    USE SIGNAL ;
    PORT
      LAYER M4 ;
        RECT  0 25.488 0.084 25.512 ;
    END
  END i[510]
  PIN i[511]
    DIRECTION INPUT ;
    USE SIGNAL ;
    PORT
      LAYER M4 ;
        RECT  0 25.584 0.084 25.608 ;
    END
  END i[511]
  PIN i[512]
    DIRECTION INPUT ;
    USE SIGNAL ;
    PORT
      LAYER M4 ;
        RECT  0 13.392 0.084 13.416 ;
    END
  END i[512]
  PIN i[513]
    DIRECTION INPUT ;
    USE SIGNAL ;
    PORT
      LAYER M4 ;
        RECT  0 13.488 0.084 13.512 ;
    END
  END i[513]
  PIN i[514]
    DIRECTION INPUT ;
    USE SIGNAL ;
    PORT
      LAYER M4 ;
        RECT  0 13.584 0.084 13.608 ;
    END
  END i[514]
  PIN i[515]
    DIRECTION INPUT ;
    USE SIGNAL ;
    PORT
      LAYER M4 ;
        RECT  0 13.68 0.084 13.704 ;
    END
  END i[515]
  PIN i[516]
    DIRECTION INPUT ;
    USE SIGNAL ;
    PORT
      LAYER M4 ;
        RECT  0 13.776 0.084 13.8 ;
    END
  END i[516]
  PIN i[517]
    DIRECTION INPUT ;
    USE SIGNAL ;
    PORT
      LAYER M4 ;
        RECT  0 13.872 0.084 13.896 ;
    END
  END i[517]
  PIN i[518]
    DIRECTION INPUT ;
    USE SIGNAL ;
    PORT
      LAYER M4 ;
        RECT  0 13.968 0.084 13.992 ;
    END
  END i[518]
  PIN i[519]
    DIRECTION INPUT ;
    USE SIGNAL ;
    PORT
      LAYER M4 ;
        RECT  0 14.064 0.084 14.088 ;
    END
  END i[519]
  PIN i[51]
    DIRECTION INPUT ;
    USE SIGNAL ;
    PORT
      LAYER M4 ;
        RECT  0 31.344 0.084 31.368 ;
    END
  END i[51]
  PIN i[520]
    DIRECTION INPUT ;
    USE SIGNAL ;
    PORT
      LAYER M4 ;
        RECT  0 14.16 0.084 14.184 ;
    END
  END i[520]
  PIN i[521]
    DIRECTION INPUT ;
    USE SIGNAL ;
    PORT
      LAYER M4 ;
        RECT  0 14.256 0.084 14.28 ;
    END
  END i[521]
  PIN i[522]
    DIRECTION INPUT ;
    USE SIGNAL ;
    PORT
      LAYER M4 ;
        RECT  0 14.352 0.084 14.376 ;
    END
  END i[522]
  PIN i[523]
    DIRECTION INPUT ;
    USE SIGNAL ;
    PORT
      LAYER M4 ;
        RECT  0 14.448 0.084 14.472 ;
    END
  END i[523]
  PIN i[524]
    DIRECTION INPUT ;
    USE SIGNAL ;
    PORT
      LAYER M4 ;
        RECT  0 14.544 0.084 14.568 ;
    END
  END i[524]
  PIN i[525]
    DIRECTION INPUT ;
    USE SIGNAL ;
    PORT
      LAYER M4 ;
        RECT  0 14.64 0.084 14.664 ;
    END
  END i[525]
  PIN i[526]
    DIRECTION INPUT ;
    USE SIGNAL ;
    PORT
      LAYER M4 ;
        RECT  0 14.736 0.084 14.76 ;
    END
  END i[526]
  PIN i[527]
    DIRECTION INPUT ;
    USE SIGNAL ;
    PORT
      LAYER M4 ;
        RECT  0 14.832 0.084 14.856 ;
    END
  END i[527]
  PIN i[528]
    DIRECTION INPUT ;
    USE SIGNAL ;
    PORT
      LAYER M4 ;
        RECT  0 14.928 0.084 14.952 ;
    END
  END i[528]
  PIN i[529]
    DIRECTION INPUT ;
    USE SIGNAL ;
    PORT
      LAYER M4 ;
        RECT  0 15.024 0.084 15.048 ;
    END
  END i[529]
  PIN i[52]
    DIRECTION INPUT ;
    USE SIGNAL ;
    PORT
      LAYER M4 ;
        RECT  0 31.44 0.084 31.464 ;
    END
  END i[52]
  PIN i[530]
    DIRECTION INPUT ;
    USE SIGNAL ;
    PORT
      LAYER M4 ;
        RECT  0 15.12 0.084 15.144 ;
    END
  END i[530]
  PIN i[531]
    DIRECTION INPUT ;
    USE SIGNAL ;
    PORT
      LAYER M4 ;
        RECT  0 15.216 0.084 15.24 ;
    END
  END i[531]
  PIN i[532]
    DIRECTION INPUT ;
    USE SIGNAL ;
    PORT
      LAYER M4 ;
        RECT  0 15.312 0.084 15.336 ;
    END
  END i[532]
  PIN i[533]
    DIRECTION INPUT ;
    USE SIGNAL ;
    PORT
      LAYER M4 ;
        RECT  0 15.408 0.084 15.432 ;
    END
  END i[533]
  PIN i[534]
    DIRECTION INPUT ;
    USE SIGNAL ;
    PORT
      LAYER M4 ;
        RECT  0 15.504 0.084 15.528 ;
    END
  END i[534]
  PIN i[535]
    DIRECTION INPUT ;
    USE SIGNAL ;
    PORT
      LAYER M4 ;
        RECT  0 15.6 0.084 15.624 ;
    END
  END i[535]
  PIN i[536]
    DIRECTION INPUT ;
    USE SIGNAL ;
    PORT
      LAYER M4 ;
        RECT  0 15.696 0.084 15.72 ;
    END
  END i[536]
  PIN i[537]
    DIRECTION INPUT ;
    USE SIGNAL ;
    PORT
      LAYER M4 ;
        RECT  0 15.792 0.084 15.816 ;
    END
  END i[537]
  PIN i[538]
    DIRECTION INPUT ;
    USE SIGNAL ;
    PORT
      LAYER M4 ;
        RECT  0 15.888 0.084 15.912 ;
    END
  END i[538]
  PIN i[539]
    DIRECTION INPUT ;
    USE SIGNAL ;
    PORT
      LAYER M4 ;
        RECT  0 15.984 0.084 16.008 ;
    END
  END i[539]
  PIN i[53]
    DIRECTION INPUT ;
    USE SIGNAL ;
    PORT
      LAYER M4 ;
        RECT  0 31.536 0.084 31.56 ;
    END
  END i[53]
  PIN i[540]
    DIRECTION INPUT ;
    USE SIGNAL ;
    PORT
      LAYER M4 ;
        RECT  0 16.08 0.084 16.104 ;
    END
  END i[540]
  PIN i[541]
    DIRECTION INPUT ;
    USE SIGNAL ;
    PORT
      LAYER M4 ;
        RECT  0 16.176 0.084 16.2 ;
    END
  END i[541]
  PIN i[542]
    DIRECTION INPUT ;
    USE SIGNAL ;
    PORT
      LAYER M4 ;
        RECT  0 16.272 0.084 16.296 ;
    END
  END i[542]
  PIN i[543]
    DIRECTION INPUT ;
    USE SIGNAL ;
    PORT
      LAYER M4 ;
        RECT  0 16.368 0.084 16.392 ;
    END
  END i[543]
  PIN i[544]
    DIRECTION INPUT ;
    USE SIGNAL ;
    PORT
      LAYER M4 ;
        RECT  0 10.32 0.084 10.344 ;
    END
  END i[544]
  PIN i[545]
    DIRECTION INPUT ;
    USE SIGNAL ;
    PORT
      LAYER M4 ;
        RECT  0 10.416 0.084 10.44 ;
    END
  END i[545]
  PIN i[546]
    DIRECTION INPUT ;
    USE SIGNAL ;
    PORT
      LAYER M4 ;
        RECT  0 10.512 0.084 10.536 ;
    END
  END i[546]
  PIN i[547]
    DIRECTION INPUT ;
    USE SIGNAL ;
    PORT
      LAYER M4 ;
        RECT  0 10.608 0.084 10.632 ;
    END
  END i[547]
  PIN i[548]
    DIRECTION INPUT ;
    USE SIGNAL ;
    PORT
      LAYER M4 ;
        RECT  0 10.704 0.084 10.728 ;
    END
  END i[548]
  PIN i[549]
    DIRECTION INPUT ;
    USE SIGNAL ;
    PORT
      LAYER M4 ;
        RECT  0 10.8 0.084 10.824 ;
    END
  END i[549]
  PIN i[54]
    DIRECTION INPUT ;
    USE SIGNAL ;
    PORT
      LAYER M4 ;
        RECT  0 31.632 0.084 31.656 ;
    END
  END i[54]
  PIN i[550]
    DIRECTION INPUT ;
    USE SIGNAL ;
    PORT
      LAYER M4 ;
        RECT  0 10.896 0.084 10.92 ;
    END
  END i[550]
  PIN i[551]
    DIRECTION INPUT ;
    USE SIGNAL ;
    PORT
      LAYER M4 ;
        RECT  0 10.992 0.084 11.016 ;
    END
  END i[551]
  PIN i[552]
    DIRECTION INPUT ;
    USE SIGNAL ;
    PORT
      LAYER M4 ;
        RECT  0 11.088 0.084 11.112 ;
    END
  END i[552]
  PIN i[553]
    DIRECTION INPUT ;
    USE SIGNAL ;
    PORT
      LAYER M4 ;
        RECT  0 11.184 0.084 11.208 ;
    END
  END i[553]
  PIN i[554]
    DIRECTION INPUT ;
    USE SIGNAL ;
    PORT
      LAYER M4 ;
        RECT  0 11.28 0.084 11.304 ;
    END
  END i[554]
  PIN i[555]
    DIRECTION INPUT ;
    USE SIGNAL ;
    PORT
      LAYER M4 ;
        RECT  0 11.376 0.084 11.4 ;
    END
  END i[555]
  PIN i[556]
    DIRECTION INPUT ;
    USE SIGNAL ;
    PORT
      LAYER M4 ;
        RECT  0 11.472 0.084 11.496 ;
    END
  END i[556]
  PIN i[557]
    DIRECTION INPUT ;
    USE SIGNAL ;
    PORT
      LAYER M4 ;
        RECT  0 11.568 0.084 11.592 ;
    END
  END i[557]
  PIN i[558]
    DIRECTION INPUT ;
    USE SIGNAL ;
    PORT
      LAYER M4 ;
        RECT  0 11.664 0.084 11.688 ;
    END
  END i[558]
  PIN i[559]
    DIRECTION INPUT ;
    USE SIGNAL ;
    PORT
      LAYER M4 ;
        RECT  0 11.76 0.084 11.784 ;
    END
  END i[559]
  PIN i[55]
    DIRECTION INPUT ;
    USE SIGNAL ;
    PORT
      LAYER M4 ;
        RECT  0 31.728 0.084 31.752 ;
    END
  END i[55]
  PIN i[560]
    DIRECTION INPUT ;
    USE SIGNAL ;
    PORT
      LAYER M4 ;
        RECT  0 11.856 0.084 11.88 ;
    END
  END i[560]
  PIN i[561]
    DIRECTION INPUT ;
    USE SIGNAL ;
    PORT
      LAYER M4 ;
        RECT  0 11.952 0.084 11.976 ;
    END
  END i[561]
  PIN i[562]
    DIRECTION INPUT ;
    USE SIGNAL ;
    PORT
      LAYER M4 ;
        RECT  0 12.048 0.084 12.072 ;
    END
  END i[562]
  PIN i[563]
    DIRECTION INPUT ;
    USE SIGNAL ;
    PORT
      LAYER M4 ;
        RECT  0 12.144 0.084 12.168 ;
    END
  END i[563]
  PIN i[564]
    DIRECTION INPUT ;
    USE SIGNAL ;
    PORT
      LAYER M4 ;
        RECT  0 12.24 0.084 12.264 ;
    END
  END i[564]
  PIN i[565]
    DIRECTION INPUT ;
    USE SIGNAL ;
    PORT
      LAYER M4 ;
        RECT  0 12.336 0.084 12.36 ;
    END
  END i[565]
  PIN i[566]
    DIRECTION INPUT ;
    USE SIGNAL ;
    PORT
      LAYER M4 ;
        RECT  0 12.432 0.084 12.456 ;
    END
  END i[566]
  PIN i[567]
    DIRECTION INPUT ;
    USE SIGNAL ;
    PORT
      LAYER M4 ;
        RECT  0 12.528 0.084 12.552 ;
    END
  END i[567]
  PIN i[568]
    DIRECTION INPUT ;
    USE SIGNAL ;
    PORT
      LAYER M4 ;
        RECT  0 12.624 0.084 12.648 ;
    END
  END i[568]
  PIN i[569]
    DIRECTION INPUT ;
    USE SIGNAL ;
    PORT
      LAYER M4 ;
        RECT  0 12.72 0.084 12.744 ;
    END
  END i[569]
  PIN i[56]
    DIRECTION INPUT ;
    USE SIGNAL ;
    PORT
      LAYER M4 ;
        RECT  0 31.824 0.084 31.848 ;
    END
  END i[56]
  PIN i[570]
    DIRECTION INPUT ;
    USE SIGNAL ;
    PORT
      LAYER M4 ;
        RECT  0 12.816 0.084 12.84 ;
    END
  END i[570]
  PIN i[571]
    DIRECTION INPUT ;
    USE SIGNAL ;
    PORT
      LAYER M4 ;
        RECT  0 12.912 0.084 12.936 ;
    END
  END i[571]
  PIN i[572]
    DIRECTION INPUT ;
    USE SIGNAL ;
    PORT
      LAYER M4 ;
        RECT  0 13.008 0.084 13.032 ;
    END
  END i[572]
  PIN i[573]
    DIRECTION INPUT ;
    USE SIGNAL ;
    PORT
      LAYER M4 ;
        RECT  0 13.104 0.084 13.128 ;
    END
  END i[573]
  PIN i[574]
    DIRECTION INPUT ;
    USE SIGNAL ;
    PORT
      LAYER M4 ;
        RECT  0 13.2 0.084 13.224 ;
    END
  END i[574]
  PIN i[575]
    DIRECTION INPUT ;
    USE SIGNAL ;
    PORT
      LAYER M4 ;
        RECT  0 13.296 0.084 13.32 ;
    END
  END i[575]
  PIN i[576]
    DIRECTION INPUT ;
    USE SIGNAL ;
    PORT
      LAYER M4 ;
        RECT  0 3.408 0.084 3.432 ;
    END
  END i[576]
  PIN i[577]
    DIRECTION INPUT ;
    USE SIGNAL ;
    PORT
      LAYER M4 ;
        RECT  0 3.504 0.084 3.528 ;
    END
  END i[577]
  PIN i[578]
    DIRECTION INPUT ;
    USE SIGNAL ;
    PORT
      LAYER M4 ;
        RECT  0 3.6 0.084 3.624 ;
    END
  END i[578]
  PIN i[579]
    DIRECTION INPUT ;
    USE SIGNAL ;
    PORT
      LAYER M4 ;
        RECT  0 3.696 0.084 3.72 ;
    END
  END i[579]
  PIN i[57]
    DIRECTION INPUT ;
    USE SIGNAL ;
    PORT
      LAYER M4 ;
        RECT  0 31.92 0.084 31.944 ;
    END
  END i[57]
  PIN i[580]
    DIRECTION INPUT ;
    USE SIGNAL ;
    PORT
      LAYER M4 ;
        RECT  0 3.792 0.084 3.816 ;
    END
  END i[580]
  PIN i[581]
    DIRECTION INPUT ;
    USE SIGNAL ;
    PORT
      LAYER M4 ;
        RECT  0 3.888 0.084 3.912 ;
    END
  END i[581]
  PIN i[582]
    DIRECTION INPUT ;
    USE SIGNAL ;
    PORT
      LAYER M4 ;
        RECT  0 3.984 0.084 4.008 ;
    END
  END i[582]
  PIN i[583]
    DIRECTION INPUT ;
    USE SIGNAL ;
    PORT
      LAYER M4 ;
        RECT  0 4.08 0.084 4.104 ;
    END
  END i[583]
  PIN i[584]
    DIRECTION INPUT ;
    USE SIGNAL ;
    PORT
      LAYER M4 ;
        RECT  0 4.176 0.084 4.2 ;
    END
  END i[584]
  PIN i[585]
    DIRECTION INPUT ;
    USE SIGNAL ;
    PORT
      LAYER M4 ;
        RECT  0 4.272 0.084 4.296 ;
    END
  END i[585]
  PIN i[586]
    DIRECTION INPUT ;
    USE SIGNAL ;
    PORT
      LAYER M4 ;
        RECT  0 4.368 0.084 4.392 ;
    END
  END i[586]
  PIN i[587]
    DIRECTION INPUT ;
    USE SIGNAL ;
    PORT
      LAYER M4 ;
        RECT  0 4.464 0.084 4.488 ;
    END
  END i[587]
  PIN i[588]
    DIRECTION INPUT ;
    USE SIGNAL ;
    PORT
      LAYER M4 ;
        RECT  0 4.56 0.084 4.584 ;
    END
  END i[588]
  PIN i[589]
    DIRECTION INPUT ;
    USE SIGNAL ;
    PORT
      LAYER M4 ;
        RECT  0 4.656 0.084 4.68 ;
    END
  END i[589]
  PIN i[58]
    DIRECTION INPUT ;
    USE SIGNAL ;
    PORT
      LAYER M4 ;
        RECT  0 32.016 0.084 32.04 ;
    END
  END i[58]
  PIN i[590]
    DIRECTION INPUT ;
    USE SIGNAL ;
    PORT
      LAYER M4 ;
        RECT  0 4.752 0.084 4.776 ;
    END
  END i[590]
  PIN i[591]
    DIRECTION INPUT ;
    USE SIGNAL ;
    PORT
      LAYER M4 ;
        RECT  0 4.848 0.084 4.872 ;
    END
  END i[591]
  PIN i[592]
    DIRECTION INPUT ;
    USE SIGNAL ;
    PORT
      LAYER M4 ;
        RECT  0 4.944 0.084 4.968 ;
    END
  END i[592]
  PIN i[593]
    DIRECTION INPUT ;
    USE SIGNAL ;
    PORT
      LAYER M4 ;
        RECT  0 5.04 0.084 5.064 ;
    END
  END i[593]
  PIN i[594]
    DIRECTION INPUT ;
    USE SIGNAL ;
    PORT
      LAYER M4 ;
        RECT  0 5.136 0.084 5.16 ;
    END
  END i[594]
  PIN i[595]
    DIRECTION INPUT ;
    USE SIGNAL ;
    PORT
      LAYER M4 ;
        RECT  0 5.232 0.084 5.256 ;
    END
  END i[595]
  PIN i[596]
    DIRECTION INPUT ;
    USE SIGNAL ;
    PORT
      LAYER M4 ;
        RECT  0 5.328 0.084 5.352 ;
    END
  END i[596]
  PIN i[597]
    DIRECTION INPUT ;
    USE SIGNAL ;
    PORT
      LAYER M4 ;
        RECT  0 5.424 0.084 5.448 ;
    END
  END i[597]
  PIN i[598]
    DIRECTION INPUT ;
    USE SIGNAL ;
    PORT
      LAYER M4 ;
        RECT  0 5.52 0.084 5.544 ;
    END
  END i[598]
  PIN i[599]
    DIRECTION INPUT ;
    USE SIGNAL ;
    PORT
      LAYER M4 ;
        RECT  0 5.616 0.084 5.64 ;
    END
  END i[599]
  PIN i[59]
    DIRECTION INPUT ;
    USE SIGNAL ;
    PORT
      LAYER M4 ;
        RECT  0 32.112 0.084 32.136 ;
    END
  END i[59]
  PIN i[5]
    DIRECTION INPUT ;
    USE SIGNAL ;
    PORT
      LAYER M4 ;
        RECT  0 7.728 0.084 7.752 ;
    END
  END i[5]
  PIN i[600]
    DIRECTION INPUT ;
    USE SIGNAL ;
    PORT
      LAYER M4 ;
        RECT  0 5.712 0.084 5.736 ;
    END
  END i[600]
  PIN i[601]
    DIRECTION INPUT ;
    USE SIGNAL ;
    PORT
      LAYER M4 ;
        RECT  0 5.808 0.084 5.832 ;
    END
  END i[601]
  PIN i[602]
    DIRECTION INPUT ;
    USE SIGNAL ;
    PORT
      LAYER M4 ;
        RECT  0 5.904 0.084 5.928 ;
    END
  END i[602]
  PIN i[603]
    DIRECTION INPUT ;
    USE SIGNAL ;
    PORT
      LAYER M4 ;
        RECT  0 6 0.084 6.024 ;
    END
  END i[603]
  PIN i[604]
    DIRECTION INPUT ;
    USE SIGNAL ;
    PORT
      LAYER M4 ;
        RECT  0 6.096 0.084 6.12 ;
    END
  END i[604]
  PIN i[605]
    DIRECTION INPUT ;
    USE SIGNAL ;
    PORT
      LAYER M4 ;
        RECT  0 6.192 0.084 6.216 ;
    END
  END i[605]
  PIN i[606]
    DIRECTION INPUT ;
    USE SIGNAL ;
    PORT
      LAYER M4 ;
        RECT  0 6.288 0.084 6.312 ;
    END
  END i[606]
  PIN i[607]
    DIRECTION INPUT ;
    USE SIGNAL ;
    PORT
      LAYER M4 ;
        RECT  0 6.384 0.084 6.408 ;
    END
  END i[607]
  PIN i[608]
    DIRECTION INPUT ;
    USE SIGNAL ;
    PORT
      LAYER M4 ;
        RECT  0 1.872 0.084 1.896 ;
    END
  END i[608]
  PIN i[609]
    DIRECTION INPUT ;
    USE SIGNAL ;
    PORT
      LAYER M4 ;
        RECT  0 1.968 0.084 1.992 ;
    END
  END i[609]
  PIN i[60]
    DIRECTION INPUT ;
    USE SIGNAL ;
    PORT
      LAYER M4 ;
        RECT  0 32.208 0.084 32.232 ;
    END
  END i[60]
  PIN i[610]
    DIRECTION INPUT ;
    USE SIGNAL ;
    PORT
      LAYER M4 ;
        RECT  0 2.064 0.084 2.088 ;
    END
  END i[610]
  PIN i[611]
    DIRECTION INPUT ;
    USE SIGNAL ;
    PORT
      LAYER M4 ;
        RECT  0 2.16 0.084 2.184 ;
    END
  END i[611]
  PIN i[612]
    DIRECTION INPUT ;
    USE SIGNAL ;
    PORT
      LAYER M4 ;
        RECT  0 2.256 0.084 2.28 ;
    END
  END i[612]
  PIN i[613]
    DIRECTION INPUT ;
    USE SIGNAL ;
    PORT
      LAYER M4 ;
        RECT  0 2.352 0.084 2.376 ;
    END
  END i[613]
  PIN i[614]
    DIRECTION INPUT ;
    USE SIGNAL ;
    PORT
      LAYER M4 ;
        RECT  0 2.448 0.084 2.472 ;
    END
  END i[614]
  PIN i[615]
    DIRECTION INPUT ;
    USE SIGNAL ;
    PORT
      LAYER M4 ;
        RECT  0 2.544 0.084 2.568 ;
    END
  END i[615]
  PIN i[616]
    DIRECTION INPUT ;
    USE SIGNAL ;
    PORT
      LAYER M4 ;
        RECT  0 2.64 0.084 2.664 ;
    END
  END i[616]
  PIN i[617]
    DIRECTION INPUT ;
    USE SIGNAL ;
    PORT
      LAYER M4 ;
        RECT  0 2.736 0.084 2.76 ;
    END
  END i[617]
  PIN i[618]
    DIRECTION INPUT ;
    USE SIGNAL ;
    PORT
      LAYER M4 ;
        RECT  0 2.832 0.084 2.856 ;
    END
  END i[618]
  PIN i[619]
    DIRECTION INPUT ;
    USE SIGNAL ;
    PORT
      LAYER M4 ;
        RECT  0 2.928 0.084 2.952 ;
    END
  END i[619]
  PIN i[61]
    DIRECTION INPUT ;
    USE SIGNAL ;
    PORT
      LAYER M4 ;
        RECT  0 32.304 0.084 32.328 ;
    END
  END i[61]
  PIN i[620]
    DIRECTION INPUT ;
    USE SIGNAL ;
    PORT
      LAYER M4 ;
        RECT  0 3.024 0.084 3.048 ;
    END
  END i[620]
  PIN i[621]
    DIRECTION INPUT ;
    USE SIGNAL ;
    PORT
      LAYER M4 ;
        RECT  0 3.12 0.084 3.144 ;
    END
  END i[621]
  PIN i[622]
    DIRECTION INPUT ;
    USE SIGNAL ;
    PORT
      LAYER M4 ;
        RECT  0 3.216 0.084 3.24 ;
    END
  END i[622]
  PIN i[623]
    DIRECTION INPUT ;
    USE SIGNAL ;
    PORT
      LAYER M4 ;
        RECT  0 3.312 0.084 3.336 ;
    END
  END i[623]
  PIN i[62]
    DIRECTION INPUT ;
    USE SIGNAL ;
    PORT
      LAYER M4 ;
        RECT  0 32.4 0.084 32.424 ;
    END
  END i[62]
  PIN i[63]
    DIRECTION INPUT ;
    USE SIGNAL ;
    PORT
      LAYER M4 ;
        RECT  0 32.496 0.084 32.52 ;
    END
  END i[63]
  PIN i[64]
    DIRECTION INPUT ;
    USE SIGNAL ;
    PORT
      LAYER M4 ;
        RECT  0 26.448 0.084 26.472 ;
    END
  END i[64]
  PIN i[65]
    DIRECTION INPUT ;
    USE SIGNAL ;
    PORT
      LAYER M4 ;
        RECT  0 26.544 0.084 26.568 ;
    END
  END i[65]
  PIN i[66]
    DIRECTION INPUT ;
    USE SIGNAL ;
    PORT
      LAYER M4 ;
        RECT  0 26.64 0.084 26.664 ;
    END
  END i[66]
  PIN i[67]
    DIRECTION INPUT ;
    USE SIGNAL ;
    PORT
      LAYER M4 ;
        RECT  0 26.736 0.084 26.76 ;
    END
  END i[67]
  PIN i[68]
    DIRECTION INPUT ;
    USE SIGNAL ;
    PORT
      LAYER M4 ;
        RECT  0 26.832 0.084 26.856 ;
    END
  END i[68]
  PIN i[69]
    DIRECTION INPUT ;
    USE SIGNAL ;
    PORT
      LAYER M4 ;
        RECT  0 26.928 0.084 26.952 ;
    END
  END i[69]
  PIN i[6]
    DIRECTION INPUT ;
    USE SIGNAL ;
    PORT
      LAYER M4 ;
        RECT  0 7.824 0.084 7.848 ;
    END
  END i[6]
  PIN i[70]
    DIRECTION INPUT ;
    USE SIGNAL ;
    PORT
      LAYER M4 ;
        RECT  0 27.024 0.084 27.048 ;
    END
  END i[70]
  PIN i[71]
    DIRECTION INPUT ;
    USE SIGNAL ;
    PORT
      LAYER M4 ;
        RECT  0 27.12 0.084 27.144 ;
    END
  END i[71]
  PIN i[72]
    DIRECTION INPUT ;
    USE SIGNAL ;
    PORT
      LAYER M4 ;
        RECT  0 27.216 0.084 27.24 ;
    END
  END i[72]
  PIN i[73]
    DIRECTION INPUT ;
    USE SIGNAL ;
    PORT
      LAYER M4 ;
        RECT  0 27.312 0.084 27.336 ;
    END
  END i[73]
  PIN i[74]
    DIRECTION INPUT ;
    USE SIGNAL ;
    PORT
      LAYER M4 ;
        RECT  0 27.408 0.084 27.432 ;
    END
  END i[74]
  PIN i[75]
    DIRECTION INPUT ;
    USE SIGNAL ;
    PORT
      LAYER M4 ;
        RECT  0 27.504 0.084 27.528 ;
    END
  END i[75]
  PIN i[76]
    DIRECTION INPUT ;
    USE SIGNAL ;
    PORT
      LAYER M4 ;
        RECT  0 27.6 0.084 27.624 ;
    END
  END i[76]
  PIN i[77]
    DIRECTION INPUT ;
    USE SIGNAL ;
    PORT
      LAYER M4 ;
        RECT  0 27.696 0.084 27.72 ;
    END
  END i[77]
  PIN i[78]
    DIRECTION INPUT ;
    USE SIGNAL ;
    PORT
      LAYER M4 ;
        RECT  0 27.792 0.084 27.816 ;
    END
  END i[78]
  PIN i[79]
    DIRECTION INPUT ;
    USE SIGNAL ;
    PORT
      LAYER M4 ;
        RECT  0 27.888 0.084 27.912 ;
    END
  END i[79]
  PIN i[7]
    DIRECTION INPUT ;
    USE SIGNAL ;
    PORT
      LAYER M4 ;
        RECT  0 7.92 0.084 7.944 ;
    END
  END i[7]
  PIN i[80]
    DIRECTION INPUT ;
    USE SIGNAL ;
    PORT
      LAYER M4 ;
        RECT  0 27.984 0.084 28.008 ;
    END
  END i[80]
  PIN i[81]
    DIRECTION INPUT ;
    USE SIGNAL ;
    PORT
      LAYER M4 ;
        RECT  0 28.08 0.084 28.104 ;
    END
  END i[81]
  PIN i[82]
    DIRECTION INPUT ;
    USE SIGNAL ;
    PORT
      LAYER M4 ;
        RECT  0 28.176 0.084 28.2 ;
    END
  END i[82]
  PIN i[83]
    DIRECTION INPUT ;
    USE SIGNAL ;
    PORT
      LAYER M4 ;
        RECT  0 28.272 0.084 28.296 ;
    END
  END i[83]
  PIN i[84]
    DIRECTION INPUT ;
    USE SIGNAL ;
    PORT
      LAYER M4 ;
        RECT  0 28.368 0.084 28.392 ;
    END
  END i[84]
  PIN i[85]
    DIRECTION INPUT ;
    USE SIGNAL ;
    PORT
      LAYER M4 ;
        RECT  0 28.464 0.084 28.488 ;
    END
  END i[85]
  PIN i[86]
    DIRECTION INPUT ;
    USE SIGNAL ;
    PORT
      LAYER M4 ;
        RECT  0 28.56 0.084 28.584 ;
    END
  END i[86]
  PIN i[87]
    DIRECTION INPUT ;
    USE SIGNAL ;
    PORT
      LAYER M4 ;
        RECT  0 28.656 0.084 28.68 ;
    END
  END i[87]
  PIN i[88]
    DIRECTION INPUT ;
    USE SIGNAL ;
    PORT
      LAYER M4 ;
        RECT  0 28.752 0.084 28.776 ;
    END
  END i[88]
  PIN i[89]
    DIRECTION INPUT ;
    USE SIGNAL ;
    PORT
      LAYER M4 ;
        RECT  0 28.848 0.084 28.872 ;
    END
  END i[89]
  PIN i[8]
    DIRECTION INPUT ;
    USE SIGNAL ;
    PORT
      LAYER M4 ;
        RECT  0 8.016 0.084 8.04 ;
    END
  END i[8]
  PIN i[90]
    DIRECTION INPUT ;
    USE SIGNAL ;
    PORT
      LAYER M4 ;
        RECT  0 28.944 0.084 28.968 ;
    END
  END i[90]
  PIN i[91]
    DIRECTION INPUT ;
    USE SIGNAL ;
    PORT
      LAYER M4 ;
        RECT  0 29.04 0.084 29.064 ;
    END
  END i[91]
  PIN i[92]
    DIRECTION INPUT ;
    USE SIGNAL ;
    PORT
      LAYER M4 ;
        RECT  0 29.136 0.084 29.16 ;
    END
  END i[92]
  PIN i[93]
    DIRECTION INPUT ;
    USE SIGNAL ;
    PORT
      LAYER M4 ;
        RECT  0 29.232 0.084 29.256 ;
    END
  END i[93]
  PIN i[94]
    DIRECTION INPUT ;
    USE SIGNAL ;
    PORT
      LAYER M4 ;
        RECT  0 29.328 0.084 29.352 ;
    END
  END i[94]
  PIN i[95]
    DIRECTION INPUT ;
    USE SIGNAL ;
    PORT
      LAYER M4 ;
        RECT  0 29.424 0.084 29.448 ;
    END
  END i[95]
  PIN i[96]
    DIRECTION INPUT ;
    USE SIGNAL ;
    PORT
      LAYER M4 ;
        RECT  0 35.664 0.084 35.688 ;
    END
  END i[96]
  PIN i[97]
    DIRECTION INPUT ;
    USE SIGNAL ;
    PORT
      LAYER M4 ;
        RECT  0 35.76 0.084 35.784 ;
    END
  END i[97]
  PIN i[98]
    DIRECTION INPUT ;
    USE SIGNAL ;
    PORT
      LAYER M4 ;
        RECT  0 35.856 0.084 35.88 ;
    END
  END i[98]
  PIN i[99]
    DIRECTION INPUT ;
    USE SIGNAL ;
    PORT
      LAYER M4 ;
        RECT  0 35.952 0.084 35.976 ;
    END
  END i[99]
  PIN i[9]
    DIRECTION INPUT ;
    USE SIGNAL ;
    PORT
      LAYER M4 ;
        RECT  0 8.112 0.084 8.136 ;
    END
  END i[9]
  PIN o[0]
    DIRECTION OUTPUT ;
    USE SIGNAL ;
    PORT
      LAYER M4 ;
        RECT  21.516 19.92 21.6 19.944 ;
    END
  END o[0]
  PIN o[100]
    DIRECTION OUTPUT ;
    USE SIGNAL ;
    PORT
      LAYER M4 ;
        RECT  21.516 35.664 21.6 35.688 ;
    END
  END o[100]
  PIN o[101]
    DIRECTION OUTPUT ;
    USE SIGNAL ;
    PORT
      LAYER M4 ;
        RECT  21.516 35.76 21.6 35.784 ;
    END
  END o[101]
  PIN o[102]
    DIRECTION OUTPUT ;
    USE SIGNAL ;
    PORT
      LAYER M4 ;
        RECT  21.516 35.856 21.6 35.88 ;
    END
  END o[102]
  PIN o[103]
    DIRECTION OUTPUT ;
    USE SIGNAL ;
    PORT
      LAYER M4 ;
        RECT  21.516 35.952 21.6 35.976 ;
    END
  END o[103]
  PIN o[104]
    DIRECTION OUTPUT ;
    USE SIGNAL ;
    PORT
      LAYER M4 ;
        RECT  21.516 36.048 21.6 36.072 ;
    END
  END o[104]
  PIN o[105]
    DIRECTION OUTPUT ;
    USE SIGNAL ;
    PORT
      LAYER M4 ;
        RECT  21.516 36.144 21.6 36.168 ;
    END
  END o[105]
  PIN o[106]
    DIRECTION OUTPUT ;
    USE SIGNAL ;
    PORT
      LAYER M4 ;
        RECT  21.516 36.24 21.6 36.264 ;
    END
  END o[106]
  PIN o[107]
    DIRECTION OUTPUT ;
    USE SIGNAL ;
    PORT
      LAYER M4 ;
        RECT  21.516 36.336 21.6 36.36 ;
    END
  END o[107]
  PIN o[108]
    DIRECTION OUTPUT ;
    USE SIGNAL ;
    PORT
      LAYER M4 ;
        RECT  21.516 36.432 21.6 36.456 ;
    END
  END o[108]
  PIN o[109]
    DIRECTION OUTPUT ;
    USE SIGNAL ;
    PORT
      LAYER M4 ;
        RECT  21.516 36.528 21.6 36.552 ;
    END
  END o[109]
  PIN o[10]
    DIRECTION OUTPUT ;
    USE SIGNAL ;
    PORT
      LAYER M4 ;
        RECT  21.516 20.88 21.6 20.904 ;
    END
  END o[10]
  PIN o[110]
    DIRECTION OUTPUT ;
    USE SIGNAL ;
    PORT
      LAYER M4 ;
        RECT  21.516 36.624 21.6 36.648 ;
    END
  END o[110]
  PIN o[111]
    DIRECTION OUTPUT ;
    USE SIGNAL ;
    PORT
      LAYER M4 ;
        RECT  21.516 36.72 21.6 36.744 ;
    END
  END o[111]
  PIN o[112]
    DIRECTION OUTPUT ;
    USE SIGNAL ;
    PORT
      LAYER M4 ;
        RECT  21.516 36.816 21.6 36.84 ;
    END
  END o[112]
  PIN o[113]
    DIRECTION OUTPUT ;
    USE SIGNAL ;
    PORT
      LAYER M4 ;
        RECT  21.516 36.912 21.6 36.936 ;
    END
  END o[113]
  PIN o[114]
    DIRECTION OUTPUT ;
    USE SIGNAL ;
    PORT
      LAYER M4 ;
        RECT  21.516 37.008 21.6 37.032 ;
    END
  END o[114]
  PIN o[115]
    DIRECTION OUTPUT ;
    USE SIGNAL ;
    PORT
      LAYER M4 ;
        RECT  21.516 37.104 21.6 37.128 ;
    END
  END o[115]
  PIN o[116]
    DIRECTION OUTPUT ;
    USE SIGNAL ;
    PORT
      LAYER M4 ;
        RECT  21.516 37.2 21.6 37.224 ;
    END
  END o[116]
  PIN o[117]
    DIRECTION OUTPUT ;
    USE SIGNAL ;
    PORT
      LAYER M4 ;
        RECT  21.516 37.296 21.6 37.32 ;
    END
  END o[117]
  PIN o[118]
    DIRECTION OUTPUT ;
    USE SIGNAL ;
    PORT
      LAYER M4 ;
        RECT  21.516 37.392 21.6 37.416 ;
    END
  END o[118]
  PIN o[119]
    DIRECTION OUTPUT ;
    USE SIGNAL ;
    PORT
      LAYER M4 ;
        RECT  21.516 37.488 21.6 37.512 ;
    END
  END o[119]
  PIN o[11]
    DIRECTION OUTPUT ;
    USE SIGNAL ;
    PORT
      LAYER M4 ;
        RECT  21.516 20.976 21.6 21 ;
    END
  END o[11]
  PIN o[120]
    DIRECTION OUTPUT ;
    USE SIGNAL ;
    PORT
      LAYER M4 ;
        RECT  21.516 37.584 21.6 37.608 ;
    END
  END o[120]
  PIN o[121]
    DIRECTION OUTPUT ;
    USE SIGNAL ;
    PORT
      LAYER M4 ;
        RECT  21.516 37.68 21.6 37.704 ;
    END
  END o[121]
  PIN o[122]
    DIRECTION OUTPUT ;
    USE SIGNAL ;
    PORT
      LAYER M4 ;
        RECT  21.516 37.776 21.6 37.8 ;
    END
  END o[122]
  PIN o[123]
    DIRECTION OUTPUT ;
    USE SIGNAL ;
    PORT
      LAYER M4 ;
        RECT  21.516 37.872 21.6 37.896 ;
    END
  END o[123]
  PIN o[124]
    DIRECTION OUTPUT ;
    USE SIGNAL ;
    PORT
      LAYER M4 ;
        RECT  21.516 37.968 21.6 37.992 ;
    END
  END o[124]
  PIN o[125]
    DIRECTION OUTPUT ;
    USE SIGNAL ;
    PORT
      LAYER M4 ;
        RECT  21.516 38.064 21.6 38.088 ;
    END
  END o[125]
  PIN o[126]
    DIRECTION OUTPUT ;
    USE SIGNAL ;
    PORT
      LAYER M4 ;
        RECT  21.516 38.16 21.6 38.184 ;
    END
  END o[126]
  PIN o[127]
    DIRECTION OUTPUT ;
    USE SIGNAL ;
    PORT
      LAYER M4 ;
        RECT  21.516 38.256 21.6 38.28 ;
    END
  END o[127]
  PIN o[128]
    DIRECTION OUTPUT ;
    USE SIGNAL ;
    PORT
      LAYER M4 ;
        RECT  21.516 22.992 21.6 23.016 ;
    END
  END o[128]
  PIN o[129]
    DIRECTION OUTPUT ;
    USE SIGNAL ;
    PORT
      LAYER M4 ;
        RECT  21.516 23.088 21.6 23.112 ;
    END
  END o[129]
  PIN o[12]
    DIRECTION OUTPUT ;
    USE SIGNAL ;
    PORT
      LAYER M4 ;
        RECT  21.516 21.072 21.6 21.096 ;
    END
  END o[12]
  PIN o[130]
    DIRECTION OUTPUT ;
    USE SIGNAL ;
    PORT
      LAYER M4 ;
        RECT  21.516 23.184 21.6 23.208 ;
    END
  END o[130]
  PIN o[131]
    DIRECTION OUTPUT ;
    USE SIGNAL ;
    PORT
      LAYER M4 ;
        RECT  21.516 23.28 21.6 23.304 ;
    END
  END o[131]
  PIN o[132]
    DIRECTION OUTPUT ;
    USE SIGNAL ;
    PORT
      LAYER M4 ;
        RECT  21.516 23.376 21.6 23.4 ;
    END
  END o[132]
  PIN o[133]
    DIRECTION OUTPUT ;
    USE SIGNAL ;
    PORT
      LAYER M4 ;
        RECT  21.516 23.472 21.6 23.496 ;
    END
  END o[133]
  PIN o[134]
    DIRECTION OUTPUT ;
    USE SIGNAL ;
    PORT
      LAYER M4 ;
        RECT  21.516 23.568 21.6 23.592 ;
    END
  END o[134]
  PIN o[135]
    DIRECTION OUTPUT ;
    USE SIGNAL ;
    PORT
      LAYER M4 ;
        RECT  21.516 23.664 21.6 23.688 ;
    END
  END o[135]
  PIN o[136]
    DIRECTION OUTPUT ;
    USE SIGNAL ;
    PORT
      LAYER M4 ;
        RECT  21.516 23.76 21.6 23.784 ;
    END
  END o[136]
  PIN o[137]
    DIRECTION OUTPUT ;
    USE SIGNAL ;
    PORT
      LAYER M4 ;
        RECT  21.516 23.856 21.6 23.88 ;
    END
  END o[137]
  PIN o[138]
    DIRECTION OUTPUT ;
    USE SIGNAL ;
    PORT
      LAYER M4 ;
        RECT  21.516 23.952 21.6 23.976 ;
    END
  END o[138]
  PIN o[139]
    DIRECTION OUTPUT ;
    USE SIGNAL ;
    PORT
      LAYER M4 ;
        RECT  21.516 24.048 21.6 24.072 ;
    END
  END o[139]
  PIN o[13]
    DIRECTION OUTPUT ;
    USE SIGNAL ;
    PORT
      LAYER M4 ;
        RECT  21.516 21.168 21.6 21.192 ;
    END
  END o[13]
  PIN o[140]
    DIRECTION OUTPUT ;
    USE SIGNAL ;
    PORT
      LAYER M4 ;
        RECT  21.516 24.144 21.6 24.168 ;
    END
  END o[140]
  PIN o[141]
    DIRECTION OUTPUT ;
    USE SIGNAL ;
    PORT
      LAYER M4 ;
        RECT  21.516 24.24 21.6 24.264 ;
    END
  END o[141]
  PIN o[142]
    DIRECTION OUTPUT ;
    USE SIGNAL ;
    PORT
      LAYER M4 ;
        RECT  21.516 24.336 21.6 24.36 ;
    END
  END o[142]
  PIN o[143]
    DIRECTION OUTPUT ;
    USE SIGNAL ;
    PORT
      LAYER M4 ;
        RECT  21.516 24.432 21.6 24.456 ;
    END
  END o[143]
  PIN o[144]
    DIRECTION OUTPUT ;
    USE SIGNAL ;
    PORT
      LAYER M4 ;
        RECT  21.516 24.528 21.6 24.552 ;
    END
  END o[144]
  PIN o[145]
    DIRECTION OUTPUT ;
    USE SIGNAL ;
    PORT
      LAYER M4 ;
        RECT  21.516 24.624 21.6 24.648 ;
    END
  END o[145]
  PIN o[146]
    DIRECTION OUTPUT ;
    USE SIGNAL ;
    PORT
      LAYER M4 ;
        RECT  21.516 24.72 21.6 24.744 ;
    END
  END o[146]
  PIN o[147]
    DIRECTION OUTPUT ;
    USE SIGNAL ;
    PORT
      LAYER M4 ;
        RECT  21.516 24.816 21.6 24.84 ;
    END
  END o[147]
  PIN o[148]
    DIRECTION OUTPUT ;
    USE SIGNAL ;
    PORT
      LAYER M4 ;
        RECT  21.516 24.912 21.6 24.936 ;
    END
  END o[148]
  PIN o[149]
    DIRECTION OUTPUT ;
    USE SIGNAL ;
    PORT
      LAYER M4 ;
        RECT  21.516 25.008 21.6 25.032 ;
    END
  END o[149]
  PIN o[14]
    DIRECTION OUTPUT ;
    USE SIGNAL ;
    PORT
      LAYER M4 ;
        RECT  21.516 21.264 21.6 21.288 ;
    END
  END o[14]
  PIN o[150]
    DIRECTION OUTPUT ;
    USE SIGNAL ;
    PORT
      LAYER M4 ;
        RECT  21.516 25.104 21.6 25.128 ;
    END
  END o[150]
  PIN o[151]
    DIRECTION OUTPUT ;
    USE SIGNAL ;
    PORT
      LAYER M4 ;
        RECT  21.516 25.2 21.6 25.224 ;
    END
  END o[151]
  PIN o[152]
    DIRECTION OUTPUT ;
    USE SIGNAL ;
    PORT
      LAYER M4 ;
        RECT  21.516 25.296 21.6 25.32 ;
    END
  END o[152]
  PIN o[153]
    DIRECTION OUTPUT ;
    USE SIGNAL ;
    PORT
      LAYER M4 ;
        RECT  21.516 25.392 21.6 25.416 ;
    END
  END o[153]
  PIN o[154]
    DIRECTION OUTPUT ;
    USE SIGNAL ;
    PORT
      LAYER M4 ;
        RECT  21.516 25.488 21.6 25.512 ;
    END
  END o[154]
  PIN o[155]
    DIRECTION OUTPUT ;
    USE SIGNAL ;
    PORT
      LAYER M4 ;
        RECT  21.516 25.584 21.6 25.608 ;
    END
  END o[155]
  PIN o[156]
    DIRECTION OUTPUT ;
    USE SIGNAL ;
    PORT
      LAYER M4 ;
        RECT  21.516 25.68 21.6 25.704 ;
    END
  END o[156]
  PIN o[157]
    DIRECTION OUTPUT ;
    USE SIGNAL ;
    PORT
      LAYER M4 ;
        RECT  21.516 25.776 21.6 25.8 ;
    END
  END o[157]
  PIN o[158]
    DIRECTION OUTPUT ;
    USE SIGNAL ;
    PORT
      LAYER M4 ;
        RECT  21.516 25.872 21.6 25.896 ;
    END
  END o[158]
  PIN o[159]
    DIRECTION OUTPUT ;
    USE SIGNAL ;
    PORT
      LAYER M4 ;
        RECT  21.516 25.968 21.6 25.992 ;
    END
  END o[159]
  PIN o[15]
    DIRECTION OUTPUT ;
    USE SIGNAL ;
    PORT
      LAYER M4 ;
        RECT  21.516 21.36 21.6 21.384 ;
    END
  END o[15]
  PIN o[160]
    DIRECTION OUTPUT ;
    USE SIGNAL ;
    PORT
      LAYER M4 ;
        RECT  21.516 32.208 21.6 32.232 ;
    END
  END o[160]
  PIN o[161]
    DIRECTION OUTPUT ;
    USE SIGNAL ;
    PORT
      LAYER M4 ;
        RECT  21.516 32.304 21.6 32.328 ;
    END
  END o[161]
  PIN o[162]
    DIRECTION OUTPUT ;
    USE SIGNAL ;
    PORT
      LAYER M4 ;
        RECT  21.516 32.4 21.6 32.424 ;
    END
  END o[162]
  PIN o[163]
    DIRECTION OUTPUT ;
    USE SIGNAL ;
    PORT
      LAYER M4 ;
        RECT  21.516 32.496 21.6 32.52 ;
    END
  END o[163]
  PIN o[164]
    DIRECTION OUTPUT ;
    USE SIGNAL ;
    PORT
      LAYER M4 ;
        RECT  21.516 32.592 21.6 32.616 ;
    END
  END o[164]
  PIN o[165]
    DIRECTION OUTPUT ;
    USE SIGNAL ;
    PORT
      LAYER M4 ;
        RECT  21.516 32.688 21.6 32.712 ;
    END
  END o[165]
  PIN o[166]
    DIRECTION OUTPUT ;
    USE SIGNAL ;
    PORT
      LAYER M4 ;
        RECT  21.516 32.784 21.6 32.808 ;
    END
  END o[166]
  PIN o[167]
    DIRECTION OUTPUT ;
    USE SIGNAL ;
    PORT
      LAYER M4 ;
        RECT  21.516 32.88 21.6 32.904 ;
    END
  END o[167]
  PIN o[168]
    DIRECTION OUTPUT ;
    USE SIGNAL ;
    PORT
      LAYER M4 ;
        RECT  21.516 32.976 21.6 33 ;
    END
  END o[168]
  PIN o[169]
    DIRECTION OUTPUT ;
    USE SIGNAL ;
    PORT
      LAYER M4 ;
        RECT  21.516 33.072 21.6 33.096 ;
    END
  END o[169]
  PIN o[16]
    DIRECTION OUTPUT ;
    USE SIGNAL ;
    PORT
      LAYER M4 ;
        RECT  21.516 21.456 21.6 21.48 ;
    END
  END o[16]
  PIN o[170]
    DIRECTION OUTPUT ;
    USE SIGNAL ;
    PORT
      LAYER M4 ;
        RECT  21.516 33.168 21.6 33.192 ;
    END
  END o[170]
  PIN o[171]
    DIRECTION OUTPUT ;
    USE SIGNAL ;
    PORT
      LAYER M4 ;
        RECT  21.516 33.264 21.6 33.288 ;
    END
  END o[171]
  PIN o[172]
    DIRECTION OUTPUT ;
    USE SIGNAL ;
    PORT
      LAYER M4 ;
        RECT  21.516 33.36 21.6 33.384 ;
    END
  END o[172]
  PIN o[173]
    DIRECTION OUTPUT ;
    USE SIGNAL ;
    PORT
      LAYER M4 ;
        RECT  21.516 33.456 21.6 33.48 ;
    END
  END o[173]
  PIN o[174]
    DIRECTION OUTPUT ;
    USE SIGNAL ;
    PORT
      LAYER M4 ;
        RECT  21.516 33.552 21.6 33.576 ;
    END
  END o[174]
  PIN o[175]
    DIRECTION OUTPUT ;
    USE SIGNAL ;
    PORT
      LAYER M4 ;
        RECT  21.516 33.648 21.6 33.672 ;
    END
  END o[175]
  PIN o[176]
    DIRECTION OUTPUT ;
    USE SIGNAL ;
    PORT
      LAYER M4 ;
        RECT  21.516 33.744 21.6 33.768 ;
    END
  END o[176]
  PIN o[177]
    DIRECTION OUTPUT ;
    USE SIGNAL ;
    PORT
      LAYER M4 ;
        RECT  21.516 33.84 21.6 33.864 ;
    END
  END o[177]
  PIN o[178]
    DIRECTION OUTPUT ;
    USE SIGNAL ;
    PORT
      LAYER M4 ;
        RECT  21.516 33.936 21.6 33.96 ;
    END
  END o[178]
  PIN o[179]
    DIRECTION OUTPUT ;
    USE SIGNAL ;
    PORT
      LAYER M4 ;
        RECT  21.516 34.032 21.6 34.056 ;
    END
  END o[179]
  PIN o[17]
    DIRECTION OUTPUT ;
    USE SIGNAL ;
    PORT
      LAYER M4 ;
        RECT  21.516 21.552 21.6 21.576 ;
    END
  END o[17]
  PIN o[180]
    DIRECTION OUTPUT ;
    USE SIGNAL ;
    PORT
      LAYER M4 ;
        RECT  21.516 34.128 21.6 34.152 ;
    END
  END o[180]
  PIN o[181]
    DIRECTION OUTPUT ;
    USE SIGNAL ;
    PORT
      LAYER M4 ;
        RECT  21.516 34.224 21.6 34.248 ;
    END
  END o[181]
  PIN o[182]
    DIRECTION OUTPUT ;
    USE SIGNAL ;
    PORT
      LAYER M4 ;
        RECT  21.516 34.32 21.6 34.344 ;
    END
  END o[182]
  PIN o[183]
    DIRECTION OUTPUT ;
    USE SIGNAL ;
    PORT
      LAYER M4 ;
        RECT  21.516 34.416 21.6 34.44 ;
    END
  END o[183]
  PIN o[184]
    DIRECTION OUTPUT ;
    USE SIGNAL ;
    PORT
      LAYER M4 ;
        RECT  21.516 34.512 21.6 34.536 ;
    END
  END o[184]
  PIN o[185]
    DIRECTION OUTPUT ;
    USE SIGNAL ;
    PORT
      LAYER M4 ;
        RECT  21.516 34.608 21.6 34.632 ;
    END
  END o[185]
  PIN o[186]
    DIRECTION OUTPUT ;
    USE SIGNAL ;
    PORT
      LAYER M4 ;
        RECT  21.516 34.704 21.6 34.728 ;
    END
  END o[186]
  PIN o[187]
    DIRECTION OUTPUT ;
    USE SIGNAL ;
    PORT
      LAYER M4 ;
        RECT  21.516 34.8 21.6 34.824 ;
    END
  END o[187]
  PIN o[188]
    DIRECTION OUTPUT ;
    USE SIGNAL ;
    PORT
      LAYER M4 ;
        RECT  21.516 34.896 21.6 34.92 ;
    END
  END o[188]
  PIN o[189]
    DIRECTION OUTPUT ;
    USE SIGNAL ;
    PORT
      LAYER M4 ;
        RECT  21.516 34.992 21.6 35.016 ;
    END
  END o[189]
  PIN o[18]
    DIRECTION OUTPUT ;
    USE SIGNAL ;
    PORT
      LAYER M4 ;
        RECT  21.516 21.648 21.6 21.672 ;
    END
  END o[18]
  PIN o[190]
    DIRECTION OUTPUT ;
    USE SIGNAL ;
    PORT
      LAYER M4 ;
        RECT  21.516 35.088 21.6 35.112 ;
    END
  END o[190]
  PIN o[191]
    DIRECTION OUTPUT ;
    USE SIGNAL ;
    PORT
      LAYER M4 ;
        RECT  21.516 35.184 21.6 35.208 ;
    END
  END o[191]
  PIN o[192]
    DIRECTION OUTPUT ;
    USE SIGNAL ;
    PORT
      LAYER M4 ;
        RECT  21.516 3.792 21.6 3.816 ;
    END
  END o[192]
  PIN o[193]
    DIRECTION OUTPUT ;
    USE SIGNAL ;
    PORT
      LAYER M4 ;
        RECT  21.516 3.888 21.6 3.912 ;
    END
  END o[193]
  PIN o[194]
    DIRECTION OUTPUT ;
    USE SIGNAL ;
    PORT
      LAYER M4 ;
        RECT  21.516 3.984 21.6 4.008 ;
    END
  END o[194]
  PIN o[195]
    DIRECTION OUTPUT ;
    USE SIGNAL ;
    PORT
      LAYER M4 ;
        RECT  21.516 4.08 21.6 4.104 ;
    END
  END o[195]
  PIN o[196]
    DIRECTION OUTPUT ;
    USE SIGNAL ;
    PORT
      LAYER M4 ;
        RECT  21.516 4.176 21.6 4.2 ;
    END
  END o[196]
  PIN o[197]
    DIRECTION OUTPUT ;
    USE SIGNAL ;
    PORT
      LAYER M4 ;
        RECT  21.516 4.272 21.6 4.296 ;
    END
  END o[197]
  PIN o[198]
    DIRECTION OUTPUT ;
    USE SIGNAL ;
    PORT
      LAYER M4 ;
        RECT  21.516 4.368 21.6 4.392 ;
    END
  END o[198]
  PIN o[199]
    DIRECTION OUTPUT ;
    USE SIGNAL ;
    PORT
      LAYER M4 ;
        RECT  21.516 4.464 21.6 4.488 ;
    END
  END o[199]
  PIN o[19]
    DIRECTION OUTPUT ;
    USE SIGNAL ;
    PORT
      LAYER M4 ;
        RECT  21.516 21.744 21.6 21.768 ;
    END
  END o[19]
  PIN o[1]
    DIRECTION OUTPUT ;
    USE SIGNAL ;
    PORT
      LAYER M4 ;
        RECT  21.516 20.016 21.6 20.04 ;
    END
  END o[1]
  PIN o[200]
    DIRECTION OUTPUT ;
    USE SIGNAL ;
    PORT
      LAYER M4 ;
        RECT  21.516 4.56 21.6 4.584 ;
    END
  END o[200]
  PIN o[201]
    DIRECTION OUTPUT ;
    USE SIGNAL ;
    PORT
      LAYER M4 ;
        RECT  21.516 4.656 21.6 4.68 ;
    END
  END o[201]
  PIN o[202]
    DIRECTION OUTPUT ;
    USE SIGNAL ;
    PORT
      LAYER M4 ;
        RECT  21.516 4.752 21.6 4.776 ;
    END
  END o[202]
  PIN o[203]
    DIRECTION OUTPUT ;
    USE SIGNAL ;
    PORT
      LAYER M4 ;
        RECT  21.516 4.848 21.6 4.872 ;
    END
  END o[203]
  PIN o[204]
    DIRECTION OUTPUT ;
    USE SIGNAL ;
    PORT
      LAYER M4 ;
        RECT  21.516 4.944 21.6 4.968 ;
    END
  END o[204]
  PIN o[205]
    DIRECTION OUTPUT ;
    USE SIGNAL ;
    PORT
      LAYER M4 ;
        RECT  21.516 5.04 21.6 5.064 ;
    END
  END o[205]
  PIN o[206]
    DIRECTION OUTPUT ;
    USE SIGNAL ;
    PORT
      LAYER M4 ;
        RECT  21.516 5.136 21.6 5.16 ;
    END
  END o[206]
  PIN o[207]
    DIRECTION OUTPUT ;
    USE SIGNAL ;
    PORT
      LAYER M4 ;
        RECT  21.516 5.232 21.6 5.256 ;
    END
  END o[207]
  PIN o[208]
    DIRECTION OUTPUT ;
    USE SIGNAL ;
    PORT
      LAYER M4 ;
        RECT  21.516 5.328 21.6 5.352 ;
    END
  END o[208]
  PIN o[209]
    DIRECTION OUTPUT ;
    USE SIGNAL ;
    PORT
      LAYER M4 ;
        RECT  21.516 5.424 21.6 5.448 ;
    END
  END o[209]
  PIN o[20]
    DIRECTION OUTPUT ;
    USE SIGNAL ;
    PORT
      LAYER M4 ;
        RECT  21.516 21.84 21.6 21.864 ;
    END
  END o[20]
  PIN o[210]
    DIRECTION OUTPUT ;
    USE SIGNAL ;
    PORT
      LAYER M4 ;
        RECT  21.516 5.52 21.6 5.544 ;
    END
  END o[210]
  PIN o[211]
    DIRECTION OUTPUT ;
    USE SIGNAL ;
    PORT
      LAYER M4 ;
        RECT  21.516 5.616 21.6 5.64 ;
    END
  END o[211]
  PIN o[212]
    DIRECTION OUTPUT ;
    USE SIGNAL ;
    PORT
      LAYER M4 ;
        RECT  21.516 5.712 21.6 5.736 ;
    END
  END o[212]
  PIN o[213]
    DIRECTION OUTPUT ;
    USE SIGNAL ;
    PORT
      LAYER M4 ;
        RECT  21.516 5.808 21.6 5.832 ;
    END
  END o[213]
  PIN o[214]
    DIRECTION OUTPUT ;
    USE SIGNAL ;
    PORT
      LAYER M4 ;
        RECT  21.516 5.904 21.6 5.928 ;
    END
  END o[214]
  PIN o[215]
    DIRECTION OUTPUT ;
    USE SIGNAL ;
    PORT
      LAYER M4 ;
        RECT  21.516 6 21.6 6.024 ;
    END
  END o[215]
  PIN o[216]
    DIRECTION OUTPUT ;
    USE SIGNAL ;
    PORT
      LAYER M4 ;
        RECT  21.516 6.096 21.6 6.12 ;
    END
  END o[216]
  PIN o[217]
    DIRECTION OUTPUT ;
    USE SIGNAL ;
    PORT
      LAYER M4 ;
        RECT  21.516 6.192 21.6 6.216 ;
    END
  END o[217]
  PIN o[218]
    DIRECTION OUTPUT ;
    USE SIGNAL ;
    PORT
      LAYER M4 ;
        RECT  21.516 6.288 21.6 6.312 ;
    END
  END o[218]
  PIN o[219]
    DIRECTION OUTPUT ;
    USE SIGNAL ;
    PORT
      LAYER M4 ;
        RECT  21.516 6.384 21.6 6.408 ;
    END
  END o[219]
  PIN o[21]
    DIRECTION OUTPUT ;
    USE SIGNAL ;
    PORT
      LAYER M4 ;
        RECT  21.516 21.936 21.6 21.96 ;
    END
  END o[21]
  PIN o[220]
    DIRECTION OUTPUT ;
    USE SIGNAL ;
    PORT
      LAYER M4 ;
        RECT  21.516 6.48 21.6 6.504 ;
    END
  END o[220]
  PIN o[221]
    DIRECTION OUTPUT ;
    USE SIGNAL ;
    PORT
      LAYER M4 ;
        RECT  21.516 6.576 21.6 6.6 ;
    END
  END o[221]
  PIN o[222]
    DIRECTION OUTPUT ;
    USE SIGNAL ;
    PORT
      LAYER M4 ;
        RECT  21.516 6.672 21.6 6.696 ;
    END
  END o[222]
  PIN o[223]
    DIRECTION OUTPUT ;
    USE SIGNAL ;
    PORT
      LAYER M4 ;
        RECT  21.516 6.768 21.6 6.792 ;
    END
  END o[223]
  PIN o[224]
    DIRECTION OUTPUT ;
    USE SIGNAL ;
    PORT
      LAYER M4 ;
        RECT  21.516 6.864 21.6 6.888 ;
    END
  END o[224]
  PIN o[225]
    DIRECTION OUTPUT ;
    USE SIGNAL ;
    PORT
      LAYER M4 ;
        RECT  21.516 6.96 21.6 6.984 ;
    END
  END o[225]
  PIN o[226]
    DIRECTION OUTPUT ;
    USE SIGNAL ;
    PORT
      LAYER M4 ;
        RECT  21.516 7.056 21.6 7.08 ;
    END
  END o[226]
  PIN o[227]
    DIRECTION OUTPUT ;
    USE SIGNAL ;
    PORT
      LAYER M4 ;
        RECT  21.516 7.152 21.6 7.176 ;
    END
  END o[227]
  PIN o[228]
    DIRECTION OUTPUT ;
    USE SIGNAL ;
    PORT
      LAYER M4 ;
        RECT  21.516 7.248 21.6 7.272 ;
    END
  END o[228]
  PIN o[229]
    DIRECTION OUTPUT ;
    USE SIGNAL ;
    PORT
      LAYER M4 ;
        RECT  21.516 7.344 21.6 7.368 ;
    END
  END o[229]
  PIN o[22]
    DIRECTION OUTPUT ;
    USE SIGNAL ;
    PORT
      LAYER M4 ;
        RECT  21.516 22.032 21.6 22.056 ;
    END
  END o[22]
  PIN o[230]
    DIRECTION OUTPUT ;
    USE SIGNAL ;
    PORT
      LAYER M4 ;
        RECT  21.516 7.44 21.6 7.464 ;
    END
  END o[230]
  PIN o[231]
    DIRECTION OUTPUT ;
    USE SIGNAL ;
    PORT
      LAYER M4 ;
        RECT  21.516 7.536 21.6 7.56 ;
    END
  END o[231]
  PIN o[232]
    DIRECTION OUTPUT ;
    USE SIGNAL ;
    PORT
      LAYER M4 ;
        RECT  21.516 7.632 21.6 7.656 ;
    END
  END o[232]
  PIN o[233]
    DIRECTION OUTPUT ;
    USE SIGNAL ;
    PORT
      LAYER M4 ;
        RECT  21.516 7.728 21.6 7.752 ;
    END
  END o[233]
  PIN o[234]
    DIRECTION OUTPUT ;
    USE SIGNAL ;
    PORT
      LAYER M4 ;
        RECT  21.516 7.824 21.6 7.848 ;
    END
  END o[234]
  PIN o[235]
    DIRECTION OUTPUT ;
    USE SIGNAL ;
    PORT
      LAYER M4 ;
        RECT  21.516 7.92 21.6 7.944 ;
    END
  END o[235]
  PIN o[236]
    DIRECTION OUTPUT ;
    USE SIGNAL ;
    PORT
      LAYER M4 ;
        RECT  21.516 8.016 21.6 8.04 ;
    END
  END o[236]
  PIN o[237]
    DIRECTION OUTPUT ;
    USE SIGNAL ;
    PORT
      LAYER M4 ;
        RECT  21.516 8.112 21.6 8.136 ;
    END
  END o[237]
  PIN o[238]
    DIRECTION OUTPUT ;
    USE SIGNAL ;
    PORT
      LAYER M4 ;
        RECT  21.516 8.208 21.6 8.232 ;
    END
  END o[238]
  PIN o[239]
    DIRECTION OUTPUT ;
    USE SIGNAL ;
    PORT
      LAYER M4 ;
        RECT  21.516 8.304 21.6 8.328 ;
    END
  END o[239]
  PIN o[23]
    DIRECTION OUTPUT ;
    USE SIGNAL ;
    PORT
      LAYER M4 ;
        RECT  21.516 22.128 21.6 22.152 ;
    END
  END o[23]
  PIN o[240]
    DIRECTION OUTPUT ;
    USE SIGNAL ;
    PORT
      LAYER M4 ;
        RECT  21.516 8.4 21.6 8.424 ;
    END
  END o[240]
  PIN o[241]
    DIRECTION OUTPUT ;
    USE SIGNAL ;
    PORT
      LAYER M4 ;
        RECT  21.516 8.496 21.6 8.52 ;
    END
  END o[241]
  PIN o[242]
    DIRECTION OUTPUT ;
    USE SIGNAL ;
    PORT
      LAYER M4 ;
        RECT  21.516 8.592 21.6 8.616 ;
    END
  END o[242]
  PIN o[243]
    DIRECTION OUTPUT ;
    USE SIGNAL ;
    PORT
      LAYER M4 ;
        RECT  21.516 8.688 21.6 8.712 ;
    END
  END o[243]
  PIN o[244]
    DIRECTION OUTPUT ;
    USE SIGNAL ;
    PORT
      LAYER M4 ;
        RECT  21.516 8.784 21.6 8.808 ;
    END
  END o[244]
  PIN o[245]
    DIRECTION OUTPUT ;
    USE SIGNAL ;
    PORT
      LAYER M4 ;
        RECT  21.516 8.88 21.6 8.904 ;
    END
  END o[245]
  PIN o[246]
    DIRECTION OUTPUT ;
    USE SIGNAL ;
    PORT
      LAYER M4 ;
        RECT  21.516 8.976 21.6 9 ;
    END
  END o[246]
  PIN o[247]
    DIRECTION OUTPUT ;
    USE SIGNAL ;
    PORT
      LAYER M4 ;
        RECT  21.516 9.072 21.6 9.096 ;
    END
  END o[247]
  PIN o[248]
    DIRECTION OUTPUT ;
    USE SIGNAL ;
    PORT
      LAYER M4 ;
        RECT  21.516 9.168 21.6 9.192 ;
    END
  END o[248]
  PIN o[249]
    DIRECTION OUTPUT ;
    USE SIGNAL ;
    PORT
      LAYER M4 ;
        RECT  21.516 9.264 21.6 9.288 ;
    END
  END o[249]
  PIN o[24]
    DIRECTION OUTPUT ;
    USE SIGNAL ;
    PORT
      LAYER M4 ;
        RECT  21.516 22.224 21.6 22.248 ;
    END
  END o[24]
  PIN o[250]
    DIRECTION OUTPUT ;
    USE SIGNAL ;
    PORT
      LAYER M4 ;
        RECT  21.516 9.36 21.6 9.384 ;
    END
  END o[250]
  PIN o[251]
    DIRECTION OUTPUT ;
    USE SIGNAL ;
    PORT
      LAYER M4 ;
        RECT  21.516 9.456 21.6 9.48 ;
    END
  END o[251]
  PIN o[252]
    DIRECTION OUTPUT ;
    USE SIGNAL ;
    PORT
      LAYER M4 ;
        RECT  21.516 9.552 21.6 9.576 ;
    END
  END o[252]
  PIN o[253]
    DIRECTION OUTPUT ;
    USE SIGNAL ;
    PORT
      LAYER M4 ;
        RECT  21.516 9.648 21.6 9.672 ;
    END
  END o[253]
  PIN o[254]
    DIRECTION OUTPUT ;
    USE SIGNAL ;
    PORT
      LAYER M4 ;
        RECT  21.516 9.744 21.6 9.768 ;
    END
  END o[254]
  PIN o[255]
    DIRECTION OUTPUT ;
    USE SIGNAL ;
    PORT
      LAYER M4 ;
        RECT  21.516 9.84 21.6 9.864 ;
    END
  END o[255]
  PIN o[256]
    DIRECTION OUTPUT ;
    USE SIGNAL ;
    PORT
      LAYER M4 ;
        RECT  21.516 39.12 21.6 39.144 ;
    END
  END o[256]
  PIN o[257]
    DIRECTION OUTPUT ;
    USE SIGNAL ;
    PORT
      LAYER M4 ;
        RECT  21.516 39.216 21.6 39.24 ;
    END
  END o[257]
  PIN o[258]
    DIRECTION OUTPUT ;
    USE SIGNAL ;
    PORT
      LAYER M4 ;
        RECT  21.516 39.312 21.6 39.336 ;
    END
  END o[258]
  PIN o[259]
    DIRECTION OUTPUT ;
    USE SIGNAL ;
    PORT
      LAYER M4 ;
        RECT  21.516 39.408 21.6 39.432 ;
    END
  END o[259]
  PIN o[25]
    DIRECTION OUTPUT ;
    USE SIGNAL ;
    PORT
      LAYER M4 ;
        RECT  21.516 22.32 21.6 22.344 ;
    END
  END o[25]
  PIN o[260]
    DIRECTION OUTPUT ;
    USE SIGNAL ;
    PORT
      LAYER M4 ;
        RECT  21.516 39.504 21.6 39.528 ;
    END
  END o[260]
  PIN o[261]
    DIRECTION OUTPUT ;
    USE SIGNAL ;
    PORT
      LAYER M4 ;
        RECT  21.516 39.6 21.6 39.624 ;
    END
  END o[261]
  PIN o[262]
    DIRECTION OUTPUT ;
    USE SIGNAL ;
    PORT
      LAYER M4 ;
        RECT  21.516 39.696 21.6 39.72 ;
    END
  END o[262]
  PIN o[263]
    DIRECTION OUTPUT ;
    USE SIGNAL ;
    PORT
      LAYER M4 ;
        RECT  21.516 39.792 21.6 39.816 ;
    END
  END o[263]
  PIN o[264]
    DIRECTION OUTPUT ;
    USE SIGNAL ;
    PORT
      LAYER M4 ;
        RECT  21.516 39.888 21.6 39.912 ;
    END
  END o[264]
  PIN o[265]
    DIRECTION OUTPUT ;
    USE SIGNAL ;
    PORT
      LAYER M4 ;
        RECT  21.516 39.984 21.6 40.008 ;
    END
  END o[265]
  PIN o[266]
    DIRECTION OUTPUT ;
    USE SIGNAL ;
    PORT
      LAYER M4 ;
        RECT  21.516 40.08 21.6 40.104 ;
    END
  END o[266]
  PIN o[267]
    DIRECTION OUTPUT ;
    USE SIGNAL ;
    PORT
      LAYER M4 ;
        RECT  21.516 40.176 21.6 40.2 ;
    END
  END o[267]
  PIN o[268]
    DIRECTION OUTPUT ;
    USE SIGNAL ;
    PORT
      LAYER M4 ;
        RECT  21.516 40.272 21.6 40.296 ;
    END
  END o[268]
  PIN o[269]
    DIRECTION OUTPUT ;
    USE SIGNAL ;
    PORT
      LAYER M4 ;
        RECT  21.516 40.368 21.6 40.392 ;
    END
  END o[269]
  PIN o[26]
    DIRECTION OUTPUT ;
    USE SIGNAL ;
    PORT
      LAYER M4 ;
        RECT  21.516 22.416 21.6 22.44 ;
    END
  END o[26]
  PIN o[270]
    DIRECTION OUTPUT ;
    USE SIGNAL ;
    PORT
      LAYER M4 ;
        RECT  21.516 40.464 21.6 40.488 ;
    END
  END o[270]
  PIN o[271]
    DIRECTION OUTPUT ;
    USE SIGNAL ;
    PORT
      LAYER M4 ;
        RECT  21.516 40.56 21.6 40.584 ;
    END
  END o[271]
  PIN o[272]
    DIRECTION OUTPUT ;
    USE SIGNAL ;
    PORT
      LAYER M4 ;
        RECT  21.516 40.656 21.6 40.68 ;
    END
  END o[272]
  PIN o[273]
    DIRECTION OUTPUT ;
    USE SIGNAL ;
    PORT
      LAYER M4 ;
        RECT  21.516 40.752 21.6 40.776 ;
    END
  END o[273]
  PIN o[274]
    DIRECTION OUTPUT ;
    USE SIGNAL ;
    PORT
      LAYER M4 ;
        RECT  21.516 40.848 21.6 40.872 ;
    END
  END o[274]
  PIN o[275]
    DIRECTION OUTPUT ;
    USE SIGNAL ;
    PORT
      LAYER M4 ;
        RECT  21.516 40.944 21.6 40.968 ;
    END
  END o[275]
  PIN o[276]
    DIRECTION OUTPUT ;
    USE SIGNAL ;
    PORT
      LAYER M4 ;
        RECT  21.516 41.04 21.6 41.064 ;
    END
  END o[276]
  PIN o[277]
    DIRECTION OUTPUT ;
    USE SIGNAL ;
    PORT
      LAYER M4 ;
        RECT  21.516 41.136 21.6 41.16 ;
    END
  END o[277]
  PIN o[278]
    DIRECTION OUTPUT ;
    USE SIGNAL ;
    PORT
      LAYER M4 ;
        RECT  21.516 41.232 21.6 41.256 ;
    END
  END o[278]
  PIN o[279]
    DIRECTION OUTPUT ;
    USE SIGNAL ;
    PORT
      LAYER M4 ;
        RECT  21.516 41.328 21.6 41.352 ;
    END
  END o[279]
  PIN o[27]
    DIRECTION OUTPUT ;
    USE SIGNAL ;
    PORT
      LAYER M4 ;
        RECT  21.516 22.512 21.6 22.536 ;
    END
  END o[27]
  PIN o[280]
    DIRECTION OUTPUT ;
    USE SIGNAL ;
    PORT
      LAYER M4 ;
        RECT  21.516 41.424 21.6 41.448 ;
    END
  END o[280]
  PIN o[281]
    DIRECTION OUTPUT ;
    USE SIGNAL ;
    PORT
      LAYER M4 ;
        RECT  21.516 41.52 21.6 41.544 ;
    END
  END o[281]
  PIN o[282]
    DIRECTION OUTPUT ;
    USE SIGNAL ;
    PORT
      LAYER M4 ;
        RECT  21.516 41.616 21.6 41.64 ;
    END
  END o[282]
  PIN o[283]
    DIRECTION OUTPUT ;
    USE SIGNAL ;
    PORT
      LAYER M4 ;
        RECT  21.516 41.712 21.6 41.736 ;
    END
  END o[283]
  PIN o[284]
    DIRECTION OUTPUT ;
    USE SIGNAL ;
    PORT
      LAYER M4 ;
        RECT  21.516 41.808 21.6 41.832 ;
    END
  END o[284]
  PIN o[285]
    DIRECTION OUTPUT ;
    USE SIGNAL ;
    PORT
      LAYER M4 ;
        RECT  21.516 41.904 21.6 41.928 ;
    END
  END o[285]
  PIN o[286]
    DIRECTION OUTPUT ;
    USE SIGNAL ;
    PORT
      LAYER M4 ;
        RECT  21.516 42 21.6 42.024 ;
    END
  END o[286]
  PIN o[287]
    DIRECTION OUTPUT ;
    USE SIGNAL ;
    PORT
      LAYER M4 ;
        RECT  21.516 42.096 21.6 42.12 ;
    END
  END o[287]
  PIN o[288]
    DIRECTION OUTPUT ;
    USE SIGNAL ;
    PORT
      LAYER M4 ;
        RECT  21.516 42.192 21.6 42.216 ;
    END
  END o[288]
  PIN o[289]
    DIRECTION OUTPUT ;
    USE SIGNAL ;
    PORT
      LAYER M4 ;
        RECT  21.516 42.288 21.6 42.312 ;
    END
  END o[289]
  PIN o[28]
    DIRECTION OUTPUT ;
    USE SIGNAL ;
    PORT
      LAYER M4 ;
        RECT  21.516 22.608 21.6 22.632 ;
    END
  END o[28]
  PIN o[290]
    DIRECTION OUTPUT ;
    USE SIGNAL ;
    PORT
      LAYER M4 ;
        RECT  21.516 42.384 21.6 42.408 ;
    END
  END o[290]
  PIN o[291]
    DIRECTION OUTPUT ;
    USE SIGNAL ;
    PORT
      LAYER M4 ;
        RECT  21.516 42.48 21.6 42.504 ;
    END
  END o[291]
  PIN o[292]
    DIRECTION OUTPUT ;
    USE SIGNAL ;
    PORT
      LAYER M4 ;
        RECT  21.516 42.576 21.6 42.6 ;
    END
  END o[292]
  PIN o[293]
    DIRECTION OUTPUT ;
    USE SIGNAL ;
    PORT
      LAYER M4 ;
        RECT  21.516 42.672 21.6 42.696 ;
    END
  END o[293]
  PIN o[294]
    DIRECTION OUTPUT ;
    USE SIGNAL ;
    PORT
      LAYER M4 ;
        RECT  21.516 42.768 21.6 42.792 ;
    END
  END o[294]
  PIN o[295]
    DIRECTION OUTPUT ;
    USE SIGNAL ;
    PORT
      LAYER M4 ;
        RECT  21.516 42.864 21.6 42.888 ;
    END
  END o[295]
  PIN o[296]
    DIRECTION OUTPUT ;
    USE SIGNAL ;
    PORT
      LAYER M4 ;
        RECT  21.516 42.96 21.6 42.984 ;
    END
  END o[296]
  PIN o[297]
    DIRECTION OUTPUT ;
    USE SIGNAL ;
    PORT
      LAYER M4 ;
        RECT  21.516 43.056 21.6 43.08 ;
    END
  END o[297]
  PIN o[298]
    DIRECTION OUTPUT ;
    USE SIGNAL ;
    PORT
      LAYER M4 ;
        RECT  21.516 43.152 21.6 43.176 ;
    END
  END o[298]
  PIN o[299]
    DIRECTION OUTPUT ;
    USE SIGNAL ;
    PORT
      LAYER M4 ;
        RECT  21.516 43.248 21.6 43.272 ;
    END
  END o[299]
  PIN o[29]
    DIRECTION OUTPUT ;
    USE SIGNAL ;
    PORT
      LAYER M4 ;
        RECT  21.516 22.704 21.6 22.728 ;
    END
  END o[29]
  PIN o[2]
    DIRECTION OUTPUT ;
    USE SIGNAL ;
    PORT
      LAYER M4 ;
        RECT  21.516 20.112 21.6 20.136 ;
    END
  END o[2]
  PIN o[300]
    DIRECTION OUTPUT ;
    USE SIGNAL ;
    PORT
      LAYER M4 ;
        RECT  21.516 43.344 21.6 43.368 ;
    END
  END o[300]
  PIN o[301]
    DIRECTION OUTPUT ;
    USE SIGNAL ;
    PORT
      LAYER M4 ;
        RECT  21.516 43.44 21.6 43.464 ;
    END
  END o[301]
  PIN o[302]
    DIRECTION OUTPUT ;
    USE SIGNAL ;
    PORT
      LAYER M4 ;
        RECT  21.516 43.536 21.6 43.56 ;
    END
  END o[302]
  PIN o[303]
    DIRECTION OUTPUT ;
    USE SIGNAL ;
    PORT
      LAYER M4 ;
        RECT  21.516 43.632 21.6 43.656 ;
    END
  END o[303]
  PIN o[304]
    DIRECTION OUTPUT ;
    USE SIGNAL ;
    PORT
      LAYER M4 ;
        RECT  21.516 43.728 21.6 43.752 ;
    END
  END o[304]
  PIN o[305]
    DIRECTION OUTPUT ;
    USE SIGNAL ;
    PORT
      LAYER M4 ;
        RECT  21.516 43.824 21.6 43.848 ;
    END
  END o[305]
  PIN o[306]
    DIRECTION OUTPUT ;
    USE SIGNAL ;
    PORT
      LAYER M4 ;
        RECT  21.516 43.92 21.6 43.944 ;
    END
  END o[306]
  PIN o[307]
    DIRECTION OUTPUT ;
    USE SIGNAL ;
    PORT
      LAYER M4 ;
        RECT  21.516 44.016 21.6 44.04 ;
    END
  END o[307]
  PIN o[308]
    DIRECTION OUTPUT ;
    USE SIGNAL ;
    PORT
      LAYER M4 ;
        RECT  21.516 44.112 21.6 44.136 ;
    END
  END o[308]
  PIN o[309]
    DIRECTION OUTPUT ;
    USE SIGNAL ;
    PORT
      LAYER M4 ;
        RECT  21.516 44.208 21.6 44.232 ;
    END
  END o[309]
  PIN o[30]
    DIRECTION OUTPUT ;
    USE SIGNAL ;
    PORT
      LAYER M4 ;
        RECT  21.516 22.8 21.6 22.824 ;
    END
  END o[30]
  PIN o[310]
    DIRECTION OUTPUT ;
    USE SIGNAL ;
    PORT
      LAYER M4 ;
        RECT  21.516 44.304 21.6 44.328 ;
    END
  END o[310]
  PIN o[311]
    DIRECTION OUTPUT ;
    USE SIGNAL ;
    PORT
      LAYER M4 ;
        RECT  21.516 44.4 21.6 44.424 ;
    END
  END o[311]
  PIN o[312]
    DIRECTION OUTPUT ;
    USE SIGNAL ;
    PORT
      LAYER M4 ;
        RECT  21.516 44.496 21.6 44.52 ;
    END
  END o[312]
  PIN o[313]
    DIRECTION OUTPUT ;
    USE SIGNAL ;
    PORT
      LAYER M4 ;
        RECT  21.516 44.592 21.6 44.616 ;
    END
  END o[313]
  PIN o[314]
    DIRECTION OUTPUT ;
    USE SIGNAL ;
    PORT
      LAYER M4 ;
        RECT  21.516 44.688 21.6 44.712 ;
    END
  END o[314]
  PIN o[315]
    DIRECTION OUTPUT ;
    USE SIGNAL ;
    PORT
      LAYER M4 ;
        RECT  21.516 44.784 21.6 44.808 ;
    END
  END o[315]
  PIN o[316]
    DIRECTION OUTPUT ;
    USE SIGNAL ;
    PORT
      LAYER M4 ;
        RECT  21.516 44.88 21.6 44.904 ;
    END
  END o[316]
  PIN o[317]
    DIRECTION OUTPUT ;
    USE SIGNAL ;
    PORT
      LAYER M4 ;
        RECT  21.516 44.976 21.6 45 ;
    END
  END o[317]
  PIN o[318]
    DIRECTION OUTPUT ;
    USE SIGNAL ;
    PORT
      LAYER M4 ;
        RECT  21.516 45.072 21.6 45.096 ;
    END
  END o[318]
  PIN o[319]
    DIRECTION OUTPUT ;
    USE SIGNAL ;
    PORT
      LAYER M4 ;
        RECT  21.516 45.168 21.6 45.192 ;
    END
  END o[319]
  PIN o[31]
    DIRECTION OUTPUT ;
    USE SIGNAL ;
    PORT
      LAYER M4 ;
        RECT  21.516 22.896 21.6 22.92 ;
    END
  END o[31]
  PIN o[320]
    DIRECTION OUTPUT ;
    USE SIGNAL ;
    PORT
      LAYER M4 ;
        RECT  21.516 48.336 21.6 48.36 ;
    END
  END o[320]
  PIN o[321]
    DIRECTION OUTPUT ;
    USE SIGNAL ;
    PORT
      LAYER M4 ;
        RECT  21.516 48.432 21.6 48.456 ;
    END
  END o[321]
  PIN o[322]
    DIRECTION OUTPUT ;
    USE SIGNAL ;
    PORT
      LAYER M4 ;
        RECT  21.516 48.528 21.6 48.552 ;
    END
  END o[322]
  PIN o[323]
    DIRECTION OUTPUT ;
    USE SIGNAL ;
    PORT
      LAYER M4 ;
        RECT  21.516 48.624 21.6 48.648 ;
    END
  END o[323]
  PIN o[324]
    DIRECTION OUTPUT ;
    USE SIGNAL ;
    PORT
      LAYER M4 ;
        RECT  21.516 48.72 21.6 48.744 ;
    END
  END o[324]
  PIN o[325]
    DIRECTION OUTPUT ;
    USE SIGNAL ;
    PORT
      LAYER M4 ;
        RECT  21.516 48.816 21.6 48.84 ;
    END
  END o[325]
  PIN o[326]
    DIRECTION OUTPUT ;
    USE SIGNAL ;
    PORT
      LAYER M4 ;
        RECT  21.516 48.912 21.6 48.936 ;
    END
  END o[326]
  PIN o[327]
    DIRECTION OUTPUT ;
    USE SIGNAL ;
    PORT
      LAYER M4 ;
        RECT  21.516 49.008 21.6 49.032 ;
    END
  END o[327]
  PIN o[328]
    DIRECTION OUTPUT ;
    USE SIGNAL ;
    PORT
      LAYER M4 ;
        RECT  21.516 49.104 21.6 49.128 ;
    END
  END o[328]
  PIN o[329]
    DIRECTION OUTPUT ;
    USE SIGNAL ;
    PORT
      LAYER M4 ;
        RECT  21.516 49.2 21.6 49.224 ;
    END
  END o[329]
  PIN o[32]
    DIRECTION OUTPUT ;
    USE SIGNAL ;
    PORT
      LAYER M4 ;
        RECT  21.516 26.064 21.6 26.088 ;
    END
  END o[32]
  PIN o[330]
    DIRECTION OUTPUT ;
    USE SIGNAL ;
    PORT
      LAYER M4 ;
        RECT  21.516 49.296 21.6 49.32 ;
    END
  END o[330]
  PIN o[331]
    DIRECTION OUTPUT ;
    USE SIGNAL ;
    PORT
      LAYER M4 ;
        RECT  21.516 49.392 21.6 49.416 ;
    END
  END o[331]
  PIN o[332]
    DIRECTION OUTPUT ;
    USE SIGNAL ;
    PORT
      LAYER M4 ;
        RECT  21.516 49.488 21.6 49.512 ;
    END
  END o[332]
  PIN o[333]
    DIRECTION OUTPUT ;
    USE SIGNAL ;
    PORT
      LAYER M4 ;
        RECT  21.516 49.584 21.6 49.608 ;
    END
  END o[333]
  PIN o[334]
    DIRECTION OUTPUT ;
    USE SIGNAL ;
    PORT
      LAYER M4 ;
        RECT  21.516 49.68 21.6 49.704 ;
    END
  END o[334]
  PIN o[335]
    DIRECTION OUTPUT ;
    USE SIGNAL ;
    PORT
      LAYER M4 ;
        RECT  21.516 49.776 21.6 49.8 ;
    END
  END o[335]
  PIN o[336]
    DIRECTION OUTPUT ;
    USE SIGNAL ;
    PORT
      LAYER M4 ;
        RECT  21.516 49.872 21.6 49.896 ;
    END
  END o[336]
  PIN o[337]
    DIRECTION OUTPUT ;
    USE SIGNAL ;
    PORT
      LAYER M4 ;
        RECT  21.516 49.968 21.6 49.992 ;
    END
  END o[337]
  PIN o[338]
    DIRECTION OUTPUT ;
    USE SIGNAL ;
    PORT
      LAYER M4 ;
        RECT  21.516 50.064 21.6 50.088 ;
    END
  END o[338]
  PIN o[339]
    DIRECTION OUTPUT ;
    USE SIGNAL ;
    PORT
      LAYER M4 ;
        RECT  21.516 50.16 21.6 50.184 ;
    END
  END o[339]
  PIN o[33]
    DIRECTION OUTPUT ;
    USE SIGNAL ;
    PORT
      LAYER M4 ;
        RECT  21.516 26.16 21.6 26.184 ;
    END
  END o[33]
  PIN o[340]
    DIRECTION OUTPUT ;
    USE SIGNAL ;
    PORT
      LAYER M4 ;
        RECT  21.516 50.256 21.6 50.28 ;
    END
  END o[340]
  PIN o[341]
    DIRECTION OUTPUT ;
    USE SIGNAL ;
    PORT
      LAYER M4 ;
        RECT  21.516 50.352 21.6 50.376 ;
    END
  END o[341]
  PIN o[342]
    DIRECTION OUTPUT ;
    USE SIGNAL ;
    PORT
      LAYER M4 ;
        RECT  21.516 50.448 21.6 50.472 ;
    END
  END o[342]
  PIN o[343]
    DIRECTION OUTPUT ;
    USE SIGNAL ;
    PORT
      LAYER M4 ;
        RECT  21.516 50.544 21.6 50.568 ;
    END
  END o[343]
  PIN o[344]
    DIRECTION OUTPUT ;
    USE SIGNAL ;
    PORT
      LAYER M4 ;
        RECT  21.516 50.64 21.6 50.664 ;
    END
  END o[344]
  PIN o[345]
    DIRECTION OUTPUT ;
    USE SIGNAL ;
    PORT
      LAYER M4 ;
        RECT  21.516 50.736 21.6 50.76 ;
    END
  END o[345]
  PIN o[346]
    DIRECTION OUTPUT ;
    USE SIGNAL ;
    PORT
      LAYER M4 ;
        RECT  21.516 50.832 21.6 50.856 ;
    END
  END o[346]
  PIN o[347]
    DIRECTION OUTPUT ;
    USE SIGNAL ;
    PORT
      LAYER M4 ;
        RECT  21.516 50.928 21.6 50.952 ;
    END
  END o[347]
  PIN o[348]
    DIRECTION OUTPUT ;
    USE SIGNAL ;
    PORT
      LAYER M4 ;
        RECT  21.516 51.024 21.6 51.048 ;
    END
  END o[348]
  PIN o[349]
    DIRECTION OUTPUT ;
    USE SIGNAL ;
    PORT
      LAYER M4 ;
        RECT  21.516 51.12 21.6 51.144 ;
    END
  END o[349]
  PIN o[34]
    DIRECTION OUTPUT ;
    USE SIGNAL ;
    PORT
      LAYER M4 ;
        RECT  21.516 26.256 21.6 26.28 ;
    END
  END o[34]
  PIN o[350]
    DIRECTION OUTPUT ;
    USE SIGNAL ;
    PORT
      LAYER M4 ;
        RECT  21.516 51.216 21.6 51.24 ;
    END
  END o[350]
  PIN o[351]
    DIRECTION OUTPUT ;
    USE SIGNAL ;
    PORT
      LAYER M4 ;
        RECT  21.516 51.312 21.6 51.336 ;
    END
  END o[351]
  PIN o[352]
    DIRECTION OUTPUT ;
    USE SIGNAL ;
    PORT
      LAYER M4 ;
        RECT  21.516 51.408 21.6 51.432 ;
    END
  END o[352]
  PIN o[353]
    DIRECTION OUTPUT ;
    USE SIGNAL ;
    PORT
      LAYER M4 ;
        RECT  21.516 51.504 21.6 51.528 ;
    END
  END o[353]
  PIN o[354]
    DIRECTION OUTPUT ;
    USE SIGNAL ;
    PORT
      LAYER M4 ;
        RECT  21.516 51.6 21.6 51.624 ;
    END
  END o[354]
  PIN o[355]
    DIRECTION OUTPUT ;
    USE SIGNAL ;
    PORT
      LAYER M4 ;
        RECT  21.516 51.696 21.6 51.72 ;
    END
  END o[355]
  PIN o[356]
    DIRECTION OUTPUT ;
    USE SIGNAL ;
    PORT
      LAYER M4 ;
        RECT  21.516 51.792 21.6 51.816 ;
    END
  END o[356]
  PIN o[357]
    DIRECTION OUTPUT ;
    USE SIGNAL ;
    PORT
      LAYER M4 ;
        RECT  21.516 51.888 21.6 51.912 ;
    END
  END o[357]
  PIN o[358]
    DIRECTION OUTPUT ;
    USE SIGNAL ;
    PORT
      LAYER M4 ;
        RECT  21.516 51.984 21.6 52.008 ;
    END
  END o[358]
  PIN o[359]
    DIRECTION OUTPUT ;
    USE SIGNAL ;
    PORT
      LAYER M4 ;
        RECT  21.516 52.08 21.6 52.104 ;
    END
  END o[359]
  PIN o[35]
    DIRECTION OUTPUT ;
    USE SIGNAL ;
    PORT
      LAYER M4 ;
        RECT  21.516 26.352 21.6 26.376 ;
    END
  END o[35]
  PIN o[360]
    DIRECTION OUTPUT ;
    USE SIGNAL ;
    PORT
      LAYER M4 ;
        RECT  21.516 52.176 21.6 52.2 ;
    END
  END o[360]
  PIN o[361]
    DIRECTION OUTPUT ;
    USE SIGNAL ;
    PORT
      LAYER M4 ;
        RECT  21.516 52.272 21.6 52.296 ;
    END
  END o[361]
  PIN o[362]
    DIRECTION OUTPUT ;
    USE SIGNAL ;
    PORT
      LAYER M4 ;
        RECT  21.516 52.368 21.6 52.392 ;
    END
  END o[362]
  PIN o[363]
    DIRECTION OUTPUT ;
    USE SIGNAL ;
    PORT
      LAYER M4 ;
        RECT  21.516 52.464 21.6 52.488 ;
    END
  END o[363]
  PIN o[364]
    DIRECTION OUTPUT ;
    USE SIGNAL ;
    PORT
      LAYER M4 ;
        RECT  21.516 52.56 21.6 52.584 ;
    END
  END o[364]
  PIN o[365]
    DIRECTION OUTPUT ;
    USE SIGNAL ;
    PORT
      LAYER M4 ;
        RECT  21.516 52.656 21.6 52.68 ;
    END
  END o[365]
  PIN o[366]
    DIRECTION OUTPUT ;
    USE SIGNAL ;
    PORT
      LAYER M4 ;
        RECT  21.516 52.752 21.6 52.776 ;
    END
  END o[366]
  PIN o[367]
    DIRECTION OUTPUT ;
    USE SIGNAL ;
    PORT
      LAYER M4 ;
        RECT  21.516 52.848 21.6 52.872 ;
    END
  END o[367]
  PIN o[368]
    DIRECTION OUTPUT ;
    USE SIGNAL ;
    PORT
      LAYER M4 ;
        RECT  21.516 52.944 21.6 52.968 ;
    END
  END o[368]
  PIN o[369]
    DIRECTION OUTPUT ;
    USE SIGNAL ;
    PORT
      LAYER M4 ;
        RECT  21.516 53.04 21.6 53.064 ;
    END
  END o[369]
  PIN o[36]
    DIRECTION OUTPUT ;
    USE SIGNAL ;
    PORT
      LAYER M4 ;
        RECT  21.516 26.448 21.6 26.472 ;
    END
  END o[36]
  PIN o[370]
    DIRECTION OUTPUT ;
    USE SIGNAL ;
    PORT
      LAYER M4 ;
        RECT  21.516 53.136 21.6 53.16 ;
    END
  END o[370]
  PIN o[371]
    DIRECTION OUTPUT ;
    USE SIGNAL ;
    PORT
      LAYER M4 ;
        RECT  21.516 53.232 21.6 53.256 ;
    END
  END o[371]
  PIN o[372]
    DIRECTION OUTPUT ;
    USE SIGNAL ;
    PORT
      LAYER M4 ;
        RECT  21.516 53.328 21.6 53.352 ;
    END
  END o[372]
  PIN o[373]
    DIRECTION OUTPUT ;
    USE SIGNAL ;
    PORT
      LAYER M4 ;
        RECT  21.516 53.424 21.6 53.448 ;
    END
  END o[373]
  PIN o[374]
    DIRECTION OUTPUT ;
    USE SIGNAL ;
    PORT
      LAYER M4 ;
        RECT  21.516 53.52 21.6 53.544 ;
    END
  END o[374]
  PIN o[375]
    DIRECTION OUTPUT ;
    USE SIGNAL ;
    PORT
      LAYER M4 ;
        RECT  21.516 53.616 21.6 53.64 ;
    END
  END o[375]
  PIN o[376]
    DIRECTION OUTPUT ;
    USE SIGNAL ;
    PORT
      LAYER M4 ;
        RECT  21.516 53.712 21.6 53.736 ;
    END
  END o[376]
  PIN o[377]
    DIRECTION OUTPUT ;
    USE SIGNAL ;
    PORT
      LAYER M4 ;
        RECT  21.516 53.808 21.6 53.832 ;
    END
  END o[377]
  PIN o[378]
    DIRECTION OUTPUT ;
    USE SIGNAL ;
    PORT
      LAYER M4 ;
        RECT  21.516 53.904 21.6 53.928 ;
    END
  END o[378]
  PIN o[379]
    DIRECTION OUTPUT ;
    USE SIGNAL ;
    PORT
      LAYER M4 ;
        RECT  21.516 54 21.6 54.024 ;
    END
  END o[379]
  PIN o[37]
    DIRECTION OUTPUT ;
    USE SIGNAL ;
    PORT
      LAYER M4 ;
        RECT  21.516 26.544 21.6 26.568 ;
    END
  END o[37]
  PIN o[380]
    DIRECTION OUTPUT ;
    USE SIGNAL ;
    PORT
      LAYER M4 ;
        RECT  21.516 54.096 21.6 54.12 ;
    END
  END o[380]
  PIN o[381]
    DIRECTION OUTPUT ;
    USE SIGNAL ;
    PORT
      LAYER M4 ;
        RECT  21.516 54.192 21.6 54.216 ;
    END
  END o[381]
  PIN o[382]
    DIRECTION OUTPUT ;
    USE SIGNAL ;
    PORT
      LAYER M4 ;
        RECT  21.516 54.288 21.6 54.312 ;
    END
  END o[382]
  PIN o[383]
    DIRECTION OUTPUT ;
    USE SIGNAL ;
    PORT
      LAYER M4 ;
        RECT  21.516 54.384 21.6 54.408 ;
    END
  END o[383]
  PIN o[384]
    DIRECTION OUTPUT ;
    USE SIGNAL ;
    PORT
      LAYER M4 ;
        RECT  21.516 54.48 21.6 54.504 ;
    END
  END o[384]
  PIN o[385]
    DIRECTION OUTPUT ;
    USE SIGNAL ;
    PORT
      LAYER M4 ;
        RECT  21.516 54.576 21.6 54.6 ;
    END
  END o[385]
  PIN o[386]
    DIRECTION OUTPUT ;
    USE SIGNAL ;
    PORT
      LAYER M4 ;
        RECT  21.516 54.672 21.6 54.696 ;
    END
  END o[386]
  PIN o[387]
    DIRECTION OUTPUT ;
    USE SIGNAL ;
    PORT
      LAYER M4 ;
        RECT  21.516 54.768 21.6 54.792 ;
    END
  END o[387]
  PIN o[388]
    DIRECTION OUTPUT ;
    USE SIGNAL ;
    PORT
      LAYER M4 ;
        RECT  21.516 54.864 21.6 54.888 ;
    END
  END o[388]
  PIN o[389]
    DIRECTION OUTPUT ;
    USE SIGNAL ;
    PORT
      LAYER M4 ;
        RECT  21.516 54.96 21.6 54.984 ;
    END
  END o[389]
  PIN o[38]
    DIRECTION OUTPUT ;
    USE SIGNAL ;
    PORT
      LAYER M4 ;
        RECT  21.516 26.64 21.6 26.664 ;
    END
  END o[38]
  PIN o[390]
    DIRECTION OUTPUT ;
    USE SIGNAL ;
    PORT
      LAYER M4 ;
        RECT  21.516 55.056 21.6 55.08 ;
    END
  END o[390]
  PIN o[391]
    DIRECTION OUTPUT ;
    USE SIGNAL ;
    PORT
      LAYER M4 ;
        RECT  21.516 55.152 21.6 55.176 ;
    END
  END o[391]
  PIN o[392]
    DIRECTION OUTPUT ;
    USE SIGNAL ;
    PORT
      LAYER M4 ;
        RECT  21.516 55.248 21.6 55.272 ;
    END
  END o[392]
  PIN o[393]
    DIRECTION OUTPUT ;
    USE SIGNAL ;
    PORT
      LAYER M4 ;
        RECT  21.516 55.344 21.6 55.368 ;
    END
  END o[393]
  PIN o[394]
    DIRECTION OUTPUT ;
    USE SIGNAL ;
    PORT
      LAYER M4 ;
        RECT  21.516 55.44 21.6 55.464 ;
    END
  END o[394]
  PIN o[395]
    DIRECTION OUTPUT ;
    USE SIGNAL ;
    PORT
      LAYER M4 ;
        RECT  21.516 55.536 21.6 55.56 ;
    END
  END o[395]
  PIN o[396]
    DIRECTION OUTPUT ;
    USE SIGNAL ;
    PORT
      LAYER M4 ;
        RECT  21.516 55.632 21.6 55.656 ;
    END
  END o[396]
  PIN o[397]
    DIRECTION OUTPUT ;
    USE SIGNAL ;
    PORT
      LAYER M4 ;
        RECT  21.516 55.728 21.6 55.752 ;
    END
  END o[397]
  PIN o[398]
    DIRECTION OUTPUT ;
    USE SIGNAL ;
    PORT
      LAYER M4 ;
        RECT  21.516 55.824 21.6 55.848 ;
    END
  END o[398]
  PIN o[399]
    DIRECTION OUTPUT ;
    USE SIGNAL ;
    PORT
      LAYER M4 ;
        RECT  21.516 55.92 21.6 55.944 ;
    END
  END o[399]
  PIN o[39]
    DIRECTION OUTPUT ;
    USE SIGNAL ;
    PORT
      LAYER M4 ;
        RECT  21.516 26.736 21.6 26.76 ;
    END
  END o[39]
  PIN o[3]
    DIRECTION OUTPUT ;
    USE SIGNAL ;
    PORT
      LAYER M4 ;
        RECT  21.516 20.208 21.6 20.232 ;
    END
  END o[3]
  PIN o[400]
    DIRECTION OUTPUT ;
    USE SIGNAL ;
    PORT
      LAYER M4 ;
        RECT  21.516 56.016 21.6 56.04 ;
    END
  END o[400]
  PIN o[401]
    DIRECTION OUTPUT ;
    USE SIGNAL ;
    PORT
      LAYER M4 ;
        RECT  21.516 56.112 21.6 56.136 ;
    END
  END o[401]
  PIN o[402]
    DIRECTION OUTPUT ;
    USE SIGNAL ;
    PORT
      LAYER M4 ;
        RECT  21.516 56.208 21.6 56.232 ;
    END
  END o[402]
  PIN o[403]
    DIRECTION OUTPUT ;
    USE SIGNAL ;
    PORT
      LAYER M4 ;
        RECT  21.516 56.304 21.6 56.328 ;
    END
  END o[403]
  PIN o[404]
    DIRECTION OUTPUT ;
    USE SIGNAL ;
    PORT
      LAYER M4 ;
        RECT  21.516 56.4 21.6 56.424 ;
    END
  END o[404]
  PIN o[405]
    DIRECTION OUTPUT ;
    USE SIGNAL ;
    PORT
      LAYER M4 ;
        RECT  21.516 56.496 21.6 56.52 ;
    END
  END o[405]
  PIN o[406]
    DIRECTION OUTPUT ;
    USE SIGNAL ;
    PORT
      LAYER M4 ;
        RECT  21.516 56.592 21.6 56.616 ;
    END
  END o[406]
  PIN o[407]
    DIRECTION OUTPUT ;
    USE SIGNAL ;
    PORT
      LAYER M4 ;
        RECT  21.516 56.688 21.6 56.712 ;
    END
  END o[407]
  PIN o[408]
    DIRECTION OUTPUT ;
    USE SIGNAL ;
    PORT
      LAYER M4 ;
        RECT  21.516 56.784 21.6 56.808 ;
    END
  END o[408]
  PIN o[409]
    DIRECTION OUTPUT ;
    USE SIGNAL ;
    PORT
      LAYER M4 ;
        RECT  21.516 56.88 21.6 56.904 ;
    END
  END o[409]
  PIN o[40]
    DIRECTION OUTPUT ;
    USE SIGNAL ;
    PORT
      LAYER M4 ;
        RECT  21.516 26.832 21.6 26.856 ;
    END
  END o[40]
  PIN o[410]
    DIRECTION OUTPUT ;
    USE SIGNAL ;
    PORT
      LAYER M4 ;
        RECT  21.516 56.976 21.6 57 ;
    END
  END o[410]
  PIN o[411]
    DIRECTION OUTPUT ;
    USE SIGNAL ;
    PORT
      LAYER M4 ;
        RECT  21.516 57.072 21.6 57.096 ;
    END
  END o[411]
  PIN o[412]
    DIRECTION OUTPUT ;
    USE SIGNAL ;
    PORT
      LAYER M4 ;
        RECT  21.516 57.168 21.6 57.192 ;
    END
  END o[412]
  PIN o[413]
    DIRECTION OUTPUT ;
    USE SIGNAL ;
    PORT
      LAYER M4 ;
        RECT  21.516 57.264 21.6 57.288 ;
    END
  END o[413]
  PIN o[414]
    DIRECTION OUTPUT ;
    USE SIGNAL ;
    PORT
      LAYER M4 ;
        RECT  21.516 57.36 21.6 57.384 ;
    END
  END o[414]
  PIN o[415]
    DIRECTION OUTPUT ;
    USE SIGNAL ;
    PORT
      LAYER M4 ;
        RECT  21.516 57.456 21.6 57.48 ;
    END
  END o[415]
  PIN o[416]
    DIRECTION OUTPUT ;
    USE SIGNAL ;
    PORT
      LAYER M4 ;
        RECT  21.516 45.264 21.6 45.288 ;
    END
  END o[416]
  PIN o[417]
    DIRECTION OUTPUT ;
    USE SIGNAL ;
    PORT
      LAYER M4 ;
        RECT  21.516 45.36 21.6 45.384 ;
    END
  END o[417]
  PIN o[418]
    DIRECTION OUTPUT ;
    USE SIGNAL ;
    PORT
      LAYER M4 ;
        RECT  21.516 45.456 21.6 45.48 ;
    END
  END o[418]
  PIN o[419]
    DIRECTION OUTPUT ;
    USE SIGNAL ;
    PORT
      LAYER M4 ;
        RECT  21.516 45.552 21.6 45.576 ;
    END
  END o[419]
  PIN o[41]
    DIRECTION OUTPUT ;
    USE SIGNAL ;
    PORT
      LAYER M4 ;
        RECT  21.516 26.928 21.6 26.952 ;
    END
  END o[41]
  PIN o[420]
    DIRECTION OUTPUT ;
    USE SIGNAL ;
    PORT
      LAYER M4 ;
        RECT  21.516 45.648 21.6 45.672 ;
    END
  END o[420]
  PIN o[421]
    DIRECTION OUTPUT ;
    USE SIGNAL ;
    PORT
      LAYER M4 ;
        RECT  21.516 45.744 21.6 45.768 ;
    END
  END o[421]
  PIN o[422]
    DIRECTION OUTPUT ;
    USE SIGNAL ;
    PORT
      LAYER M4 ;
        RECT  21.516 45.84 21.6 45.864 ;
    END
  END o[422]
  PIN o[423]
    DIRECTION OUTPUT ;
    USE SIGNAL ;
    PORT
      LAYER M4 ;
        RECT  21.516 45.936 21.6 45.96 ;
    END
  END o[423]
  PIN o[424]
    DIRECTION OUTPUT ;
    USE SIGNAL ;
    PORT
      LAYER M4 ;
        RECT  21.516 46.032 21.6 46.056 ;
    END
  END o[424]
  PIN o[425]
    DIRECTION OUTPUT ;
    USE SIGNAL ;
    PORT
      LAYER M4 ;
        RECT  21.516 46.128 21.6 46.152 ;
    END
  END o[425]
  PIN o[426]
    DIRECTION OUTPUT ;
    USE SIGNAL ;
    PORT
      LAYER M4 ;
        RECT  21.516 46.224 21.6 46.248 ;
    END
  END o[426]
  PIN o[427]
    DIRECTION OUTPUT ;
    USE SIGNAL ;
    PORT
      LAYER M4 ;
        RECT  21.516 46.32 21.6 46.344 ;
    END
  END o[427]
  PIN o[428]
    DIRECTION OUTPUT ;
    USE SIGNAL ;
    PORT
      LAYER M4 ;
        RECT  21.516 46.416 21.6 46.44 ;
    END
  END o[428]
  PIN o[429]
    DIRECTION OUTPUT ;
    USE SIGNAL ;
    PORT
      LAYER M4 ;
        RECT  21.516 46.512 21.6 46.536 ;
    END
  END o[429]
  PIN o[42]
    DIRECTION OUTPUT ;
    USE SIGNAL ;
    PORT
      LAYER M4 ;
        RECT  21.516 27.024 21.6 27.048 ;
    END
  END o[42]
  PIN o[430]
    DIRECTION OUTPUT ;
    USE SIGNAL ;
    PORT
      LAYER M4 ;
        RECT  21.516 46.608 21.6 46.632 ;
    END
  END o[430]
  PIN o[431]
    DIRECTION OUTPUT ;
    USE SIGNAL ;
    PORT
      LAYER M4 ;
        RECT  21.516 46.704 21.6 46.728 ;
    END
  END o[431]
  PIN o[432]
    DIRECTION OUTPUT ;
    USE SIGNAL ;
    PORT
      LAYER M4 ;
        RECT  21.516 46.8 21.6 46.824 ;
    END
  END o[432]
  PIN o[433]
    DIRECTION OUTPUT ;
    USE SIGNAL ;
    PORT
      LAYER M4 ;
        RECT  21.516 46.896 21.6 46.92 ;
    END
  END o[433]
  PIN o[434]
    DIRECTION OUTPUT ;
    USE SIGNAL ;
    PORT
      LAYER M4 ;
        RECT  21.516 46.992 21.6 47.016 ;
    END
  END o[434]
  PIN o[435]
    DIRECTION OUTPUT ;
    USE SIGNAL ;
    PORT
      LAYER M4 ;
        RECT  21.516 47.088 21.6 47.112 ;
    END
  END o[435]
  PIN o[436]
    DIRECTION OUTPUT ;
    USE SIGNAL ;
    PORT
      LAYER M4 ;
        RECT  21.516 47.184 21.6 47.208 ;
    END
  END o[436]
  PIN o[437]
    DIRECTION OUTPUT ;
    USE SIGNAL ;
    PORT
      LAYER M4 ;
        RECT  21.516 47.28 21.6 47.304 ;
    END
  END o[437]
  PIN o[438]
    DIRECTION OUTPUT ;
    USE SIGNAL ;
    PORT
      LAYER M4 ;
        RECT  21.516 47.376 21.6 47.4 ;
    END
  END o[438]
  PIN o[439]
    DIRECTION OUTPUT ;
    USE SIGNAL ;
    PORT
      LAYER M4 ;
        RECT  21.516 47.472 21.6 47.496 ;
    END
  END o[439]
  PIN o[43]
    DIRECTION OUTPUT ;
    USE SIGNAL ;
    PORT
      LAYER M4 ;
        RECT  21.516 27.12 21.6 27.144 ;
    END
  END o[43]
  PIN o[440]
    DIRECTION OUTPUT ;
    USE SIGNAL ;
    PORT
      LAYER M4 ;
        RECT  21.516 47.568 21.6 47.592 ;
    END
  END o[440]
  PIN o[441]
    DIRECTION OUTPUT ;
    USE SIGNAL ;
    PORT
      LAYER M4 ;
        RECT  21.516 47.664 21.6 47.688 ;
    END
  END o[441]
  PIN o[442]
    DIRECTION OUTPUT ;
    USE SIGNAL ;
    PORT
      LAYER M4 ;
        RECT  21.516 47.76 21.6 47.784 ;
    END
  END o[442]
  PIN o[443]
    DIRECTION OUTPUT ;
    USE SIGNAL ;
    PORT
      LAYER M4 ;
        RECT  21.516 47.856 21.6 47.88 ;
    END
  END o[443]
  PIN o[444]
    DIRECTION OUTPUT ;
    USE SIGNAL ;
    PORT
      LAYER M4 ;
        RECT  21.516 47.952 21.6 47.976 ;
    END
  END o[444]
  PIN o[445]
    DIRECTION OUTPUT ;
    USE SIGNAL ;
    PORT
      LAYER M4 ;
        RECT  21.516 48.048 21.6 48.072 ;
    END
  END o[445]
  PIN o[446]
    DIRECTION OUTPUT ;
    USE SIGNAL ;
    PORT
      LAYER M4 ;
        RECT  21.516 48.144 21.6 48.168 ;
    END
  END o[446]
  PIN o[447]
    DIRECTION OUTPUT ;
    USE SIGNAL ;
    PORT
      LAYER M4 ;
        RECT  21.516 48.24 21.6 48.264 ;
    END
  END o[447]
  PIN o[448]
    DIRECTION OUTPUT ;
    USE SIGNAL ;
    PORT
      LAYER M4 ;
        RECT  21.516 58.32 21.6 58.344 ;
    END
  END o[448]
  PIN o[449]
    DIRECTION OUTPUT ;
    USE SIGNAL ;
    PORT
      LAYER M4 ;
        RECT  21.516 58.416 21.6 58.44 ;
    END
  END o[449]
  PIN o[44]
    DIRECTION OUTPUT ;
    USE SIGNAL ;
    PORT
      LAYER M4 ;
        RECT  21.516 27.216 21.6 27.24 ;
    END
  END o[44]
  PIN o[450]
    DIRECTION OUTPUT ;
    USE SIGNAL ;
    PORT
      LAYER M4 ;
        RECT  21.516 58.512 21.6 58.536 ;
    END
  END o[450]
  PIN o[451]
    DIRECTION OUTPUT ;
    USE SIGNAL ;
    PORT
      LAYER M4 ;
        RECT  21.516 58.608 21.6 58.632 ;
    END
  END o[451]
  PIN o[452]
    DIRECTION OUTPUT ;
    USE SIGNAL ;
    PORT
      LAYER M4 ;
        RECT  21.516 58.704 21.6 58.728 ;
    END
  END o[452]
  PIN o[453]
    DIRECTION OUTPUT ;
    USE SIGNAL ;
    PORT
      LAYER M4 ;
        RECT  21.516 58.8 21.6 58.824 ;
    END
  END o[453]
  PIN o[454]
    DIRECTION OUTPUT ;
    USE SIGNAL ;
    PORT
      LAYER M4 ;
        RECT  21.516 58.896 21.6 58.92 ;
    END
  END o[454]
  PIN o[455]
    DIRECTION OUTPUT ;
    USE SIGNAL ;
    PORT
      LAYER M4 ;
        RECT  21.516 58.992 21.6 59.016 ;
    END
  END o[455]
  PIN o[456]
    DIRECTION OUTPUT ;
    USE SIGNAL ;
    PORT
      LAYER M4 ;
        RECT  21.516 59.088 21.6 59.112 ;
    END
  END o[456]
  PIN o[457]
    DIRECTION OUTPUT ;
    USE SIGNAL ;
    PORT
      LAYER M4 ;
        RECT  21.516 59.184 21.6 59.208 ;
    END
  END o[457]
  PIN o[458]
    DIRECTION OUTPUT ;
    USE SIGNAL ;
    PORT
      LAYER M4 ;
        RECT  21.516 59.28 21.6 59.304 ;
    END
  END o[458]
  PIN o[459]
    DIRECTION OUTPUT ;
    USE SIGNAL ;
    PORT
      LAYER M4 ;
        RECT  21.516 59.376 21.6 59.4 ;
    END
  END o[459]
  PIN o[45]
    DIRECTION OUTPUT ;
    USE SIGNAL ;
    PORT
      LAYER M4 ;
        RECT  21.516 27.312 21.6 27.336 ;
    END
  END o[45]
  PIN o[460]
    DIRECTION OUTPUT ;
    USE SIGNAL ;
    PORT
      LAYER M4 ;
        RECT  21.516 59.472 21.6 59.496 ;
    END
  END o[460]
  PIN o[461]
    DIRECTION OUTPUT ;
    USE SIGNAL ;
    PORT
      LAYER M4 ;
        RECT  21.516 59.568 21.6 59.592 ;
    END
  END o[461]
  PIN o[462]
    DIRECTION OUTPUT ;
    USE SIGNAL ;
    PORT
      LAYER M4 ;
        RECT  21.516 59.664 21.6 59.688 ;
    END
  END o[462]
  PIN o[463]
    DIRECTION OUTPUT ;
    USE SIGNAL ;
    PORT
      LAYER M4 ;
        RECT  21.516 59.76 21.6 59.784 ;
    END
  END o[463]
  PIN o[464]
    DIRECTION OUTPUT ;
    USE SIGNAL ;
    PORT
      LAYER M4 ;
        RECT  21.516 59.856 21.6 59.88 ;
    END
  END o[464]
  PIN o[465]
    DIRECTION OUTPUT ;
    USE SIGNAL ;
    PORT
      LAYER M4 ;
        RECT  21.516 59.952 21.6 59.976 ;
    END
  END o[465]
  PIN o[466]
    DIRECTION OUTPUT ;
    USE SIGNAL ;
    PORT
      LAYER M4 ;
        RECT  21.516 60.048 21.6 60.072 ;
    END
  END o[466]
  PIN o[467]
    DIRECTION OUTPUT ;
    USE SIGNAL ;
    PORT
      LAYER M4 ;
        RECT  21.516 60.144 21.6 60.168 ;
    END
  END o[467]
  PIN o[468]
    DIRECTION OUTPUT ;
    USE SIGNAL ;
    PORT
      LAYER M4 ;
        RECT  21.516 60.24 21.6 60.264 ;
    END
  END o[468]
  PIN o[469]
    DIRECTION OUTPUT ;
    USE SIGNAL ;
    PORT
      LAYER M4 ;
        RECT  21.516 60.336 21.6 60.36 ;
    END
  END o[469]
  PIN o[46]
    DIRECTION OUTPUT ;
    USE SIGNAL ;
    PORT
      LAYER M4 ;
        RECT  21.516 27.408 21.6 27.432 ;
    END
  END o[46]
  PIN o[470]
    DIRECTION OUTPUT ;
    USE SIGNAL ;
    PORT
      LAYER M4 ;
        RECT  21.516 60.432 21.6 60.456 ;
    END
  END o[470]
  PIN o[471]
    DIRECTION OUTPUT ;
    USE SIGNAL ;
    PORT
      LAYER M4 ;
        RECT  21.516 60.528 21.6 60.552 ;
    END
  END o[471]
  PIN o[472]
    DIRECTION OUTPUT ;
    USE SIGNAL ;
    PORT
      LAYER M4 ;
        RECT  21.516 60.624 21.6 60.648 ;
    END
  END o[472]
  PIN o[473]
    DIRECTION OUTPUT ;
    USE SIGNAL ;
    PORT
      LAYER M4 ;
        RECT  21.516 60.72 21.6 60.744 ;
    END
  END o[473]
  PIN o[474]
    DIRECTION OUTPUT ;
    USE SIGNAL ;
    PORT
      LAYER M4 ;
        RECT  21.516 60.816 21.6 60.84 ;
    END
  END o[474]
  PIN o[475]
    DIRECTION OUTPUT ;
    USE SIGNAL ;
    PORT
      LAYER M4 ;
        RECT  21.516 60.912 21.6 60.936 ;
    END
  END o[475]
  PIN o[476]
    DIRECTION OUTPUT ;
    USE SIGNAL ;
    PORT
      LAYER M4 ;
        RECT  21.516 61.008 21.6 61.032 ;
    END
  END o[476]
  PIN o[477]
    DIRECTION OUTPUT ;
    USE SIGNAL ;
    PORT
      LAYER M4 ;
        RECT  21.516 61.104 21.6 61.128 ;
    END
  END o[477]
  PIN o[478]
    DIRECTION OUTPUT ;
    USE SIGNAL ;
    PORT
      LAYER M4 ;
        RECT  21.516 61.2 21.6 61.224 ;
    END
  END o[478]
  PIN o[479]
    DIRECTION OUTPUT ;
    USE SIGNAL ;
    PORT
      LAYER M4 ;
        RECT  21.516 61.296 21.6 61.32 ;
    END
  END o[479]
  PIN o[47]
    DIRECTION OUTPUT ;
    USE SIGNAL ;
    PORT
      LAYER M4 ;
        RECT  21.516 27.504 21.6 27.528 ;
    END
  END o[47]
  PIN o[480]
    DIRECTION OUTPUT ;
    USE SIGNAL ;
    PORT
      LAYER M4 ;
        RECT  21.516 16.08 21.6 16.104 ;
    END
  END o[480]
  PIN o[481]
    DIRECTION OUTPUT ;
    USE SIGNAL ;
    PORT
      LAYER M4 ;
        RECT  21.516 16.176 21.6 16.2 ;
    END
  END o[481]
  PIN o[482]
    DIRECTION OUTPUT ;
    USE SIGNAL ;
    PORT
      LAYER M4 ;
        RECT  21.516 16.272 21.6 16.296 ;
    END
  END o[482]
  PIN o[483]
    DIRECTION OUTPUT ;
    USE SIGNAL ;
    PORT
      LAYER M4 ;
        RECT  21.516 16.368 21.6 16.392 ;
    END
  END o[483]
  PIN o[484]
    DIRECTION OUTPUT ;
    USE SIGNAL ;
    PORT
      LAYER M4 ;
        RECT  21.516 16.464 21.6 16.488 ;
    END
  END o[484]
  PIN o[485]
    DIRECTION OUTPUT ;
    USE SIGNAL ;
    PORT
      LAYER M4 ;
        RECT  21.516 16.56 21.6 16.584 ;
    END
  END o[485]
  PIN o[486]
    DIRECTION OUTPUT ;
    USE SIGNAL ;
    PORT
      LAYER M4 ;
        RECT  21.516 16.656 21.6 16.68 ;
    END
  END o[486]
  PIN o[487]
    DIRECTION OUTPUT ;
    USE SIGNAL ;
    PORT
      LAYER M4 ;
        RECT  21.516 16.752 21.6 16.776 ;
    END
  END o[487]
  PIN o[488]
    DIRECTION OUTPUT ;
    USE SIGNAL ;
    PORT
      LAYER M4 ;
        RECT  21.516 16.848 21.6 16.872 ;
    END
  END o[488]
  PIN o[489]
    DIRECTION OUTPUT ;
    USE SIGNAL ;
    PORT
      LAYER M4 ;
        RECT  21.516 16.944 21.6 16.968 ;
    END
  END o[489]
  PIN o[48]
    DIRECTION OUTPUT ;
    USE SIGNAL ;
    PORT
      LAYER M4 ;
        RECT  21.516 27.6 21.6 27.624 ;
    END
  END o[48]
  PIN o[490]
    DIRECTION OUTPUT ;
    USE SIGNAL ;
    PORT
      LAYER M4 ;
        RECT  21.516 17.04 21.6 17.064 ;
    END
  END o[490]
  PIN o[491]
    DIRECTION OUTPUT ;
    USE SIGNAL ;
    PORT
      LAYER M4 ;
        RECT  21.516 17.136 21.6 17.16 ;
    END
  END o[491]
  PIN o[492]
    DIRECTION OUTPUT ;
    USE SIGNAL ;
    PORT
      LAYER M4 ;
        RECT  21.516 17.232 21.6 17.256 ;
    END
  END o[492]
  PIN o[493]
    DIRECTION OUTPUT ;
    USE SIGNAL ;
    PORT
      LAYER M4 ;
        RECT  21.516 17.328 21.6 17.352 ;
    END
  END o[493]
  PIN o[494]
    DIRECTION OUTPUT ;
    USE SIGNAL ;
    PORT
      LAYER M4 ;
        RECT  21.516 17.424 21.6 17.448 ;
    END
  END o[494]
  PIN o[495]
    DIRECTION OUTPUT ;
    USE SIGNAL ;
    PORT
      LAYER M4 ;
        RECT  21.516 17.52 21.6 17.544 ;
    END
  END o[495]
  PIN o[496]
    DIRECTION OUTPUT ;
    USE SIGNAL ;
    PORT
      LAYER M4 ;
        RECT  21.516 17.616 21.6 17.64 ;
    END
  END o[496]
  PIN o[497]
    DIRECTION OUTPUT ;
    USE SIGNAL ;
    PORT
      LAYER M4 ;
        RECT  21.516 17.712 21.6 17.736 ;
    END
  END o[497]
  PIN o[498]
    DIRECTION OUTPUT ;
    USE SIGNAL ;
    PORT
      LAYER M4 ;
        RECT  21.516 17.808 21.6 17.832 ;
    END
  END o[498]
  PIN o[499]
    DIRECTION OUTPUT ;
    USE SIGNAL ;
    PORT
      LAYER M4 ;
        RECT  21.516 17.904 21.6 17.928 ;
    END
  END o[499]
  PIN o[49]
    DIRECTION OUTPUT ;
    USE SIGNAL ;
    PORT
      LAYER M4 ;
        RECT  21.516 27.696 21.6 27.72 ;
    END
  END o[49]
  PIN o[4]
    DIRECTION OUTPUT ;
    USE SIGNAL ;
    PORT
      LAYER M4 ;
        RECT  21.516 20.304 21.6 20.328 ;
    END
  END o[4]
  PIN o[500]
    DIRECTION OUTPUT ;
    USE SIGNAL ;
    PORT
      LAYER M4 ;
        RECT  21.516 18 21.6 18.024 ;
    END
  END o[500]
  PIN o[501]
    DIRECTION OUTPUT ;
    USE SIGNAL ;
    PORT
      LAYER M4 ;
        RECT  21.516 18.096 21.6 18.12 ;
    END
  END o[501]
  PIN o[502]
    DIRECTION OUTPUT ;
    USE SIGNAL ;
    PORT
      LAYER M4 ;
        RECT  21.516 18.192 21.6 18.216 ;
    END
  END o[502]
  PIN o[503]
    DIRECTION OUTPUT ;
    USE SIGNAL ;
    PORT
      LAYER M4 ;
        RECT  21.516 18.288 21.6 18.312 ;
    END
  END o[503]
  PIN o[504]
    DIRECTION OUTPUT ;
    USE SIGNAL ;
    PORT
      LAYER M4 ;
        RECT  21.516 18.384 21.6 18.408 ;
    END
  END o[504]
  PIN o[505]
    DIRECTION OUTPUT ;
    USE SIGNAL ;
    PORT
      LAYER M4 ;
        RECT  21.516 18.48 21.6 18.504 ;
    END
  END o[505]
  PIN o[506]
    DIRECTION OUTPUT ;
    USE SIGNAL ;
    PORT
      LAYER M4 ;
        RECT  21.516 18.576 21.6 18.6 ;
    END
  END o[506]
  PIN o[507]
    DIRECTION OUTPUT ;
    USE SIGNAL ;
    PORT
      LAYER M4 ;
        RECT  21.516 18.672 21.6 18.696 ;
    END
  END o[507]
  PIN o[508]
    DIRECTION OUTPUT ;
    USE SIGNAL ;
    PORT
      LAYER M4 ;
        RECT  21.516 18.768 21.6 18.792 ;
    END
  END o[508]
  PIN o[509]
    DIRECTION OUTPUT ;
    USE SIGNAL ;
    PORT
      LAYER M4 ;
        RECT  21.516 18.864 21.6 18.888 ;
    END
  END o[509]
  PIN o[50]
    DIRECTION OUTPUT ;
    USE SIGNAL ;
    PORT
      LAYER M4 ;
        RECT  21.516 27.792 21.6 27.816 ;
    END
  END o[50]
  PIN o[510]
    DIRECTION OUTPUT ;
    USE SIGNAL ;
    PORT
      LAYER M4 ;
        RECT  21.516 18.96 21.6 18.984 ;
    END
  END o[510]
  PIN o[511]
    DIRECTION OUTPUT ;
    USE SIGNAL ;
    PORT
      LAYER M4 ;
        RECT  21.516 19.056 21.6 19.08 ;
    END
  END o[511]
  PIN o[512]
    DIRECTION OUTPUT ;
    USE SIGNAL ;
    PORT
      LAYER M4 ;
        RECT  21.516 0.72 21.6 0.744 ;
    END
  END o[512]
  PIN o[513]
    DIRECTION OUTPUT ;
    USE SIGNAL ;
    PORT
      LAYER M4 ;
        RECT  21.516 0.816 21.6 0.84 ;
    END
  END o[513]
  PIN o[514]
    DIRECTION OUTPUT ;
    USE SIGNAL ;
    PORT
      LAYER M4 ;
        RECT  21.516 0.912 21.6 0.936 ;
    END
  END o[514]
  PIN o[515]
    DIRECTION OUTPUT ;
    USE SIGNAL ;
    PORT
      LAYER M4 ;
        RECT  21.516 1.008 21.6 1.032 ;
    END
  END o[515]
  PIN o[516]
    DIRECTION OUTPUT ;
    USE SIGNAL ;
    PORT
      LAYER M4 ;
        RECT  21.516 1.104 21.6 1.128 ;
    END
  END o[516]
  PIN o[517]
    DIRECTION OUTPUT ;
    USE SIGNAL ;
    PORT
      LAYER M4 ;
        RECT  21.516 1.2 21.6 1.224 ;
    END
  END o[517]
  PIN o[518]
    DIRECTION OUTPUT ;
    USE SIGNAL ;
    PORT
      LAYER M4 ;
        RECT  21.516 1.296 21.6 1.32 ;
    END
  END o[518]
  PIN o[519]
    DIRECTION OUTPUT ;
    USE SIGNAL ;
    PORT
      LAYER M4 ;
        RECT  21.516 1.392 21.6 1.416 ;
    END
  END o[519]
  PIN o[51]
    DIRECTION OUTPUT ;
    USE SIGNAL ;
    PORT
      LAYER M4 ;
        RECT  21.516 27.888 21.6 27.912 ;
    END
  END o[51]
  PIN o[520]
    DIRECTION OUTPUT ;
    USE SIGNAL ;
    PORT
      LAYER M4 ;
        RECT  21.516 1.488 21.6 1.512 ;
    END
  END o[520]
  PIN o[521]
    DIRECTION OUTPUT ;
    USE SIGNAL ;
    PORT
      LAYER M4 ;
        RECT  21.516 1.584 21.6 1.608 ;
    END
  END o[521]
  PIN o[522]
    DIRECTION OUTPUT ;
    USE SIGNAL ;
    PORT
      LAYER M4 ;
        RECT  21.516 1.68 21.6 1.704 ;
    END
  END o[522]
  PIN o[523]
    DIRECTION OUTPUT ;
    USE SIGNAL ;
    PORT
      LAYER M4 ;
        RECT  21.516 1.776 21.6 1.8 ;
    END
  END o[523]
  PIN o[524]
    DIRECTION OUTPUT ;
    USE SIGNAL ;
    PORT
      LAYER M4 ;
        RECT  21.516 1.872 21.6 1.896 ;
    END
  END o[524]
  PIN o[525]
    DIRECTION OUTPUT ;
    USE SIGNAL ;
    PORT
      LAYER M4 ;
        RECT  21.516 1.968 21.6 1.992 ;
    END
  END o[525]
  PIN o[526]
    DIRECTION OUTPUT ;
    USE SIGNAL ;
    PORT
      LAYER M4 ;
        RECT  21.516 2.064 21.6 2.088 ;
    END
  END o[526]
  PIN o[527]
    DIRECTION OUTPUT ;
    USE SIGNAL ;
    PORT
      LAYER M4 ;
        RECT  21.516 2.16 21.6 2.184 ;
    END
  END o[527]
  PIN o[528]
    DIRECTION OUTPUT ;
    USE SIGNAL ;
    PORT
      LAYER M4 ;
        RECT  21.516 2.256 21.6 2.28 ;
    END
  END o[528]
  PIN o[529]
    DIRECTION OUTPUT ;
    USE SIGNAL ;
    PORT
      LAYER M4 ;
        RECT  21.516 2.352 21.6 2.376 ;
    END
  END o[529]
  PIN o[52]
    DIRECTION OUTPUT ;
    USE SIGNAL ;
    PORT
      LAYER M4 ;
        RECT  21.516 27.984 21.6 28.008 ;
    END
  END o[52]
  PIN o[530]
    DIRECTION OUTPUT ;
    USE SIGNAL ;
    PORT
      LAYER M4 ;
        RECT  21.516 2.448 21.6 2.472 ;
    END
  END o[530]
  PIN o[531]
    DIRECTION OUTPUT ;
    USE SIGNAL ;
    PORT
      LAYER M4 ;
        RECT  21.516 2.544 21.6 2.568 ;
    END
  END o[531]
  PIN o[532]
    DIRECTION OUTPUT ;
    USE SIGNAL ;
    PORT
      LAYER M4 ;
        RECT  21.516 2.64 21.6 2.664 ;
    END
  END o[532]
  PIN o[533]
    DIRECTION OUTPUT ;
    USE SIGNAL ;
    PORT
      LAYER M4 ;
        RECT  21.516 2.736 21.6 2.76 ;
    END
  END o[533]
  PIN o[534]
    DIRECTION OUTPUT ;
    USE SIGNAL ;
    PORT
      LAYER M4 ;
        RECT  21.516 2.832 21.6 2.856 ;
    END
  END o[534]
  PIN o[535]
    DIRECTION OUTPUT ;
    USE SIGNAL ;
    PORT
      LAYER M4 ;
        RECT  21.516 2.928 21.6 2.952 ;
    END
  END o[535]
  PIN o[536]
    DIRECTION OUTPUT ;
    USE SIGNAL ;
    PORT
      LAYER M4 ;
        RECT  21.516 3.024 21.6 3.048 ;
    END
  END o[536]
  PIN o[537]
    DIRECTION OUTPUT ;
    USE SIGNAL ;
    PORT
      LAYER M4 ;
        RECT  21.516 3.12 21.6 3.144 ;
    END
  END o[537]
  PIN o[538]
    DIRECTION OUTPUT ;
    USE SIGNAL ;
    PORT
      LAYER M4 ;
        RECT  21.516 3.216 21.6 3.24 ;
    END
  END o[538]
  PIN o[539]
    DIRECTION OUTPUT ;
    USE SIGNAL ;
    PORT
      LAYER M4 ;
        RECT  21.516 3.312 21.6 3.336 ;
    END
  END o[539]
  PIN o[53]
    DIRECTION OUTPUT ;
    USE SIGNAL ;
    PORT
      LAYER M4 ;
        RECT  21.516 28.08 21.6 28.104 ;
    END
  END o[53]
  PIN o[540]
    DIRECTION OUTPUT ;
    USE SIGNAL ;
    PORT
      LAYER M4 ;
        RECT  21.516 3.408 21.6 3.432 ;
    END
  END o[540]
  PIN o[541]
    DIRECTION OUTPUT ;
    USE SIGNAL ;
    PORT
      LAYER M4 ;
        RECT  21.516 3.504 21.6 3.528 ;
    END
  END o[541]
  PIN o[542]
    DIRECTION OUTPUT ;
    USE SIGNAL ;
    PORT
      LAYER M4 ;
        RECT  21.516 3.6 21.6 3.624 ;
    END
  END o[542]
  PIN o[543]
    DIRECTION OUTPUT ;
    USE SIGNAL ;
    PORT
      LAYER M4 ;
        RECT  21.516 3.696 21.6 3.72 ;
    END
  END o[543]
  PIN o[544]
    DIRECTION OUTPUT ;
    USE SIGNAL ;
    PORT
      LAYER M4 ;
        RECT  21.516 13.008 21.6 13.032 ;
    END
  END o[544]
  PIN o[545]
    DIRECTION OUTPUT ;
    USE SIGNAL ;
    PORT
      LAYER M4 ;
        RECT  21.516 13.104 21.6 13.128 ;
    END
  END o[545]
  PIN o[546]
    DIRECTION OUTPUT ;
    USE SIGNAL ;
    PORT
      LAYER M4 ;
        RECT  21.516 13.2 21.6 13.224 ;
    END
  END o[546]
  PIN o[547]
    DIRECTION OUTPUT ;
    USE SIGNAL ;
    PORT
      LAYER M4 ;
        RECT  21.516 13.296 21.6 13.32 ;
    END
  END o[547]
  PIN o[548]
    DIRECTION OUTPUT ;
    USE SIGNAL ;
    PORT
      LAYER M4 ;
        RECT  21.516 13.392 21.6 13.416 ;
    END
  END o[548]
  PIN o[549]
    DIRECTION OUTPUT ;
    USE SIGNAL ;
    PORT
      LAYER M4 ;
        RECT  21.516 13.488 21.6 13.512 ;
    END
  END o[549]
  PIN o[54]
    DIRECTION OUTPUT ;
    USE SIGNAL ;
    PORT
      LAYER M4 ;
        RECT  21.516 28.176 21.6 28.2 ;
    END
  END o[54]
  PIN o[550]
    DIRECTION OUTPUT ;
    USE SIGNAL ;
    PORT
      LAYER M4 ;
        RECT  21.516 13.584 21.6 13.608 ;
    END
  END o[550]
  PIN o[551]
    DIRECTION OUTPUT ;
    USE SIGNAL ;
    PORT
      LAYER M4 ;
        RECT  21.516 13.68 21.6 13.704 ;
    END
  END o[551]
  PIN o[552]
    DIRECTION OUTPUT ;
    USE SIGNAL ;
    PORT
      LAYER M4 ;
        RECT  21.516 13.776 21.6 13.8 ;
    END
  END o[552]
  PIN o[553]
    DIRECTION OUTPUT ;
    USE SIGNAL ;
    PORT
      LAYER M4 ;
        RECT  21.516 13.872 21.6 13.896 ;
    END
  END o[553]
  PIN o[554]
    DIRECTION OUTPUT ;
    USE SIGNAL ;
    PORT
      LAYER M4 ;
        RECT  21.516 13.968 21.6 13.992 ;
    END
  END o[554]
  PIN o[555]
    DIRECTION OUTPUT ;
    USE SIGNAL ;
    PORT
      LAYER M4 ;
        RECT  21.516 14.064 21.6 14.088 ;
    END
  END o[555]
  PIN o[556]
    DIRECTION OUTPUT ;
    USE SIGNAL ;
    PORT
      LAYER M4 ;
        RECT  21.516 14.16 21.6 14.184 ;
    END
  END o[556]
  PIN o[557]
    DIRECTION OUTPUT ;
    USE SIGNAL ;
    PORT
      LAYER M4 ;
        RECT  21.516 14.256 21.6 14.28 ;
    END
  END o[557]
  PIN o[558]
    DIRECTION OUTPUT ;
    USE SIGNAL ;
    PORT
      LAYER M4 ;
        RECT  21.516 14.352 21.6 14.376 ;
    END
  END o[558]
  PIN o[559]
    DIRECTION OUTPUT ;
    USE SIGNAL ;
    PORT
      LAYER M4 ;
        RECT  21.516 14.448 21.6 14.472 ;
    END
  END o[559]
  PIN o[55]
    DIRECTION OUTPUT ;
    USE SIGNAL ;
    PORT
      LAYER M4 ;
        RECT  21.516 28.272 21.6 28.296 ;
    END
  END o[55]
  PIN o[560]
    DIRECTION OUTPUT ;
    USE SIGNAL ;
    PORT
      LAYER M4 ;
        RECT  21.516 14.544 21.6 14.568 ;
    END
  END o[560]
  PIN o[561]
    DIRECTION OUTPUT ;
    USE SIGNAL ;
    PORT
      LAYER M4 ;
        RECT  21.516 14.64 21.6 14.664 ;
    END
  END o[561]
  PIN o[562]
    DIRECTION OUTPUT ;
    USE SIGNAL ;
    PORT
      LAYER M4 ;
        RECT  21.516 14.736 21.6 14.76 ;
    END
  END o[562]
  PIN o[563]
    DIRECTION OUTPUT ;
    USE SIGNAL ;
    PORT
      LAYER M4 ;
        RECT  21.516 14.832 21.6 14.856 ;
    END
  END o[563]
  PIN o[564]
    DIRECTION OUTPUT ;
    USE SIGNAL ;
    PORT
      LAYER M4 ;
        RECT  21.516 14.928 21.6 14.952 ;
    END
  END o[564]
  PIN o[565]
    DIRECTION OUTPUT ;
    USE SIGNAL ;
    PORT
      LAYER M4 ;
        RECT  21.516 15.024 21.6 15.048 ;
    END
  END o[565]
  PIN o[566]
    DIRECTION OUTPUT ;
    USE SIGNAL ;
    PORT
      LAYER M4 ;
        RECT  21.516 15.12 21.6 15.144 ;
    END
  END o[566]
  PIN o[567]
    DIRECTION OUTPUT ;
    USE SIGNAL ;
    PORT
      LAYER M4 ;
        RECT  21.516 15.216 21.6 15.24 ;
    END
  END o[567]
  PIN o[568]
    DIRECTION OUTPUT ;
    USE SIGNAL ;
    PORT
      LAYER M4 ;
        RECT  21.516 15.312 21.6 15.336 ;
    END
  END o[568]
  PIN o[569]
    DIRECTION OUTPUT ;
    USE SIGNAL ;
    PORT
      LAYER M4 ;
        RECT  21.516 15.408 21.6 15.432 ;
    END
  END o[569]
  PIN o[56]
    DIRECTION OUTPUT ;
    USE SIGNAL ;
    PORT
      LAYER M4 ;
        RECT  21.516 28.368 21.6 28.392 ;
    END
  END o[56]
  PIN o[570]
    DIRECTION OUTPUT ;
    USE SIGNAL ;
    PORT
      LAYER M4 ;
        RECT  21.516 15.504 21.6 15.528 ;
    END
  END o[570]
  PIN o[571]
    DIRECTION OUTPUT ;
    USE SIGNAL ;
    PORT
      LAYER M4 ;
        RECT  21.516 15.6 21.6 15.624 ;
    END
  END o[571]
  PIN o[572]
    DIRECTION OUTPUT ;
    USE SIGNAL ;
    PORT
      LAYER M4 ;
        RECT  21.516 15.696 21.6 15.72 ;
    END
  END o[572]
  PIN o[573]
    DIRECTION OUTPUT ;
    USE SIGNAL ;
    PORT
      LAYER M4 ;
        RECT  21.516 15.792 21.6 15.816 ;
    END
  END o[573]
  PIN o[574]
    DIRECTION OUTPUT ;
    USE SIGNAL ;
    PORT
      LAYER M4 ;
        RECT  21.516 15.888 21.6 15.912 ;
    END
  END o[574]
  PIN o[575]
    DIRECTION OUTPUT ;
    USE SIGNAL ;
    PORT
      LAYER M4 ;
        RECT  21.516 15.984 21.6 16.008 ;
    END
  END o[575]
  PIN o[576]
    DIRECTION OUTPUT ;
    USE SIGNAL ;
    PORT
      LAYER M4 ;
        RECT  21.516 9.936 21.6 9.96 ;
    END
  END o[576]
  PIN o[577]
    DIRECTION OUTPUT ;
    USE SIGNAL ;
    PORT
      LAYER M4 ;
        RECT  21.516 10.032 21.6 10.056 ;
    END
  END o[577]
  PIN o[578]
    DIRECTION OUTPUT ;
    USE SIGNAL ;
    PORT
      LAYER M4 ;
        RECT  21.516 10.128 21.6 10.152 ;
    END
  END o[578]
  PIN o[579]
    DIRECTION OUTPUT ;
    USE SIGNAL ;
    PORT
      LAYER M4 ;
        RECT  21.516 10.224 21.6 10.248 ;
    END
  END o[579]
  PIN o[57]
    DIRECTION OUTPUT ;
    USE SIGNAL ;
    PORT
      LAYER M4 ;
        RECT  21.516 28.464 21.6 28.488 ;
    END
  END o[57]
  PIN o[580]
    DIRECTION OUTPUT ;
    USE SIGNAL ;
    PORT
      LAYER M4 ;
        RECT  21.516 10.32 21.6 10.344 ;
    END
  END o[580]
  PIN o[581]
    DIRECTION OUTPUT ;
    USE SIGNAL ;
    PORT
      LAYER M4 ;
        RECT  21.516 10.416 21.6 10.44 ;
    END
  END o[581]
  PIN o[582]
    DIRECTION OUTPUT ;
    USE SIGNAL ;
    PORT
      LAYER M4 ;
        RECT  21.516 10.512 21.6 10.536 ;
    END
  END o[582]
  PIN o[583]
    DIRECTION OUTPUT ;
    USE SIGNAL ;
    PORT
      LAYER M4 ;
        RECT  21.516 10.608 21.6 10.632 ;
    END
  END o[583]
  PIN o[584]
    DIRECTION OUTPUT ;
    USE SIGNAL ;
    PORT
      LAYER M4 ;
        RECT  21.516 10.704 21.6 10.728 ;
    END
  END o[584]
  PIN o[585]
    DIRECTION OUTPUT ;
    USE SIGNAL ;
    PORT
      LAYER M4 ;
        RECT  21.516 10.8 21.6 10.824 ;
    END
  END o[585]
  PIN o[586]
    DIRECTION OUTPUT ;
    USE SIGNAL ;
    PORT
      LAYER M4 ;
        RECT  21.516 10.896 21.6 10.92 ;
    END
  END o[586]
  PIN o[587]
    DIRECTION OUTPUT ;
    USE SIGNAL ;
    PORT
      LAYER M4 ;
        RECT  21.516 10.992 21.6 11.016 ;
    END
  END o[587]
  PIN o[588]
    DIRECTION OUTPUT ;
    USE SIGNAL ;
    PORT
      LAYER M4 ;
        RECT  21.516 11.088 21.6 11.112 ;
    END
  END o[588]
  PIN o[589]
    DIRECTION OUTPUT ;
    USE SIGNAL ;
    PORT
      LAYER M4 ;
        RECT  21.516 11.184 21.6 11.208 ;
    END
  END o[589]
  PIN o[58]
    DIRECTION OUTPUT ;
    USE SIGNAL ;
    PORT
      LAYER M4 ;
        RECT  21.516 28.56 21.6 28.584 ;
    END
  END o[58]
  PIN o[590]
    DIRECTION OUTPUT ;
    USE SIGNAL ;
    PORT
      LAYER M4 ;
        RECT  21.516 11.28 21.6 11.304 ;
    END
  END o[590]
  PIN o[591]
    DIRECTION OUTPUT ;
    USE SIGNAL ;
    PORT
      LAYER M4 ;
        RECT  21.516 11.376 21.6 11.4 ;
    END
  END o[591]
  PIN o[592]
    DIRECTION OUTPUT ;
    USE SIGNAL ;
    PORT
      LAYER M4 ;
        RECT  21.516 11.472 21.6 11.496 ;
    END
  END o[592]
  PIN o[593]
    DIRECTION OUTPUT ;
    USE SIGNAL ;
    PORT
      LAYER M4 ;
        RECT  21.516 11.568 21.6 11.592 ;
    END
  END o[593]
  PIN o[594]
    DIRECTION OUTPUT ;
    USE SIGNAL ;
    PORT
      LAYER M4 ;
        RECT  21.516 11.664 21.6 11.688 ;
    END
  END o[594]
  PIN o[595]
    DIRECTION OUTPUT ;
    USE SIGNAL ;
    PORT
      LAYER M4 ;
        RECT  21.516 11.76 21.6 11.784 ;
    END
  END o[595]
  PIN o[596]
    DIRECTION OUTPUT ;
    USE SIGNAL ;
    PORT
      LAYER M4 ;
        RECT  21.516 11.856 21.6 11.88 ;
    END
  END o[596]
  PIN o[597]
    DIRECTION OUTPUT ;
    USE SIGNAL ;
    PORT
      LAYER M4 ;
        RECT  21.516 11.952 21.6 11.976 ;
    END
  END o[597]
  PIN o[598]
    DIRECTION OUTPUT ;
    USE SIGNAL ;
    PORT
      LAYER M4 ;
        RECT  21.516 12.048 21.6 12.072 ;
    END
  END o[598]
  PIN o[599]
    DIRECTION OUTPUT ;
    USE SIGNAL ;
    PORT
      LAYER M4 ;
        RECT  21.516 12.144 21.6 12.168 ;
    END
  END o[599]
  PIN o[59]
    DIRECTION OUTPUT ;
    USE SIGNAL ;
    PORT
      LAYER M4 ;
        RECT  21.516 28.656 21.6 28.68 ;
    END
  END o[59]
  PIN o[5]
    DIRECTION OUTPUT ;
    USE SIGNAL ;
    PORT
      LAYER M4 ;
        RECT  21.516 20.4 21.6 20.424 ;
    END
  END o[5]
  PIN o[600]
    DIRECTION OUTPUT ;
    USE SIGNAL ;
    PORT
      LAYER M4 ;
        RECT  21.516 12.24 21.6 12.264 ;
    END
  END o[600]
  PIN o[601]
    DIRECTION OUTPUT ;
    USE SIGNAL ;
    PORT
      LAYER M4 ;
        RECT  21.516 12.336 21.6 12.36 ;
    END
  END o[601]
  PIN o[602]
    DIRECTION OUTPUT ;
    USE SIGNAL ;
    PORT
      LAYER M4 ;
        RECT  21.516 12.432 21.6 12.456 ;
    END
  END o[602]
  PIN o[603]
    DIRECTION OUTPUT ;
    USE SIGNAL ;
    PORT
      LAYER M4 ;
        RECT  21.516 12.528 21.6 12.552 ;
    END
  END o[603]
  PIN o[604]
    DIRECTION OUTPUT ;
    USE SIGNAL ;
    PORT
      LAYER M4 ;
        RECT  21.516 12.624 21.6 12.648 ;
    END
  END o[604]
  PIN o[605]
    DIRECTION OUTPUT ;
    USE SIGNAL ;
    PORT
      LAYER M4 ;
        RECT  21.516 12.72 21.6 12.744 ;
    END
  END o[605]
  PIN o[606]
    DIRECTION OUTPUT ;
    USE SIGNAL ;
    PORT
      LAYER M4 ;
        RECT  21.516 12.816 21.6 12.84 ;
    END
  END o[606]
  PIN o[607]
    DIRECTION OUTPUT ;
    USE SIGNAL ;
    PORT
      LAYER M4 ;
        RECT  21.516 12.912 21.6 12.936 ;
    END
  END o[607]
  PIN o[608]
    DIRECTION OUTPUT ;
    USE SIGNAL ;
    PORT
      LAYER M4 ;
        RECT  21.516 61.392 21.6 61.416 ;
    END
  END o[608]
  PIN o[609]
    DIRECTION OUTPUT ;
    USE SIGNAL ;
    PORT
      LAYER M4 ;
        RECT  21.516 61.488 21.6 61.512 ;
    END
  END o[609]
  PIN o[60]
    DIRECTION OUTPUT ;
    USE SIGNAL ;
    PORT
      LAYER M4 ;
        RECT  21.516 28.752 21.6 28.776 ;
    END
  END o[60]
  PIN o[610]
    DIRECTION OUTPUT ;
    USE SIGNAL ;
    PORT
      LAYER M4 ;
        RECT  21.516 61.584 21.6 61.608 ;
    END
  END o[610]
  PIN o[611]
    DIRECTION OUTPUT ;
    USE SIGNAL ;
    PORT
      LAYER M4 ;
        RECT  21.516 61.68 21.6 61.704 ;
    END
  END o[611]
  PIN o[612]
    DIRECTION OUTPUT ;
    USE SIGNAL ;
    PORT
      LAYER M4 ;
        RECT  21.516 61.776 21.6 61.8 ;
    END
  END o[612]
  PIN o[613]
    DIRECTION OUTPUT ;
    USE SIGNAL ;
    PORT
      LAYER M4 ;
        RECT  21.516 61.872 21.6 61.896 ;
    END
  END o[613]
  PIN o[614]
    DIRECTION OUTPUT ;
    USE SIGNAL ;
    PORT
      LAYER M4 ;
        RECT  21.516 61.968 21.6 61.992 ;
    END
  END o[614]
  PIN o[615]
    DIRECTION OUTPUT ;
    USE SIGNAL ;
    PORT
      LAYER M4 ;
        RECT  21.516 62.064 21.6 62.088 ;
    END
  END o[615]
  PIN o[616]
    DIRECTION OUTPUT ;
    USE SIGNAL ;
    PORT
      LAYER M4 ;
        RECT  21.516 62.16 21.6 62.184 ;
    END
  END o[616]
  PIN o[617]
    DIRECTION OUTPUT ;
    USE SIGNAL ;
    PORT
      LAYER M4 ;
        RECT  21.516 62.256 21.6 62.28 ;
    END
  END o[617]
  PIN o[618]
    DIRECTION OUTPUT ;
    USE SIGNAL ;
    PORT
      LAYER M4 ;
        RECT  21.516 62.352 21.6 62.376 ;
    END
  END o[618]
  PIN o[619]
    DIRECTION OUTPUT ;
    USE SIGNAL ;
    PORT
      LAYER M4 ;
        RECT  21.516 62.448 21.6 62.472 ;
    END
  END o[619]
  PIN o[61]
    DIRECTION OUTPUT ;
    USE SIGNAL ;
    PORT
      LAYER M4 ;
        RECT  21.516 28.848 21.6 28.872 ;
    END
  END o[61]
  PIN o[620]
    DIRECTION OUTPUT ;
    USE SIGNAL ;
    PORT
      LAYER M4 ;
        RECT  21.516 62.544 21.6 62.568 ;
    END
  END o[620]
  PIN o[621]
    DIRECTION OUTPUT ;
    USE SIGNAL ;
    PORT
      LAYER M4 ;
        RECT  21.516 62.64 21.6 62.664 ;
    END
  END o[621]
  PIN o[622]
    DIRECTION OUTPUT ;
    USE SIGNAL ;
    PORT
      LAYER M4 ;
        RECT  21.516 62.736 21.6 62.76 ;
    END
  END o[622]
  PIN o[623]
    DIRECTION OUTPUT ;
    USE SIGNAL ;
    PORT
      LAYER M4 ;
        RECT  21.516 62.832 21.6 62.856 ;
    END
  END o[623]
  PIN o[62]
    DIRECTION OUTPUT ;
    USE SIGNAL ;
    PORT
      LAYER M4 ;
        RECT  21.516 28.944 21.6 28.968 ;
    END
  END o[62]
  PIN o[63]
    DIRECTION OUTPUT ;
    USE SIGNAL ;
    PORT
      LAYER M4 ;
        RECT  21.516 29.04 21.6 29.064 ;
    END
  END o[63]
  PIN o[64]
    DIRECTION OUTPUT ;
    USE SIGNAL ;
    PORT
      LAYER M4 ;
        RECT  21.516 29.136 21.6 29.16 ;
    END
  END o[64]
  PIN o[65]
    DIRECTION OUTPUT ;
    USE SIGNAL ;
    PORT
      LAYER M4 ;
        RECT  21.516 29.232 21.6 29.256 ;
    END
  END o[65]
  PIN o[66]
    DIRECTION OUTPUT ;
    USE SIGNAL ;
    PORT
      LAYER M4 ;
        RECT  21.516 29.328 21.6 29.352 ;
    END
  END o[66]
  PIN o[67]
    DIRECTION OUTPUT ;
    USE SIGNAL ;
    PORT
      LAYER M4 ;
        RECT  21.516 29.424 21.6 29.448 ;
    END
  END o[67]
  PIN o[68]
    DIRECTION OUTPUT ;
    USE SIGNAL ;
    PORT
      LAYER M4 ;
        RECT  21.516 29.52 21.6 29.544 ;
    END
  END o[68]
  PIN o[69]
    DIRECTION OUTPUT ;
    USE SIGNAL ;
    PORT
      LAYER M4 ;
        RECT  21.516 29.616 21.6 29.64 ;
    END
  END o[69]
  PIN o[6]
    DIRECTION OUTPUT ;
    USE SIGNAL ;
    PORT
      LAYER M4 ;
        RECT  21.516 20.496 21.6 20.52 ;
    END
  END o[6]
  PIN o[70]
    DIRECTION OUTPUT ;
    USE SIGNAL ;
    PORT
      LAYER M4 ;
        RECT  21.516 29.712 21.6 29.736 ;
    END
  END o[70]
  PIN o[71]
    DIRECTION OUTPUT ;
    USE SIGNAL ;
    PORT
      LAYER M4 ;
        RECT  21.516 29.808 21.6 29.832 ;
    END
  END o[71]
  PIN o[72]
    DIRECTION OUTPUT ;
    USE SIGNAL ;
    PORT
      LAYER M4 ;
        RECT  21.516 29.904 21.6 29.928 ;
    END
  END o[72]
  PIN o[73]
    DIRECTION OUTPUT ;
    USE SIGNAL ;
    PORT
      LAYER M4 ;
        RECT  21.516 30 21.6 30.024 ;
    END
  END o[73]
  PIN o[74]
    DIRECTION OUTPUT ;
    USE SIGNAL ;
    PORT
      LAYER M4 ;
        RECT  21.516 30.096 21.6 30.12 ;
    END
  END o[74]
  PIN o[75]
    DIRECTION OUTPUT ;
    USE SIGNAL ;
    PORT
      LAYER M4 ;
        RECT  21.516 30.192 21.6 30.216 ;
    END
  END o[75]
  PIN o[76]
    DIRECTION OUTPUT ;
    USE SIGNAL ;
    PORT
      LAYER M4 ;
        RECT  21.516 30.288 21.6 30.312 ;
    END
  END o[76]
  PIN o[77]
    DIRECTION OUTPUT ;
    USE SIGNAL ;
    PORT
      LAYER M4 ;
        RECT  21.516 30.384 21.6 30.408 ;
    END
  END o[77]
  PIN o[78]
    DIRECTION OUTPUT ;
    USE SIGNAL ;
    PORT
      LAYER M4 ;
        RECT  21.516 30.48 21.6 30.504 ;
    END
  END o[78]
  PIN o[79]
    DIRECTION OUTPUT ;
    USE SIGNAL ;
    PORT
      LAYER M4 ;
        RECT  21.516 30.576 21.6 30.6 ;
    END
  END o[79]
  PIN o[7]
    DIRECTION OUTPUT ;
    USE SIGNAL ;
    PORT
      LAYER M4 ;
        RECT  21.516 20.592 21.6 20.616 ;
    END
  END o[7]
  PIN o[80]
    DIRECTION OUTPUT ;
    USE SIGNAL ;
    PORT
      LAYER M4 ;
        RECT  21.516 30.672 21.6 30.696 ;
    END
  END o[80]
  PIN o[81]
    DIRECTION OUTPUT ;
    USE SIGNAL ;
    PORT
      LAYER M4 ;
        RECT  21.516 30.768 21.6 30.792 ;
    END
  END o[81]
  PIN o[82]
    DIRECTION OUTPUT ;
    USE SIGNAL ;
    PORT
      LAYER M4 ;
        RECT  21.516 30.864 21.6 30.888 ;
    END
  END o[82]
  PIN o[83]
    DIRECTION OUTPUT ;
    USE SIGNAL ;
    PORT
      LAYER M4 ;
        RECT  21.516 30.96 21.6 30.984 ;
    END
  END o[83]
  PIN o[84]
    DIRECTION OUTPUT ;
    USE SIGNAL ;
    PORT
      LAYER M4 ;
        RECT  21.516 31.056 21.6 31.08 ;
    END
  END o[84]
  PIN o[85]
    DIRECTION OUTPUT ;
    USE SIGNAL ;
    PORT
      LAYER M4 ;
        RECT  21.516 31.152 21.6 31.176 ;
    END
  END o[85]
  PIN o[86]
    DIRECTION OUTPUT ;
    USE SIGNAL ;
    PORT
      LAYER M4 ;
        RECT  21.516 31.248 21.6 31.272 ;
    END
  END o[86]
  PIN o[87]
    DIRECTION OUTPUT ;
    USE SIGNAL ;
    PORT
      LAYER M4 ;
        RECT  21.516 31.344 21.6 31.368 ;
    END
  END o[87]
  PIN o[88]
    DIRECTION OUTPUT ;
    USE SIGNAL ;
    PORT
      LAYER M4 ;
        RECT  21.516 31.44 21.6 31.464 ;
    END
  END o[88]
  PIN o[89]
    DIRECTION OUTPUT ;
    USE SIGNAL ;
    PORT
      LAYER M4 ;
        RECT  21.516 31.536 21.6 31.56 ;
    END
  END o[89]
  PIN o[8]
    DIRECTION OUTPUT ;
    USE SIGNAL ;
    PORT
      LAYER M4 ;
        RECT  21.516 20.688 21.6 20.712 ;
    END
  END o[8]
  PIN o[90]
    DIRECTION OUTPUT ;
    USE SIGNAL ;
    PORT
      LAYER M4 ;
        RECT  21.516 31.632 21.6 31.656 ;
    END
  END o[90]
  PIN o[91]
    DIRECTION OUTPUT ;
    USE SIGNAL ;
    PORT
      LAYER M4 ;
        RECT  21.516 31.728 21.6 31.752 ;
    END
  END o[91]
  PIN o[92]
    DIRECTION OUTPUT ;
    USE SIGNAL ;
    PORT
      LAYER M4 ;
        RECT  21.516 31.824 21.6 31.848 ;
    END
  END o[92]
  PIN o[93]
    DIRECTION OUTPUT ;
    USE SIGNAL ;
    PORT
      LAYER M4 ;
        RECT  21.516 31.92 21.6 31.944 ;
    END
  END o[93]
  PIN o[94]
    DIRECTION OUTPUT ;
    USE SIGNAL ;
    PORT
      LAYER M4 ;
        RECT  21.516 32.016 21.6 32.04 ;
    END
  END o[94]
  PIN o[95]
    DIRECTION OUTPUT ;
    USE SIGNAL ;
    PORT
      LAYER M4 ;
        RECT  21.516 32.112 21.6 32.136 ;
    END
  END o[95]
  PIN o[96]
    DIRECTION OUTPUT ;
    USE SIGNAL ;
    PORT
      LAYER M4 ;
        RECT  21.516 35.28 21.6 35.304 ;
    END
  END o[96]
  PIN o[97]
    DIRECTION OUTPUT ;
    USE SIGNAL ;
    PORT
      LAYER M4 ;
        RECT  21.516 35.376 21.6 35.4 ;
    END
  END o[97]
  PIN o[98]
    DIRECTION OUTPUT ;
    USE SIGNAL ;
    PORT
      LAYER M4 ;
        RECT  21.516 35.472 21.6 35.496 ;
    END
  END o[98]
  PIN o[99]
    DIRECTION OUTPUT ;
    USE SIGNAL ;
    PORT
      LAYER M4 ;
        RECT  21.516 35.568 21.6 35.592 ;
    END
  END o[99]
  PIN o[9]
    DIRECTION OUTPUT ;
    USE SIGNAL ;
    PORT
      LAYER M4 ;
        RECT  21.516 20.784 21.6 20.808 ;
    END
  END o[9]
  PIN rs
    DIRECTION INPUT ;
    USE SIGNAL ;
    PORT
      LAYER M5 ;
        RECT  10.8 0 10.824 0.084 ;
    END
  END rs
  PIN VDD
    DIRECTION INOUT ;
    USE POWER ;
    PORT
      LAYER M5 ;
        RECT  18.792 2.151 18.912 62.649 ;
        RECT  16.092 2.151 16.212 62.649 ;
        RECT  13.392 2.151 13.512 62.649 ;
        RECT  10.692 2.151 10.812 62.649 ;
        RECT  7.992 2.151 8.112 62.649 ;
        RECT  5.292 2.151 5.412 62.649 ;
        RECT  2.592 2.151 2.712 62.649 ;
    END
  END VDD
  PIN VSS
    DIRECTION INOUT ;
    USE GROUND ;
    PORT
      LAYER M5 ;
        RECT  18.6 2.137 18.72 62.663 ;
        RECT  15.9 2.137 16.02 62.663 ;
        RECT  13.2 2.137 13.32 62.663 ;
        RECT  10.5 2.137 10.62 62.663 ;
        RECT  7.8 2.137 7.92 62.663 ;
        RECT  5.1 2.137 5.22 62.663 ;
        RECT  2.4 2.137 2.52 62.663 ;
    END
  END VSS
  OBS
    LAYER RVTN ;
     RECT  2.16 2.16 19.44 2.295 ;
     RECT  2.16 2.565 19.44 2.835 ;
     RECT  2.16 3.105 19.44 3.375 ;
     RECT  2.16 3.645 19.44 3.915 ;
     RECT  2.16 4.185 19.44 4.455 ;
     RECT  2.16 4.725 19.44 4.995 ;
     RECT  2.16 5.265 19.44 5.535 ;
     RECT  2.16 5.805 19.44 6.075 ;
     RECT  2.16 6.345 19.44 6.615 ;
     RECT  2.16 6.885 19.44 7.155 ;
     RECT  2.16 7.425 19.44 7.695 ;
     RECT  2.16 7.965 19.44 8.235 ;
     RECT  2.16 8.505 19.44 8.775 ;
     RECT  2.16 9.045 19.44 9.315 ;
     RECT  2.16 9.585 19.44 9.855 ;
     RECT  2.16 10.125 19.44 10.395 ;
     RECT  2.16 10.665 19.44 10.935 ;
     RECT  2.16 11.205 19.44 11.475 ;
     RECT  2.16 11.745 19.44 12.015 ;
     RECT  2.16 12.285 19.44 12.555 ;
     RECT  2.16 12.825 19.44 13.095 ;
     RECT  2.16 13.365 19.44 13.635 ;
     RECT  2.16 13.905 19.44 14.175 ;
     RECT  2.16 14.445 19.44 14.715 ;
     RECT  2.16 14.985 19.44 15.255 ;
     RECT  2.16 15.525 19.44 15.795 ;
     RECT  2.16 16.065 19.44 16.335 ;
     RECT  2.16 16.605 19.44 16.875 ;
     RECT  2.16 17.145 19.44 17.415 ;
     RECT  2.16 17.685 19.44 17.955 ;
     RECT  2.16 18.225 19.44 18.495 ;
     RECT  2.16 18.765 19.44 19.035 ;
     RECT  2.16 19.305 19.44 19.575 ;
     RECT  2.16 19.845 19.44 20.115 ;
     RECT  2.16 20.385 19.44 20.655 ;
     RECT  2.16 20.925 19.44 21.195 ;
     RECT  2.16 21.465 19.44 21.735 ;
     RECT  2.16 22.005 19.44 22.275 ;
     RECT  2.16 22.545 19.44 22.815 ;
     RECT  2.16 23.085 19.44 23.355 ;
     RECT  2.16 23.625 19.44 23.895 ;
     RECT  2.16 24.165 19.44 24.435 ;
     RECT  2.16 24.705 19.44 24.975 ;
     RECT  2.16 25.245 19.44 25.515 ;
     RECT  2.16 25.785 19.44 26.055 ;
     RECT  2.16 26.325 19.44 26.595 ;
     RECT  2.16 26.865 19.44 27.135 ;
     RECT  2.16 27.405 19.44 27.675 ;
     RECT  2.16 27.945 19.44 28.215 ;
     RECT  2.16 28.485 19.44 28.755 ;
     RECT  2.16 29.025 19.44 29.295 ;
     RECT  2.16 29.565 19.44 29.835 ;
     RECT  2.16 30.105 19.44 30.375 ;
     RECT  2.16 30.645 19.44 30.915 ;
     RECT  2.16 31.185 19.44 31.455 ;
     RECT  2.16 31.725 19.44 31.995 ;
     RECT  2.16 32.265 19.44 32.535 ;
     RECT  2.16 32.805 19.44 33.075 ;
     RECT  2.16 33.345 19.44 33.615 ;
     RECT  2.16 33.885 19.44 34.155 ;
     RECT  2.16 34.425 19.44 34.695 ;
     RECT  2.16 34.965 19.44 35.235 ;
     RECT  2.16 35.505 19.44 35.775 ;
     RECT  2.16 36.045 19.44 36.315 ;
     RECT  2.16 36.585 19.44 36.855 ;
     RECT  2.16 37.125 19.44 37.395 ;
     RECT  2.16 37.665 19.44 37.935 ;
     RECT  2.16 38.205 19.44 38.475 ;
     RECT  2.16 38.745 19.44 39.015 ;
     RECT  2.16 39.285 19.44 39.555 ;
     RECT  2.16 39.825 19.44 40.095 ;
     RECT  2.16 40.365 19.44 40.635 ;
     RECT  2.16 40.905 19.44 41.175 ;
     RECT  2.16 41.445 19.44 41.715 ;
     RECT  2.16 41.985 19.44 42.255 ;
     RECT  2.16 42.525 19.44 42.795 ;
     RECT  2.16 43.065 19.44 43.335 ;
     RECT  2.16 43.605 19.44 43.875 ;
     RECT  2.16 44.145 19.44 44.415 ;
     RECT  2.16 44.685 19.44 44.955 ;
     RECT  2.16 45.225 19.44 45.495 ;
     RECT  2.16 45.765 19.44 46.035 ;
     RECT  2.16 46.305 19.44 46.575 ;
     RECT  2.16 46.845 19.44 47.115 ;
     RECT  2.16 47.385 19.44 47.655 ;
     RECT  2.16 47.925 19.44 48.195 ;
     RECT  2.16 48.465 19.44 48.735 ;
     RECT  2.16 49.005 19.44 49.275 ;
     RECT  2.16 49.545 19.44 49.815 ;
     RECT  2.16 50.085 19.44 50.355 ;
     RECT  2.16 50.625 19.44 50.895 ;
     RECT  2.16 51.165 19.44 51.435 ;
     RECT  2.16 51.705 19.44 51.975 ;
     RECT  2.16 52.245 19.44 52.515 ;
     RECT  2.16 52.785 19.44 53.055 ;
     RECT  2.16 53.325 19.44 53.595 ;
     RECT  2.16 53.865 19.44 54.135 ;
     RECT  2.16 54.405 19.44 54.675 ;
     RECT  2.16 54.945 19.44 55.215 ;
     RECT  2.16 55.485 19.44 55.755 ;
     RECT  2.16 56.025 19.44 56.295 ;
     RECT  2.16 56.565 19.44 56.835 ;
     RECT  2.16 57.105 19.44 57.375 ;
     RECT  2.16 57.645 19.44 57.915 ;
     RECT  2.16 58.185 19.44 58.455 ;
     RECT  2.16 58.725 19.44 58.995 ;
     RECT  2.16 59.265 19.44 59.535 ;
     RECT  2.16 59.805 19.44 60.075 ;
     RECT  2.16 60.345 19.44 60.615 ;
     RECT  2.16 60.885 19.44 61.155 ;
     RECT  2.16 61.425 19.44 61.695 ;
     RECT  2.16 61.965 19.44 62.235 ;
     RECT  2.16 62.505 19.44 62.64 ;
    LAYER RVTP ;
     RECT  2.16 2.295 19.44 2.565 ;
     RECT  2.16 2.835 19.44 3.105 ;
     RECT  2.16 3.375 19.44 3.645 ;
     RECT  2.16 3.915 19.44 4.185 ;
     RECT  2.16 4.455 19.44 4.725 ;
     RECT  2.16 4.995 19.44 5.265 ;
     RECT  2.16 5.535 19.44 5.805 ;
     RECT  2.16 6.075 19.44 6.345 ;
     RECT  2.16 6.615 19.44 6.885 ;
     RECT  2.16 7.155 19.44 7.425 ;
     RECT  2.16 7.695 19.44 7.965 ;
     RECT  2.16 8.235 19.44 8.505 ;
     RECT  2.16 8.775 19.44 9.045 ;
     RECT  2.16 9.315 19.44 9.585 ;
     RECT  2.16 9.855 19.44 10.125 ;
     RECT  2.16 10.395 19.44 10.665 ;
     RECT  2.16 10.935 19.44 11.205 ;
     RECT  2.16 11.475 19.44 11.745 ;
     RECT  2.16 12.015 19.44 12.285 ;
     RECT  2.16 12.555 19.44 12.825 ;
     RECT  2.16 13.095 19.44 13.365 ;
     RECT  2.16 13.635 19.44 13.905 ;
     RECT  2.16 14.175 19.44 14.445 ;
     RECT  2.16 14.715 19.44 14.985 ;
     RECT  2.16 15.255 19.44 15.525 ;
     RECT  2.16 15.795 19.44 16.065 ;
     RECT  2.16 16.335 19.44 16.605 ;
     RECT  2.16 16.875 19.44 17.145 ;
     RECT  2.16 17.415 19.44 17.685 ;
     RECT  2.16 17.955 19.44 18.225 ;
     RECT  2.16 18.495 19.44 18.765 ;
     RECT  2.16 19.035 19.44 19.305 ;
     RECT  2.16 19.575 19.44 19.845 ;
     RECT  2.16 20.115 19.44 20.385 ;
     RECT  2.16 20.655 19.44 20.925 ;
     RECT  2.16 21.195 19.44 21.465 ;
     RECT  2.16 21.735 19.44 22.005 ;
     RECT  2.16 22.275 19.44 22.545 ;
     RECT  2.16 22.815 19.44 23.085 ;
     RECT  2.16 23.355 19.44 23.625 ;
     RECT  2.16 23.895 19.44 24.165 ;
     RECT  2.16 24.435 19.44 24.705 ;
     RECT  2.16 24.975 19.44 25.245 ;
     RECT  2.16 25.515 19.44 25.785 ;
     RECT  2.16 26.055 19.44 26.325 ;
     RECT  2.16 26.595 19.44 26.865 ;
     RECT  2.16 27.135 19.44 27.405 ;
     RECT  2.16 27.675 19.44 27.945 ;
     RECT  2.16 28.215 19.44 28.485 ;
     RECT  2.16 28.755 19.44 29.025 ;
     RECT  2.16 29.295 19.44 29.565 ;
     RECT  2.16 29.835 19.44 30.105 ;
     RECT  2.16 30.375 19.44 30.645 ;
     RECT  2.16 30.915 19.44 31.185 ;
     RECT  2.16 31.455 19.44 31.725 ;
     RECT  2.16 31.995 19.44 32.265 ;
     RECT  2.16 32.535 19.44 32.805 ;
     RECT  2.16 33.075 19.44 33.345 ;
     RECT  2.16 33.615 19.44 33.885 ;
     RECT  2.16 34.155 19.44 34.425 ;
     RECT  2.16 34.695 19.44 34.965 ;
     RECT  2.16 35.235 19.44 35.505 ;
     RECT  2.16 35.775 19.44 36.045 ;
     RECT  2.16 36.315 19.44 36.585 ;
     RECT  2.16 36.855 19.44 37.125 ;
     RECT  2.16 37.395 19.44 37.665 ;
     RECT  2.16 37.935 19.44 38.205 ;
     RECT  2.16 38.475 19.44 38.745 ;
     RECT  2.16 39.015 19.44 39.285 ;
     RECT  2.16 39.555 19.44 39.825 ;
     RECT  2.16 40.095 19.44 40.365 ;
     RECT  2.16 40.635 19.44 40.905 ;
     RECT  2.16 41.175 19.44 41.445 ;
     RECT  2.16 41.715 19.44 41.985 ;
     RECT  2.16 42.255 19.44 42.525 ;
     RECT  2.16 42.795 19.44 43.065 ;
     RECT  2.16 43.335 19.44 43.605 ;
     RECT  2.16 43.875 19.44 44.145 ;
     RECT  2.16 44.415 19.44 44.685 ;
     RECT  2.16 44.955 19.44 45.225 ;
     RECT  2.16 45.495 19.44 45.765 ;
     RECT  2.16 46.035 19.44 46.305 ;
     RECT  2.16 46.575 19.44 46.845 ;
     RECT  2.16 47.115 19.44 47.385 ;
     RECT  2.16 47.655 19.44 47.925 ;
     RECT  2.16 48.195 19.44 48.465 ;
     RECT  2.16 48.735 19.44 49.005 ;
     RECT  2.16 49.275 19.44 49.545 ;
     RECT  2.16 49.815 19.44 50.085 ;
     RECT  2.16 50.355 19.44 50.625 ;
     RECT  2.16 50.895 19.44 51.165 ;
     RECT  2.16 51.435 19.44 51.705 ;
     RECT  2.16 51.975 19.44 52.245 ;
     RECT  2.16 52.515 19.44 52.785 ;
     RECT  2.16 53.055 19.44 53.325 ;
     RECT  2.16 53.595 19.44 53.865 ;
     RECT  2.16 54.135 19.44 54.405 ;
     RECT  2.16 54.675 19.44 54.945 ;
     RECT  2.16 55.215 19.44 55.485 ;
     RECT  2.16 55.755 19.44 56.025 ;
     RECT  2.16 56.295 19.44 56.565 ;
     RECT  2.16 56.835 19.44 57.105 ;
     RECT  2.16 57.375 19.44 57.645 ;
     RECT  2.16 57.915 19.44 58.185 ;
     RECT  2.16 58.455 19.44 58.725 ;
     RECT  2.16 58.995 19.44 59.265 ;
     RECT  2.16 59.535 19.44 59.805 ;
     RECT  2.16 60.075 19.44 60.345 ;
     RECT  2.16 60.615 19.44 60.885 ;
     RECT  2.16 61.155 19.44 61.425 ;
     RECT  2.16 61.695 19.44 61.965 ;
     RECT  2.16 62.235 19.44 62.505 ;
    LAYER M1 ;
     RECT  2.16 2.151 19.44 62.649 ;
    LAYER M2 ;
     RECT  0.031 62.712 0.131 62.73 ;
     RECT  0.031 61.398 0.139 61.416 ;
     RECT  0.103 18.198 0.203 18.216 ;
     RECT  0.139 61.398 0.211 62.064 ;
     RECT  0.103 35.244 0.239 35.262 ;
     RECT  0.211 61.128 0.239 62.064 ;
     RECT  0.211 54.756 0.311 54.774 ;
     RECT  0.103 43.731 0.347 43.749 ;
     RECT  0.103 58.698 0.535 58.716 ;
     RECT  0.239 61.128 1.147 61.416 ;
     RECT  1.147 61.128 1.687 61.524 ;
     RECT  0.103 3.312 2.16 3.33 ;
     RECT  0.535 7.362 2.16 7.38 ;
     RECT  0.103 13.644 2.16 13.662 ;
     RECT  0.535 32.814 2.16 32.832 ;
     RECT  0.535 47.394 2.16 47.412 ;
     RECT  0.535 57.996 2.16 58.716 ;
     RECT  1.687 60.966 2.16 61.524 ;
     RECT  2.16 2.151 2.335 62.649 ;
     RECT  2.335 2.106 3.019 62.649 ;
     RECT  3.019 2.034 3.055 62.649 ;
     RECT  3.055 2.034 3.839 62.694 ;
     RECT  3.839 2.151 5.027 62.694 ;
     RECT  5.027 2.151 5.863 62.649 ;
     RECT  5.863 2.151 6.799 62.694 ;
     RECT  6.799 2.106 7.267 62.694 ;
     RECT  7.267 2.034 7.303 62.694 ;
     RECT  7.303 1.998 10.183 62.694 ;
     RECT  10.183 1.998 10.319 62.766 ;
     RECT  10.319 2.034 11.111 62.766 ;
     RECT  11.111 2.07 12.127 62.766 ;
     RECT  12.127 2.07 12.199 62.874 ;
     RECT  12.199 1.998 14.035 62.874 ;
     RECT  14.035 1.962 14.107 62.874 ;
     RECT  14.107 1.836 14.323 62.874 ;
     RECT  14.323 1.728 16.051 62.874 ;
     RECT  16.051 1.728 17.167 62.919 ;
     RECT  17.167 1.692 17.455 62.919 ;
     RECT  17.455 1.611 17.807 62.919 ;
     RECT  17.807 1.728 17.915 62.919 ;
     RECT  17.915 1.764 18.959 62.919 ;
     RECT  18.959 1.998 18.995 62.649 ;
     RECT  18.995 2.07 19.44 62.649 ;
     RECT  19.44 29.304 19.787 62.496 ;
     RECT  19.787 29.304 19.823 55.584 ;
     RECT  19.44 2.07 19.931 2.754 ;
     RECT  19.44 3.546 19.931 17.064 ;
     RECT  19.823 53.676 19.931 55.584 ;
     RECT  19.823 29.304 19.967 52.929 ;
     RECT  19.931 9.216 20.003 17.064 ;
     RECT  19.967 29.304 20.003 52.704 ;
     RECT  20.003 47.124 20.111 52.704 ;
     RECT  20.003 9.216 20.363 11.124 ;
     RECT  20.003 29.304 20.399 46.098 ;
     RECT  19.44 17.856 20.435 28.476 ;
     RECT  20.399 29.304 20.435 38.124 ;
     RECT  20.399 39.186 20.435 46.098 ;
     RECT  20.111 47.124 20.435 51.462 ;
     RECT  20.363 9.216 20.471 10.692 ;
     RECT  20.003 11.916 20.471 17.064 ;
     RECT  20.435 17.856 20.471 26.244 ;
     RECT  20.435 29.304 20.471 37.044 ;
     RECT  20.435 37.836 20.471 38.124 ;
     RECT  20.435 39.636 20.471 46.098 ;
     RECT  19.931 53.676 20.471 54.504 ;
     RECT  19.787 56.34 20.471 62.496 ;
     RECT  19.931 3.546 20.507 8.424 ;
     RECT  20.471 10.566 20.507 10.692 ;
     RECT  20.471 11.916 20.507 11.934 ;
     RECT  20.471 12.798 20.507 17.064 ;
     RECT  20.471 18.126 20.507 25.974 ;
     RECT  20.471 29.304 20.507 34.614 ;
     RECT  20.471 37.836 20.507 37.854 ;
     RECT  20.471 39.636 20.507 41.436 ;
     RECT  20.471 42.606 20.507 46.098 ;
     RECT  20.111 52.218 20.507 52.704 ;
     RECT  20.471 54.486 20.507 54.504 ;
     RECT  19.931 55.26 20.507 55.584 ;
     RECT  20.471 56.34 20.507 61.344 ;
     RECT  20.507 10.674 20.543 10.692 ;
     RECT  20.507 15.876 20.543 17.064 ;
     RECT  20.507 18.126 20.543 24.156 ;
     RECT  20.435 27.036 20.543 28.476 ;
     RECT  20.507 29.304 20.543 29.556 ;
     RECT  20.507 39.636 20.543 41.166 ;
     RECT  20.507 42.606 20.543 45.216 ;
     RECT  20.507 46.08 20.543 46.098 ;
     RECT  20.507 55.26 20.543 55.278 ;
     RECT  20.507 57.546 20.543 60.804 ;
     RECT  20.471 62.208 20.543 62.496 ;
     RECT  20.507 12.798 20.579 14.634 ;
     RECT  20.543 16.308 20.579 17.064 ;
     RECT  20.507 25.146 20.579 25.776 ;
     RECT  20.543 29.538 20.579 29.556 ;
     RECT  20.507 56.34 20.579 56.754 ;
     RECT  20.543 62.208 20.579 62.226 ;
     RECT  20.579 16.38 20.615 17.064 ;
     RECT  19.931 2.07 21.235 2.592 ;
     RECT  20.507 3.546 21.235 7.344 ;
     RECT  20.435 48.006 21.299 51.462 ;
     RECT  20.543 27.036 21.307 27.864 ;
     RECT  20.507 31.428 21.335 34.488 ;
     RECT  20.579 56.466 21.343 56.754 ;
     RECT  20.543 57.546 21.343 57.564 ;
     RECT  20.579 13.374 21.371 14.634 ;
     RECT  20.543 41.076 21.371 41.166 ;
     RECT  20.543 42.84 21.371 45.144 ;
     RECT  20.471 53.676 21.371 53.694 ;
     RECT  20.471 9.216 21.407 9.774 ;
     RECT  20.615 16.65 21.407 17.064 ;
     RECT  20.579 25.146 21.407 25.236 ;
     RECT  21.371 42.84 21.407 42.858 ;
     RECT  20.507 52.218 21.407 52.614 ;
     RECT  20.471 35.478 21.415 37.044 ;
     RECT  21.235 2.07 21.443 7.344 ;
     RECT  21.407 9.216 21.443 9.504 ;
     RECT  21.407 16.776 21.443 17.064 ;
     RECT  21.335 31.698 21.443 34.488 ;
     RECT  21.299 48.006 21.443 50.544 ;
     RECT  21.299 51.336 21.443 51.462 ;
     RECT  21.407 52.218 21.443 52.434 ;
     RECT  20.543 58.356 21.443 59.724 ;
     RECT  21.443 2.07 21.479 5.058 ;
     RECT  21.443 6.048 21.479 7.344 ;
     RECT  20.507 8.406 21.479 8.424 ;
     RECT  21.371 13.536 21.479 14.634 ;
     RECT  21.443 16.776 21.479 16.902 ;
     RECT  20.543 18.126 21.479 19.404 ;
     RECT  20.543 20.196 21.479 24.156 ;
     RECT  21.307 27.036 21.479 28.476 ;
     RECT  21.443 31.698 21.479 33.534 ;
     RECT  21.415 35.478 21.479 37.494 ;
     RECT  21.371 43.686 21.479 45.144 ;
     RECT  21.443 48.006 21.479 49.464 ;
     RECT  21.443 50.526 21.479 50.544 ;
     RECT  21.443 52.326 21.479 52.434 ;
     RECT  21.443 58.806 21.479 59.724 ;
     RECT  21.479 2.538 21.515 3.33 ;
     RECT  21.479 4.086 21.515 5.058 ;
     RECT  21.479 6.66 21.515 6.678 ;
     RECT  21.443 9.486 21.515 9.504 ;
     RECT  21.479 13.536 21.515 13.554 ;
     RECT  21.479 14.616 21.515 14.634 ;
     RECT  21.479 16.884 21.515 16.902 ;
     RECT  21.479 18.54 21.515 19.062 ;
     RECT  21.479 20.196 21.515 21.654 ;
     RECT  21.479 22.716 21.515 22.734 ;
     RECT  21.479 23.526 21.515 24.084 ;
     RECT  21.407 25.146 21.515 25.164 ;
     RECT  21.479 27.036 21.515 28.206 ;
     RECT  21.479 32.706 21.515 33.264 ;
     RECT  21.443 34.47 21.515 34.488 ;
     RECT  21.479 35.946 21.515 36.576 ;
     RECT  21.479 37.476 21.515 37.494 ;
     RECT  20.543 39.636 21.515 40.194 ;
     RECT  21.371 41.076 21.515 41.094 ;
     RECT  21.479 43.686 21.515 44.442 ;
     RECT  20.435 47.124 21.515 47.142 ;
     RECT  21.479 48.006 21.515 48.654 ;
     RECT  21.479 49.446 21.515 49.464 ;
     RECT  21.443 51.336 21.515 51.354 ;
     RECT  21.479 52.416 21.515 52.434 ;
     RECT  21.415 54.45 21.515 54.468 ;
     RECT  21.343 56.466 21.515 57.564 ;
     RECT  21.479 58.806 21.515 58.824 ;
     RECT  21.479 59.706 21.515 59.724 ;
     RECT  20.543 60.786 21.515 60.804 ;
    LAYER M3 ;
     RECT  19.908 0.715 19.926 0.811 ;
     RECT  19.872 0.811 19.926 1.099 ;
     RECT  21.492 1.003 21.51 1.195 ;
     RECT  19.368 1.099 19.926 1.291 ;
     RECT  19.332 1.291 19.926 1.387 ;
     RECT  18.504 1.387 18.522 1.483 ;
     RECT  21.456 1.195 21.51 1.483 ;
     RECT  14.796 1.531 14.814 1.579 ;
     RECT  17.208 1.435 17.226 1.579 ;
     RECT  18.18 1.483 18.522 1.579 ;
     RECT  12.024 1.435 12.042 1.675 ;
     RECT  13.104 1.387 13.122 1.675 ;
     RECT  17.208 1.579 18.522 1.675 ;
     RECT  19.332 1.387 20.538 1.675 ;
     RECT  21.42 1.483 21.51 1.675 ;
     RECT  17.208 1.675 20.538 1.687 ;
     RECT  14.796 1.579 15.426 1.723 ;
     RECT  16.272 0.907 16.29 1.723 ;
     RECT  17.172 1.687 20.538 1.723 ;
     RECT  21.384 1.675 21.51 1.723 ;
     RECT  14.328 1.723 15.426 1.759 ;
     RECT  14.328 1.759 15.498 1.795 ;
     RECT  16.272 1.723 20.538 1.795 ;
     RECT  14.328 1.795 20.538 1.831 ;
     RECT  14.112 1.831 20.538 1.957 ;
     RECT  2.556 1.867 2.574 1.963 ;
     RECT  10.44 1.723 10.458 1.993 ;
     RECT  2.304 1.963 2.574 2.029 ;
     RECT  7.308 1.993 7.326 2.029 ;
     RECT  10.296 1.993 10.458 2.029 ;
     RECT  10.296 2.029 11.106 2.065 ;
     RECT  2.304 2.029 3.042 2.101 ;
     RECT  3.816 2.029 3.834 2.101 ;
     RECT  7.272 2.029 7.326 2.101 ;
     RECT  8.856 1.483 8.874 2.101 ;
     RECT  10.26 2.065 11.106 2.101 ;
     RECT  6.804 2.101 7.326 2.143 ;
     RECT  12.024 1.675 13.122 2.143 ;
     RECT  2.304 2.101 3.834 2.155 ;
     RECT  6.804 2.143 7.905 2.191 ;
     RECT  8.82 2.101 8.874 2.227 ;
     RECT  8.748 2.227 8.874 2.251 ;
     RECT  12.024 2.143 13.305 2.293 ;
     RECT  8.748 2.251 8.946 2.299 ;
     RECT  9.72 2.101 11.106 2.299 ;
     RECT  11.88 2.293 13.305 2.299 ;
     RECT  14.04 1.957 20.538 2.299 ;
     RECT  21.312 1.723 21.51 2.299 ;
     RECT  2.232 2.155 3.834 2.327 ;
     RECT  8.748 2.299 13.305 2.335 ;
     RECT  14.04 2.299 21.51 2.335 ;
     RECT  5.115 2.143 5.205 2.371 ;
     RECT  4.896 2.371 5.205 2.413 ;
     RECT  6.696 2.191 7.905 2.413 ;
     RECT  8.748 2.335 21.51 2.413 ;
     RECT  0.144 2.635 0.162 2.731 ;
     RECT  6.696 2.413 21.51 2.759 ;
     RECT  2.304 2.327 3.834 2.779 ;
     RECT  2.304 2.779 3.87 3.145 ;
     RECT  4.896 2.413 5.397 3.145 ;
     RECT  20.196 2.759 21.51 3.149 ;
     RECT  2.304 3.145 5.397 3.181 ;
     RECT  0.144 2.731 0.342 3.307 ;
     RECT  21.312 3.149 21.51 3.335 ;
     RECT  0.108 3.307 0.342 3.341 ;
     RECT  0.108 3.341 0.126 3.437 ;
     RECT  6.696 2.759 19.422 3.479 ;
     RECT  2.304 3.181 5.922 3.541 ;
     RECT  6.696 3.479 19.098 3.541 ;
     RECT  2.304 3.541 19.098 3.569 ;
     RECT  2.304 3.569 19.062 3.787 ;
     RECT  20.196 3.149 20.538 3.911 ;
     RECT  2.268 3.787 19.062 4.252 ;
     RECT  21.348 3.335 21.51 4.363 ;
     RECT  2.232 4.252 19.062 4.415 ;
     RECT  2.268 4.415 19.062 4.531 ;
     RECT  20.448 3.911 20.538 4.747 ;
     RECT  20.412 4.747 20.538 5.035 ;
     RECT  21.312 4.363 21.51 5.035 ;
     RECT  20.196 5.035 21.51 5.063 ;
     RECT  20.196 5.063 21.474 5.072 ;
     RECT  2.268 4.531 19.206 5.189 ;
     RECT  20.196 5.072 20.538 5.611 ;
     RECT  21.348 5.072 21.474 5.995 ;
     RECT  0.324 4.363 0.342 6.029 ;
     RECT  2.268 5.189 18.954 6.035 ;
     RECT  2.304 6.035 18.954 6.043 ;
     RECT  19.908 5.611 20.538 6.043 ;
     RECT  21.348 5.995 21.51 6.091 ;
     RECT  2.304 6.043 20.538 6.143 ;
     RECT  21.276 6.091 21.51 6.221 ;
     RECT  15.84 6.143 20.538 6.269 ;
     RECT  2.304 6.143 15.066 6.377 ;
     RECT  15.915 6.269 20.538 6.509 ;
     RECT  21.348 6.221 21.51 6.683 ;
     RECT  21.348 6.683 21.474 6.701 ;
     RECT  2.304 6.377 14.994 6.719 ;
     RECT  2.34 6.719 14.994 7.195 ;
     RECT  15.915 6.509 20.502 7.195 ;
     RECT  0.108 7.147 0.126 7.243 ;
     RECT  0.108 7.243 0.342 7.357 ;
     RECT  0.108 7.357 0.558 7.373 ;
     RECT  21.456 6.701 21.474 7.435 ;
     RECT  2.34 7.195 20.502 7.531 ;
     RECT  21.456 7.435 21.51 7.627 ;
     RECT  0.54 7.373 0.558 7.757 ;
     RECT  21.42 7.627 21.51 7.819 ;
     RECT  2.304 7.531 20.502 7.901 ;
     RECT  21.384 7.819 21.51 8.107 ;
     RECT  15.768 7.901 20.502 8.231 ;
     RECT  2.304 7.901 14.994 8.683 ;
     RECT  2.268 8.683 14.994 8.735 ;
     RECT  0.144 8.107 0.162 8.875 ;
     RECT  0.144 8.875 0.342 9.005 ;
     RECT  2.304 8.735 14.994 9.121 ;
     RECT  2.304 9.121 15.03 9.247 ;
     RECT  2.304 9.247 15.102 9.355 ;
     RECT  15.84 8.231 20.502 9.355 ;
     RECT  2.304 9.355 20.502 9.383 ;
     RECT  15.732 9.383 20.502 9.509 ;
     RECT  21.348 8.107 21.51 9.509 ;
     RECT  21.348 9.509 21.438 9.629 ;
     RECT  15.876 9.509 20.502 9.739 ;
     RECT  15.876 9.739 20.538 9.815 ;
     RECT  0.144 9.005 0.162 9.835 ;
     RECT  2.304 9.383 14.994 10.109 ;
     RECT  21.384 9.629 21.438 10.411 ;
     RECT  21.312 10.411 21.438 10.541 ;
     RECT  0.144 9.835 0.342 10.637 ;
     RECT  15.915 9.815 20.538 10.697 ;
     RECT  2.304 10.109 14.922 10.795 ;
     RECT  2.232 10.795 14.922 10.831 ;
     RECT  2.232 10.831 15.03 10.867 ;
     RECT  2.232 10.867 15.102 11.209 ;
     RECT  15.915 10.697 20.502 11.209 ;
     RECT  1.152 11.227 1.17 11.405 ;
     RECT  21.42 10.541 21.438 11.563 ;
     RECT  2.232 11.209 20.502 11.777 ;
     RECT  2.268 11.777 20.502 11.939 ;
     RECT  2.268 11.939 20.466 12.515 ;
     RECT  21.312 11.563 21.438 12.571 ;
     RECT  0.144 12.523 0.162 12.667 ;
     RECT  0.144 12.667 0.234 12.715 ;
     RECT  2.304 12.515 20.466 12.749 ;
     RECT  20.412 12.749 20.466 12.793 ;
     RECT  21.276 12.571 21.438 12.793 ;
     RECT  20.412 12.793 21.438 12.941 ;
     RECT  21.348 12.941 21.438 13.003 ;
     RECT  20.412 12.941 20.574 13.019 ;
     RECT  0.144 12.715 0.342 13.325 ;
     RECT  21.348 13.003 21.51 13.397 ;
     RECT  20.484 13.019 20.574 13.421 ;
     RECT  2.304 12.749 19.386 13.579 ;
     RECT  0.144 13.325 0.234 13.639 ;
     RECT  0.108 13.639 0.234 13.805 ;
     RECT  2.304 13.579 19.422 13.963 ;
     RECT  0.216 13.805 0.234 14.059 ;
     RECT  20.484 13.421 20.538 14.155 ;
     RECT  20.448 14.155 20.538 14.171 ;
     RECT  0.216 14.059 0.342 14.189 ;
     RECT  21.384 13.397 21.51 14.237 ;
     RECT  20.448 14.171 20.502 14.251 ;
     RECT  2.268 13.963 19.422 14.347 ;
     RECT  21.456 14.237 21.51 14.369 ;
     RECT  20.412 14.251 20.502 14.539 ;
     RECT  20.376 14.539 20.502 14.635 ;
     RECT  21.492 14.369 21.51 14.639 ;
     RECT  2.268 14.347 19.458 14.731 ;
     RECT  20.34 14.635 20.502 14.827 ;
     RECT  20.304 14.827 20.502 15.115 ;
     RECT  20.304 15.115 20.538 15.403 ;
     RECT  2.268 14.731 19.494 15.521 ;
     RECT  21.42 15.451 21.438 15.547 ;
     RECT  21.348 15.547 21.438 15.629 ;
     RECT  20.304 15.403 20.574 15.691 ;
     RECT  0.144 15.739 0.162 15.917 ;
     RECT  21.348 15.629 21.402 15.917 ;
     RECT  20.304 15.691 20.61 16.061 ;
     RECT  2.268 15.521 19.242 16.331 ;
     RECT  21.384 15.917 21.402 16.363 ;
     RECT  20.448 16.061 20.61 16.403 ;
     RECT  21.384 16.363 21.51 16.651 ;
     RECT  20.448 16.403 20.502 16.939 ;
     RECT  2.268 16.331 19.026 17.213 ;
     RECT  21.312 16.651 21.51 17.261 ;
     RECT  15.876 17.213 19.026 17.515 ;
     RECT  19.908 16.939 20.502 17.515 ;
     RECT  0.324 17.515 0.342 17.645 ;
     RECT  2.268 17.213 15.138 17.879 ;
     RECT  15.876 17.515 20.502 17.995 ;
     RECT  15.66 17.995 20.502 18.187 ;
     RECT  0.108 18.091 0.198 18.236 ;
     RECT  0.144 18.236 0.198 18.413 ;
     RECT  21.42 17.261 21.51 18.667 ;
     RECT  15.66 18.187 20.538 18.689 ;
     RECT  2.268 17.879 14.922 18.697 ;
     RECT  2.268 18.697 14.994 18.725 ;
     RECT  15.804 18.689 20.538 18.749 ;
     RECT  15.84 18.749 20.538 18.761 ;
     RECT  0.324 18.667 0.342 18.797 ;
     RECT  21.348 18.667 21.51 18.797 ;
     RECT  15.84 18.761 20.466 18.959 ;
     RECT  2.304 18.725 14.994 18.995 ;
     RECT  21.456 18.797 21.51 19.067 ;
     RECT  2.304 18.995 14.922 19.229 ;
     RECT  15.84 18.959 20.43 19.277 ;
     RECT  15.84 19.277 19.494 19.301 ;
     RECT  21.456 19.067 21.474 19.409 ;
     RECT  15.876 19.301 19.494 19.643 ;
     RECT  20.304 19.277 20.43 19.813 ;
     RECT  15.876 19.643 18.954 19.913 ;
     RECT  0.144 19.771 0.162 19.949 ;
     RECT  20.304 19.813 20.538 20.011 ;
     RECT  2.304 19.229 14.814 20.107 ;
     RECT  21.492 20.107 21.51 20.299 ;
     RECT  20.196 20.011 20.538 20.381 ;
     RECT  2.304 20.107 15.03 20.491 ;
     RECT  21.312 20.299 21.51 20.525 ;
     RECT  2.268 20.491 15.03 20.659 ;
     RECT  15.876 19.913 18.897 20.659 ;
     RECT  20.484 20.381 20.538 20.849 ;
     RECT  2.268 20.659 18.897 20.957 ;
     RECT  15.915 20.957 18.897 21.271 ;
     RECT  21.42 20.525 21.51 21.352 ;
     RECT  21.348 21.352 21.51 21.361 ;
     RECT  0.144 20.923 0.162 21.533 ;
     RECT  15.915 21.271 18.954 21.787 ;
     RECT  20.52 20.849 20.538 21.931 ;
     RECT  21.276 21.361 21.51 21.931 ;
     RECT  20.52 21.931 21.51 21.937 ;
     RECT  2.268 20.957 15.03 21.979 ;
     RECT  2.232 21.979 15.03 22.027 ;
     RECT  15.915 21.787 18.99 22.027 ;
     RECT  2.232 22.027 18.99 22.157 ;
     RECT  19.944 21.937 21.51 22.157 ;
     RECT  21.276 22.157 21.51 22.445 ;
     RECT  21.348 22.445 21.51 22.589 ;
     RECT  19.944 22.157 20.502 22.699 ;
     RECT  21.384 22.589 21.51 23.069 ;
     RECT  19.836 22.699 20.502 23.179 ;
     RECT  21.42 23.069 21.51 23.279 ;
     RECT  19.836 23.179 20.538 23.423 ;
     RECT  2.268 22.157 18.99 23.431 ;
     RECT  19.908 23.423 20.538 23.657 ;
     RECT  2.268 23.431 19.026 24.161 ;
     RECT  0.324 23.755 0.342 24.187 ;
     RECT  0.216 24.187 0.342 24.235 ;
     RECT  21.456 23.279 21.51 24.331 ;
     RECT  0.144 24.235 0.342 24.413 ;
     RECT  0.216 24.413 0.342 24.461 ;
     RECT  2.268 24.161 15.066 24.467 ;
     RECT  21.312 24.331 21.51 24.619 ;
     RECT  21.276 24.619 21.51 24.749 ;
     RECT  19.908 23.657 20.502 25.003 ;
     RECT  21.312 24.749 21.51 25.169 ;
     RECT  19.908 25.003 20.538 25.387 ;
     RECT  0.324 24.461 0.342 25.517 ;
     RECT  2.304 24.467 15.066 25.519 ;
     RECT  2.304 25.519 15.138 25.555 ;
     RECT  15.915 24.161 19.026 25.555 ;
     RECT  19.908 25.387 20.574 25.579 ;
     RECT  19.872 25.579 20.574 25.675 ;
     RECT  21.312 25.169 21.402 25.675 ;
     RECT  19.872 25.675 21.402 25.781 ;
     RECT  21.24 25.781 21.402 25.805 ;
     RECT  19.872 25.781 20.502 25.979 ;
     RECT  19.872 25.979 20.466 26.155 ;
     RECT  19.836 26.155 20.466 26.249 ;
     RECT  21.312 25.805 21.402 26.251 ;
     RECT  2.304 25.555 19.026 26.347 ;
     RECT  19.836 26.249 20.43 26.347 ;
     RECT  2.304 26.347 20.43 26.357 ;
     RECT  2.304 26.357 15.03 26.669 ;
     RECT  21.312 26.251 21.51 26.669 ;
     RECT  2.304 26.669 14.994 26.923 ;
     RECT  15.768 26.357 20.43 27.175 ;
     RECT  15.732 27.175 20.43 27.403 ;
     RECT  0.144 27.451 0.162 27.499 ;
     RECT  0.144 27.499 0.342 27.629 ;
     RECT  2.268 26.923 14.994 27.751 ;
     RECT  15.732 27.403 20.538 27.751 ;
     RECT  21.384 26.669 21.51 27.835 ;
     RECT  21.312 27.835 21.51 28.211 ;
     RECT  21.312 28.211 21.474 28.363 ;
     RECT  21.276 28.363 21.474 28.493 ;
     RECT  2.268 27.751 20.538 28.589 ;
     RECT  0.144 28.507 0.162 28.651 ;
     RECT  2.304 28.589 20.538 28.651 ;
     RECT  21.276 28.493 21.438 28.651 ;
     RECT  0.144 28.651 0.342 28.973 ;
     RECT  2.304 28.651 21.438 28.973 ;
     RECT  2.304 28.973 20.574 29.561 ;
     RECT  2.304 29.561 20.502 29.707 ;
     RECT  2.268 29.707 20.502 29.795 ;
     RECT  21.42 29.707 21.438 29.885 ;
     RECT  0.144 28.973 0.162 30.221 ;
     RECT  21.348 29.899 21.366 30.475 ;
     RECT  21.312 30.475 21.366 30.763 ;
     RECT  0.216 30.763 0.234 30.941 ;
     RECT  2.304 29.795 20.502 30.947 ;
     RECT  21.312 30.763 21.438 30.955 ;
     RECT  21.204 30.955 21.438 31.085 ;
     RECT  21.276 31.085 21.438 31.243 ;
     RECT  2.304 30.947 20.466 31.339 ;
     RECT  21.276 31.243 21.474 31.565 ;
     RECT  2.268 31.339 20.466 31.649 ;
     RECT  2.268 31.649 19.422 31.793 ;
     RECT  0.144 31.675 0.162 31.853 ;
     RECT  20.448 31.649 20.466 31.915 ;
     RECT  21.312 31.565 21.474 32.203 ;
     RECT  20.448 31.915 20.502 32.395 ;
     RECT  2.268 31.793 19.134 32.459 ;
     RECT  19.908 32.395 20.502 32.531 ;
     RECT  21.312 32.203 21.51 32.813 ;
     RECT  2.268 32.459 18.99 32.875 ;
     RECT  0.54 32.809 0.558 33.101 ;
     RECT  2.232 32.875 18.99 33.107 ;
     RECT  20.196 32.531 20.502 33.151 ;
     RECT  2.268 33.107 18.99 33.269 ;
     RECT  21.42 32.813 21.51 33.269 ;
     RECT  0.324 33.355 0.342 33.581 ;
     RECT  21.42 33.269 21.474 33.643 ;
     RECT  15.876 33.269 18.99 33.691 ;
     RECT  15.876 33.691 19.314 33.809 ;
     RECT  20.196 33.151 20.538 33.953 ;
     RECT  20.232 33.953 20.538 33.989 ;
     RECT  15.876 33.809 19.242 34.079 ;
     RECT  2.268 33.269 15.102 34.187 ;
     RECT  2.304 34.187 15.102 34.195 ;
     RECT  15.876 34.079 19.026 34.195 ;
     RECT  21.312 33.643 21.474 34.219 ;
     RECT  21.312 34.219 21.51 34.493 ;
     RECT  20.268 33.989 20.538 34.589 ;
     RECT  20.34 34.589 20.538 34.691 ;
     RECT  20.376 34.691 20.538 34.795 ;
     RECT  21.312 34.493 21.474 34.795 ;
     RECT  2.304 34.195 19.026 35.041 ;
     RECT  20.376 34.795 21.474 35.069 ;
     RECT  20.412 35.069 21.474 35.213 ;
     RECT  0.324 35.083 0.342 35.239 ;
     RECT  21.348 35.213 21.474 35.261 ;
     RECT  0.108 35.239 0.342 35.405 ;
     RECT  20.412 35.213 20.502 35.429 ;
     RECT  21.42 35.261 21.474 35.659 ;
     RECT  21.42 35.659 21.51 35.735 ;
     RECT  2.304 35.041 19.098 35.851 ;
     RECT  0.216 35.405 0.342 35.885 ;
     RECT  2.304 35.851 19.314 35.981 ;
     RECT  2.304 35.981 18.99 36.005 ;
     RECT  2.304 36.005 14.814 36.041 ;
     RECT  20.484 35.429 20.502 36.139 ;
     RECT  0.324 35.885 0.342 36.269 ;
     RECT  21.456 35.735 21.51 36.523 ;
     RECT  21.42 36.523 21.51 36.581 ;
     RECT  20.484 36.139 20.538 36.617 ;
     RECT  20.484 36.617 20.502 36.715 ;
     RECT  20.448 36.715 20.502 36.811 ;
     RECT  15.915 36.005 18.99 36.859 ;
     RECT  21.42 36.581 21.474 36.859 ;
     RECT  2.304 36.041 14.742 36.895 ;
     RECT  20.412 36.811 20.502 36.907 ;
     RECT  15.912 36.859 18.99 36.931 ;
     RECT  21.384 36.859 21.474 37.037 ;
     RECT  15.912 36.931 19.062 37.165 ;
     RECT  2.304 36.895 14.814 37.291 ;
     RECT  0.324 37.291 0.342 37.421 ;
     RECT  2.304 37.291 14.994 37.471 ;
     RECT  15.912 37.165 19.134 37.471 ;
     RECT  21.42 37.037 21.474 37.471 ;
     RECT  21.42 37.471 21.51 37.517 ;
     RECT  2.304 37.471 19.134 37.579 ;
     RECT  19.908 36.907 20.502 37.579 ;
     RECT  2.232 37.579 20.502 37.661 ;
     RECT  2.268 37.661 20.502 37.859 ;
     RECT  21.42 37.517 21.438 37.949 ;
     RECT  2.268 37.859 15.102 38.129 ;
     RECT  15.915 37.859 20.466 38.129 ;
     RECT  15.915 38.129 20.43 38.309 ;
     RECT  16.92 38.309 20.43 38.669 ;
     RECT  0.144 37.915 0.162 38.717 ;
     RECT  2.268 38.129 14.922 38.741 ;
     RECT  17.136 38.669 20.43 39.115 ;
     RECT  15.915 38.309 16.197 39.451 ;
     RECT  17.136 39.115 20.502 39.451 ;
     RECT  15.915 39.451 20.502 39.479 ;
     RECT  21.492 39.403 21.51 39.595 ;
     RECT  2.268 38.741 14.886 39.883 ;
     RECT  2.232 39.883 14.886 39.929 ;
     RECT  19.872 39.479 20.502 39.979 ;
     RECT  2.268 39.929 14.886 40.099 ;
     RECT  2.268 40.099 14.958 40.163 ;
     RECT  0.216 40.123 0.234 40.171 ;
     RECT  21.456 39.595 21.51 40.171 ;
     RECT  15.915 39.479 19.026 40.199 ;
     RECT  0.144 40.171 0.234 40.267 ;
     RECT  2.304 40.163 14.958 40.297 ;
     RECT  15.915 40.199 18.99 40.297 ;
     RECT  0.144 40.267 0.342 40.349 ;
     RECT  19.872 39.979 20.538 40.363 ;
     RECT  21.42 40.171 21.51 40.939 ;
     RECT  0.216 40.349 0.342 41.165 ;
     RECT  21.348 40.939 21.51 41.171 ;
     RECT  21.42 41.171 21.51 41.213 ;
     RECT  2.304 40.297 18.99 41.215 ;
     RECT  19.836 40.363 20.538 41.215 ;
     RECT  0.216 41.165 0.234 41.309 ;
     RECT  0.18 41.371 0.198 41.549 ;
     RECT  21.492 41.213 21.51 42.187 ;
     RECT  21.42 42.187 21.51 42.283 ;
     RECT  21.384 42.283 21.51 42.475 ;
     RECT  21.348 42.475 21.51 42.523 ;
     RECT  0.144 42.379 0.162 42.557 ;
     RECT  2.304 41.215 20.538 42.571 ;
     RECT  21.276 42.523 21.51 42.571 ;
     RECT  2.304 42.571 21.51 42.601 ;
     RECT  2.268 42.601 21.51 42.701 ;
     RECT  21.312 42.701 21.51 43.133 ;
     RECT  2.268 42.701 20.538 43.243 ;
     RECT  0.324 43.72 0.342 43.723 ;
     RECT  0.216 43.723 0.342 43.726 ;
     RECT  0.108 43.726 0.342 43.853 ;
     RECT  21.384 43.133 21.51 44.155 ;
     RECT  0.144 43.853 0.342 44.299 ;
     RECT  2.232 43.243 20.538 44.375 ;
     RECT  0.144 44.299 0.378 44.429 ;
     RECT  21.348 44.155 21.51 44.447 ;
     RECT  21.348 44.447 21.474 44.587 ;
     RECT  0.144 44.429 0.162 44.669 ;
     RECT  21.312 44.587 21.474 45.005 ;
     RECT  21.348 45.005 21.474 45.149 ;
     RECT  2.268 44.375 20.538 45.185 ;
     RECT  0.144 45.787 0.162 45.931 ;
     RECT  0.144 45.931 0.342 46.061 ;
     RECT  2.304 45.185 20.538 46.103 ;
     RECT  21.348 45.149 21.438 46.411 ;
     RECT  21.276 46.411 21.438 46.507 ;
     RECT  21.276 46.507 21.51 46.637 ;
     RECT  21.312 46.637 21.51 46.733 ;
     RECT  2.304 46.103 20.502 46.769 ;
     RECT  0.144 47.131 0.162 47.309 ;
     RECT  2.304 46.769 19.026 47.309 ;
     RECT  2.304 47.309 18.99 47.461 ;
     RECT  2.268 47.461 18.99 47.501 ;
     RECT  21.384 46.733 21.51 47.563 ;
     RECT  0.324 47.389 0.558 47.693 ;
     RECT  19.836 46.769 20.502 47.849 ;
     RECT  21.312 47.563 21.51 47.885 ;
     RECT  0.54 47.693 0.558 48.077 ;
     RECT  21.42 47.885 21.51 48.221 ;
     RECT  2.304 47.501 18.99 48.271 ;
     RECT  2.304 48.271 19.314 48.557 ;
     RECT  2.304 48.557 18.99 48.619 ;
     RECT  2.268 48.619 18.99 48.845 ;
     RECT  20.448 47.849 20.502 48.907 ;
     RECT  2.268 48.845 18.954 48.965 ;
     RECT  21.492 48.221 21.51 48.973 ;
     RECT  21.456 48.973 21.51 49.003 ;
     RECT  0.324 48.907 0.342 49.037 ;
     RECT  0.252 49.099 0.27 49.195 ;
     RECT  20.412 48.907 20.502 49.199 ;
     RECT  2.304 48.965 18.954 49.235 ;
     RECT  0.144 49.195 0.27 49.373 ;
     RECT  15.876 49.235 18.954 49.469 ;
     RECT  20.412 49.199 20.466 49.483 ;
     RECT  15.915 49.469 18.954 49.771 ;
     RECT  21.384 49.003 21.51 49.963 ;
     RECT  0.324 49.867 0.342 49.997 ;
     RECT  15.915 49.771 19.422 50.155 ;
     RECT  20.196 49.483 20.466 50.155 ;
     RECT  21.312 49.963 21.51 50.251 ;
     RECT  15.915 50.155 20.466 50.539 ;
     RECT  21.24 50.251 21.51 50.539 ;
     RECT  2.304 49.235 15.102 50.629 ;
     RECT  2.196 50.629 15.102 50.665 ;
     RECT  2.196 50.665 15.174 50.669 ;
     RECT  2.268 50.669 15.174 50.963 ;
     RECT  2.304 50.963 15.174 51.061 ;
     RECT  15.915 50.539 21.51 51.061 ;
     RECT  2.304 51.061 21.51 51.245 ;
     RECT  2.304 51.245 20.502 51.883 ;
     RECT  21.42 51.245 21.51 52.027 ;
     RECT  21.312 52.027 21.51 52.205 ;
     RECT  2.268 51.883 20.502 52.397 ;
     RECT  15.84 52.397 20.502 52.439 ;
     RECT  21.384 52.205 21.51 52.439 ;
     RECT  2.268 52.397 15.102 52.459 ;
     RECT  15.876 52.439 20.502 52.709 ;
     RECT  2.196 52.459 15.102 52.745 ;
     RECT  21.384 52.439 21.402 53.227 ;
     RECT  2.268 52.745 15.102 53.323 ;
     RECT  21.312 53.227 21.402 53.323 ;
     RECT  15.876 52.709 20.466 53.467 ;
     RECT  0.324 53.419 0.342 53.549 ;
     RECT  2.268 53.323 15.138 53.563 ;
     RECT  15.876 53.467 20.502 53.563 ;
     RECT  21.312 53.323 21.438 53.707 ;
     RECT  2.268 53.563 20.502 53.789 ;
     RECT  21.276 53.707 21.438 53.837 ;
     RECT  2.268 53.789 19.026 54.091 ;
     RECT  21.312 53.837 21.438 54.125 ;
     RECT  19.764 53.789 20.502 54.283 ;
     RECT  21.42 54.125 21.438 54.445 ;
     RECT  2.196 54.091 19.026 54.473 ;
     RECT  0.216 54.427 0.234 54.475 ;
     RECT  0.144 54.475 0.234 54.571 ;
     RECT  0.144 54.571 0.378 54.653 ;
     RECT  2.268 54.473 19.026 54.667 ;
     RECT  19.764 54.283 20.538 54.667 ;
     RECT  0.216 54.653 0.378 54.701 ;
     RECT  0.216 54.701 0.306 54.779 ;
     RECT  0.216 54.779 0.234 54.797 ;
     RECT  21.42 54.445 21.51 54.859 ;
     RECT  21.312 54.859 21.51 55.051 ;
     RECT  2.268 54.667 20.538 55.627 ;
     RECT  21.276 55.051 21.51 55.627 ;
     RECT  2.268 55.627 21.51 55.853 ;
     RECT  0.324 56.203 0.342 56.333 ;
     RECT  2.268 55.853 20.574 56.363 ;
     RECT  2.268 56.363 20.538 56.633 ;
     RECT  21.348 55.853 21.51 56.984 ;
     RECT  2.268 56.633 14.958 57.209 ;
     RECT  0.324 57.259 0.342 57.389 ;
     RECT  21.384 56.984 21.51 57.437 ;
     RECT  2.304 57.209 14.958 57.547 ;
     RECT  15.732 56.633 20.538 57.547 ;
     RECT  21.42 57.437 21.51 57.569 ;
     RECT  2.304 57.547 20.538 57.911 ;
     RECT  0.54 57.991 0.558 58.157 ;
     RECT  2.304 57.911 20.502 58.315 ;
     RECT  21.42 57.569 21.438 58.315 ;
     RECT  0.108 58.693 0.126 58.733 ;
     RECT  2.268 58.315 20.502 58.781 ;
     RECT  0.324 58.891 0.342 59.021 ;
     RECT  2.268 58.781 15.174 59.069 ;
     RECT  15.915 58.781 20.502 59.275 ;
     RECT  21.42 58.315 21.51 59.371 ;
     RECT  21.312 59.371 21.51 59.501 ;
     RECT  2.268 59.069 15.066 59.845 ;
     RECT  15.915 59.275 20.538 59.845 ;
     RECT  2.268 59.845 20.538 60.143 ;
     RECT  0.144 60.139 0.162 60.317 ;
     RECT  21.42 59.501 21.51 60.427 ;
     RECT  2.268 60.143 20.502 60.523 ;
     RECT  21.348 60.427 21.51 60.605 ;
     RECT  1.152 60.667 1.17 60.715 ;
     RECT  21.42 60.605 21.51 60.809 ;
     RECT  1.152 60.715 1.278 60.961 ;
     RECT  2.232 60.523 20.502 60.961 ;
     RECT  1.152 60.961 20.502 61.003 ;
     RECT  0.324 61.003 0.342 61.099 ;
     RECT  0.216 61.099 0.342 61.123 ;
     RECT  1.152 61.003 20.538 61.123 ;
     RECT  0.216 61.123 20.538 61.291 ;
     RECT  0.216 61.291 20.574 61.393 ;
     RECT  0.036 61.393 20.574 61.691 ;
     RECT  21.42 60.809 21.438 61.723 ;
     RECT  19.908 61.691 20.574 61.763 ;
     RECT  0.036 61.691 18.954 61.925 ;
     RECT  0.036 61.925 6.93 61.997 ;
     RECT  21.384 61.723 21.438 61.997 ;
     RECT  19.98 61.763 20.574 62.093 ;
     RECT  7.815 61.925 18.954 62.231 ;
     RECT  20.34 62.093 20.574 62.231 ;
     RECT  0.036 61.997 0.558 62.285 ;
     RECT  1.692 61.997 6.93 62.303 ;
     RECT  20.34 62.231 20.538 62.333 ;
     RECT  7.815 62.231 8.097 62.387 ;
     RECT  20.412 62.333 20.538 62.429 ;
     RECT  8.928 62.231 18.954 62.435 ;
     RECT  1.692 62.303 6.858 62.465 ;
     RECT  21.42 61.997 21.438 62.477 ;
     RECT  20.52 62.429 20.538 62.501 ;
     RECT  9.576 62.435 18.954 62.573 ;
     RECT  1.692 62.465 6.606 62.609 ;
     RECT  9.576 62.573 12.15 62.609 ;
     RECT  1.692 62.609 6.03 62.621 ;
     RECT  10.188 62.609 12.15 62.621 ;
     RECT  13.104 62.573 18.954 62.621 ;
     RECT  1.692 62.621 3.078 62.657 ;
     RECT  7.815 62.387 7.905 62.657 ;
     RECT  10.188 62.621 10.605 62.657 ;
     RECT  0.036 62.285 0.162 62.669 ;
     RECT  11.664 62.621 12.15 62.669 ;
     RECT  3.06 62.657 3.078 62.699 ;
     RECT  10.188 62.657 10.278 62.699 ;
     RECT  13.104 62.621 16.398 62.699 ;
     RECT  0.036 62.669 0.126 62.735 ;
     RECT  14.256 62.699 16.362 62.765 ;
     RECT  10.188 62.699 10.206 62.771 ;
     RECT  11.916 62.669 12.15 62.771 ;
     RECT  14.256 62.765 14.31 62.807 ;
     RECT  17.424 62.621 18.954 62.807 ;
     RECT  13.104 62.699 13.122 62.813 ;
     RECT  17.424 62.807 18.198 62.813 ;
     RECT  14.292 62.807 14.31 62.843 ;
     RECT  17.424 62.813 17.442 62.843 ;
     RECT  15.336 62.765 16.074 62.861 ;
     RECT  12.132 62.771 12.15 62.879 ;
     RECT  18.18 62.813 18.198 62.879 ;
     RECT  16.056 62.861 16.074 62.924 ;
     RECT  18.936 62.807 18.954 62.924 ;
     RECT  4.14 62.621 6.03 62.957 ;
     RECT  4.176 62.957 6.03 63.341 ;
     RECT  1.692 62.657 1.71 63.437 ;
     RECT  4.176 63.341 4.806 63.533 ;
     RECT  4.536 63.533 4.806 63.629 ;
     RECT  5.94 63.341 6.03 63.725 ;
     RECT  4.788 63.629 4.806 63.821 ;
     RECT  0.108 62.735 0.126 63.917 ;
     RECT  6.012 63.725 6.03 64.013 ;
    LAYER M4 ;
     RECT  0.06 1.872 2.585 64.008 ;
     RECT  2.585 2.256 2.657 64.008 ;
     RECT  2.657 2.418 2.704 64.008 ;
     RECT  2.704 26.64 2.765 34.152 ;
     RECT  2.704 35.184 2.801 42.552 ;
     RECT  2.704 2.544 2.837 16.392 ;
     RECT  2.704 17.424 2.837 25.512 ;
     RECT  2.765 26.64 2.837 32.232 ;
     RECT  2.765 33.84 2.837 33.96 ;
     RECT  2.704 46.032 2.837 52.488 ;
     RECT  2.704 53.52 2.837 64.008 ;
     RECT  2.837 7.344 2.873 16.392 ;
     RECT  2.837 17.424 2.873 23.352 ;
     RECT  2.837 33.936 2.873 33.96 ;
     RECT  2.801 35.184 2.873 42.456 ;
     RECT  2.837 53.904 2.873 64.008 ;
     RECT  2.837 2.544 2.909 6.12 ;
     RECT  2.873 7.344 2.909 9.528 ;
     RECT  2.873 17.616 2.909 23.352 ;
     RECT  2.837 26.64 2.909 31.896 ;
     RECT  2.873 35.28 2.909 42.456 ;
     RECT  2.873 53.904 2.945 59.784 ;
     RECT  2.909 35.28 2.981 36.552 ;
     RECT  2.909 37.584 2.981 42.456 ;
     RECT  2.909 2.544 3.017 4.968 ;
     RECT  2.909 26.64 3.017 29.496 ;
     RECT  2.981 37.728 3.017 42.456 ;
     RECT  2.837 46.032 3.017 47.16 ;
     RECT  2.837 48.24 3.017 52.296 ;
     RECT  2.945 53.904 3.017 58.536 ;
     RECT  3.017 4.944 3.089 4.968 ;
     RECT  3.017 27.12 3.089 29.496 ;
     RECT  2.704 43.632 3.089 44.664 ;
     RECT  2.909 17.616 3.125 19.8 ;
     RECT  3.017 41.376 3.125 42.456 ;
     RECT  3.017 48.24 3.125 51.72 ;
     RECT  2.945 59.76 3.125 59.784 ;
     RECT  2.873 10.608 3.197 16.392 ;
     RECT  2.837 24.336 3.197 25.512 ;
     RECT  3.089 43.632 3.197 44.136 ;
     RECT  2.909 8.256 3.233 9.096 ;
     RECT  3.125 17.616 3.233 18.168 ;
     RECT  3.017 37.728 3.233 40.392 ;
     RECT  3.197 43.776 3.233 44.136 ;
     RECT  3.017 46.032 3.233 46.056 ;
     RECT  3.125 49.008 3.233 51.72 ;
     RECT  3.233 43.776 3.269 43.848 ;
     RECT  3.197 14.16 3.305 16.392 ;
     RECT  3.233 37.728 3.305 40.152 ;
     RECT  3.233 49.008 3.305 50.088 ;
     RECT  3.233 51.12 3.305 51.72 ;
     RECT  3.017 54.048 3.305 58.008 ;
     RECT  3.233 8.256 3.341 8.28 ;
     RECT  2.909 30.768 3.341 31.896 ;
     RECT  3.305 49.296 3.341 50.088 ;
     RECT  3.125 19.344 3.377 19.8 ;
     RECT  3.089 27.888 3.377 29.496 ;
     RECT  3.269 43.776 3.377 43.8 ;
     RECT  3.341 50.064 3.377 50.088 ;
     RECT  3.305 56.304 3.377 58.008 ;
     RECT  2.981 35.424 3.413 36.552 ;
     RECT  3.305 51.12 3.413 51.144 ;
     RECT  3.305 54.048 3.449 54.744 ;
     RECT  2.909 5.952 3.629 6.12 ;
     RECT  2.909 20.928 3.629 23.352 ;
     RECT  3.017 2.544 3.773 3.912 ;
     RECT  3.197 10.608 3.845 13.128 ;
     RECT  3.773 2.784 3.881 3.912 ;
     RECT  3.377 56.928 3.917 58.008 ;
     RECT  3.305 37.728 3.925 39.384 ;
     RECT  3.877 36.624 3.949 36.648 ;
     RECT  3.841 6.816 3.989 6.84 ;
     RECT  3.845 10.8 4.025 13.128 ;
     RECT  3.377 19.344 4.025 19.368 ;
     RECT  3.197 24.336 4.061 24.36 ;
     RECT  3.377 28.56 4.061 29.496 ;
     RECT  3.413 35.424 4.061 35.448 ;
     RECT  3.917 57.84 4.061 58.008 ;
     RECT  3.233 18.144 4.097 18.168 ;
     RECT  3.925 37.728 4.097 38.52 ;
     RECT  3.449 54.576 4.097 54.744 ;
     RECT  4.061 57.888 4.097 58.008 ;
     RECT  3.629 20.928 4.133 22.776 ;
     RECT  2.873 60.816 4.201 64.008 ;
     RECT  3.881 3.024 5.108 3.912 ;
     RECT  4.921 6.864 5.108 6.888 ;
     RECT  4.849 9.12 5.108 9.144 ;
     RECT  4.025 10.8 5.108 11.688 ;
     RECT  4.025 12.96 5.108 13.128 ;
     RECT  3.305 14.832 5.108 16.392 ;
     RECT  4.133 20.928 5.108 21.96 ;
     RECT  3.877 25.68 5.108 25.704 ;
     RECT  4.061 28.56 5.108 28.776 ;
     RECT  3.341 31.056 5.108 31.896 ;
     RECT  3.949 36.624 5.108 36.696 ;
     RECT  4.097 38.496 5.108 38.52 ;
     RECT  3.125 42.048 5.108 42.456 ;
     RECT  3.017 47.136 5.108 47.16 ;
     RECT  4.097 54.72 5.108 54.744 ;
     RECT  4.097 57.888 5.108 57.912 ;
     RECT  4.201 60.576 5.108 64.008 ;
     RECT  5.108 2.148 5.212 64.008 ;
     RECT  5.212 2.418 5.404 64.008 ;
     RECT  5.404 61.584 5.717 64.008 ;
     RECT  5.717 63.216 6.005 64.008 ;
     RECT  6.005 63.984 6.041 64.008 ;
     RECT  5.717 61.584 6.185 62.04 ;
     RECT  6.185 62.016 6.329 62.04 ;
     RECT  6.397 54.72 6.545 54.744 ;
     RECT  5.404 18.816 6.613 18.84 ;
     RECT  6.613 18.816 6.653 18.984 ;
     RECT  5.404 12.864 6.709 12.888 ;
     RECT  6.677 14.256 6.709 14.28 ;
     RECT  6.709 12.864 6.761 14.28 ;
     RECT  6.761 12.864 6.796 13.8 ;
     RECT  6.469 9.36 6.797 9.384 ;
     RECT  6.653 18.96 6.797 18.984 ;
     RECT  5.404 3.024 6.829 4.152 ;
     RECT  6.613 7.104 6.829 7.128 ;
     RECT  5.404 11.664 6.829 11.688 ;
     RECT  6.796 12.864 6.829 12.888 ;
     RECT  6.829 3.024 7.808 4.44 ;
     RECT  6.829 7.104 7.808 7.656 ;
     RECT  6.829 11.664 7.808 12.888 ;
     RECT  7.261 19.056 7.808 19.08 ;
     RECT  5.404 21.936 7.808 21.96 ;
     RECT  6.829 26.592 7.808 26.616 ;
     RECT  6.829 36.144 7.808 36.168 ;
     RECT  5.404 38.496 7.808 38.52 ;
     RECT  7.12 50.784 7.808 50.808 ;
     RECT  7.808 2.148 7.912 62.652 ;
     RECT  7.912 2.148 8.104 62.382 ;
     RECT  8.104 16.944 8.723 17.688 ;
     RECT  8.104 2.148 8.845 5.592 ;
     RECT  8.104 61.968 8.917 62.382 ;
     RECT  8.104 7.104 9.097 7.128 ;
     RECT  8.104 8.208 9.097 8.232 ;
     RECT  8.104 19.056 9.097 19.08 ;
     RECT  8.104 23.328 9.097 24.12 ;
     RECT  8.104 56.352 9.097 56.376 ;
     RECT  9.097 7.104 9.133 8.232 ;
     RECT  9.097 51.744 9.133 52.104 ;
     RECT  8.917 61.968 9.133 62.424 ;
     RECT  8.104 42.432 9.157 42.696 ;
     RECT  9.133 51.744 9.157 53.064 ;
     RECT  9.097 56.352 9.169 56.424 ;
     RECT  9.133 6.912 9.197 8.232 ;
     RECT  9.164 9.216 9.197 9.24 ;
     RECT  8.104 49.824 9.203 49.848 ;
     RECT  8.723 17.184 9.205 17.688 ;
     RECT  9.097 18.768 9.205 19.08 ;
     RECT  9.133 33.072 9.205 33.096 ;
     RECT  9.097 23.328 9.241 24.504 ;
     RECT  9.133 25.536 9.241 25.56 ;
     RECT  8.104 44.16 9.241 44.184 ;
     RECT  8.104 45.264 9.241 45.816 ;
     RECT  9.169 56.352 9.241 56.616 ;
     RECT  8.104 36.096 9.251 36.456 ;
     RECT  8.104 29.664 9.263 29.688 ;
     RECT  8.104 21.936 9.313 22.344 ;
     RECT  9.241 23.328 9.313 25.56 ;
     RECT  8.104 48.768 9.313 48.792 ;
     RECT  9.157 51.36 9.313 53.064 ;
     RECT  8.104 10.704 9.349 15.912 ;
     RECT  9.313 21.936 9.349 25.56 ;
     RECT  8.845 1.488 9.385 5.592 ;
     RECT  9.197 6.912 9.385 9.24 ;
     RECT  9.263 28.944 9.385 29.688 ;
     RECT  9.205 60.384 9.421 60.408 ;
     RECT  9.349 20.16 9.445 20.184 ;
     RECT  9.349 21.648 9.491 25.56 ;
     RECT  9.385 1.488 9.5 9.24 ;
     RECT  9.349 10.704 9.5 16.104 ;
     RECT  9.445 20.16 9.529 20.424 ;
     RECT  9.133 61.872 9.565 62.424 ;
     RECT  9.241 44.16 9.601 45.816 ;
     RECT  9.421 60.384 9.601 60.6 ;
     RECT  9.565 61.872 9.601 62.568 ;
     RECT  9.205 17.184 9.709 19.08 ;
     RECT  9.529 20.16 9.709 20.616 ;
     RECT  8.104 38.496 9.781 38.52 ;
     RECT  9.141 41.376 9.781 41.4 ;
     RECT  9.157 42.432 9.781 42.984 ;
     RECT  9.781 41.376 9.817 42.984 ;
     RECT  9.601 43.968 9.817 45.816 ;
     RECT  9.601 54.624 9.829 54.648 ;
     RECT  9.241 56.064 9.829 56.616 ;
     RECT  9.313 51.36 9.853 53.256 ;
     RECT  9.781 38.496 9.884 39.24 ;
     RECT  8.104 47.664 9.884 47.688 ;
     RECT  9.313 48.768 9.884 49.656 ;
     RECT  9.205 33.024 9.889 33.096 ;
     RECT  9.251 36.096 9.889 36.312 ;
     RECT  9.601 60.384 9.889 62.568 ;
     RECT  9.884 47.664 9.925 49.656 ;
     RECT  9.889 32.832 9.961 33.096 ;
     RECT  8.104 26.832 10.033 26.856 ;
     RECT  9.889 27.936 10.033 27.96 ;
     RECT  9.817 41.376 10.033 45.816 ;
     RECT  9.829 54.624 10.033 56.616 ;
     RECT  9.5 1.488 10.105 16.104 ;
     RECT  9.709 17.184 10.105 20.616 ;
     RECT  10.033 26.832 10.105 27.96 ;
     RECT  9.385 28.944 10.105 30.456 ;
     RECT  9.961 32.592 10.105 33.096 ;
     RECT  9.884 38.496 10.105 39.528 ;
     RECT  10.033 54.336 10.105 56.616 ;
     RECT  10.105 32.592 10.141 33.912 ;
     RECT  10.069 34.992 10.141 35.016 ;
     RECT  10.033 41.376 10.141 46.008 ;
     RECT  9.925 47.28 10.141 49.656 ;
     RECT  9.853 51.168 10.141 53.256 ;
     RECT  10.105 54.336 10.141 57.384 ;
     RECT  10.141 32.592 10.177 35.016 ;
     RECT  9.889 36.048 10.177 36.312 ;
     RECT  10.141 41.376 10.177 49.656 ;
     RECT  10.105 1.488 10.213 20.616 ;
     RECT  10.105 26.832 10.213 30.456 ;
     RECT  10.177 32.592 10.213 36.312 ;
     RECT  9.109 37.44 10.213 37.464 ;
     RECT  10.177 40.944 10.213 49.656 ;
     RECT  10.141 51.168 10.213 57.384 ;
     RECT  9.889 60.288 10.213 62.568 ;
     RECT  10.213 32.544 10.249 37.464 ;
     RECT  10.105 38.496 10.249 39.624 ;
     RECT  10.213 40.944 10.249 50.136 ;
     RECT  10.213 51.168 10.249 57.432 ;
     RECT  10.213 59.232 10.249 62.568 ;
     RECT  10.213 26.832 10.309 30.936 ;
     RECT  10.249 32.304 10.309 39.624 ;
     RECT  10.309 26.832 10.321 39.624 ;
     RECT  10.249 40.944 10.321 57.432 ;
     RECT  10.213 1.488 10.465 20.712 ;
     RECT  9.491 21.936 10.465 25.56 ;
     RECT  10.465 1.488 10.508 25.56 ;
     RECT  10.321 26.544 10.508 57.432 ;
     RECT  10.249 58.752 10.508 62.568 ;
     RECT  10.508 1.488 10.612 62.652 ;
     RECT  10.309 0.096 10.739 0.12 ;
     RECT  10.612 1.488 10.804 62.616 ;
     RECT  10.804 26.544 11.653 62.616 ;
     RECT  10.804 1.488 11.797 25.56 ;
     RECT  11.653 26.544 11.797 62.664 ;
     RECT  11.797 1.488 12.013 62.664 ;
     RECT  12.013 1.44 13.093 62.664 ;
     RECT  13.093 1.392 13.745 62.808 ;
     RECT  13.745 1.392 13.889 18.84 ;
     RECT  13.745 20.112 14.177 62.808 ;
     RECT  13.889 1.392 14.393 18.792 ;
     RECT  14.177 39.36 14.429 62.808 ;
     RECT  14.429 39.552 14.789 62.808 ;
     RECT  14.177 20.112 14.897 37.992 ;
     RECT  14.789 39.552 14.897 49.56 ;
     RECT  14.789 50.832 15.325 62.808 ;
     RECT  14.393 1.392 15.793 18.648 ;
     RECT  15.793 1.392 15.829 18.744 ;
     RECT  14.897 20.112 15.829 26.664 ;
     RECT  15.829 1.392 15.908 26.664 ;
     RECT  14.897 27.696 15.908 37.944 ;
     RECT  14.897 40.032 15.908 49.56 ;
     RECT  15.325 50.832 15.908 62.856 ;
     RECT  15.908 1.392 16.204 62.856 ;
     RECT  16.204 1.392 16.261 38.136 ;
     RECT  16.261 0.912 17.377 38.136 ;
     RECT  16.204 39.552 17.377 62.856 ;
     RECT  17.377 0.912 18.904 62.856 ;
     RECT  18.904 40.08 19.001 62.856 ;
     RECT  18.904 0.912 19.861 19.272 ;
     RECT  19.861 0.816 19.897 19.272 ;
     RECT  19.001 40.08 19.897 57.432 ;
     RECT  19.897 0.72 20.185 19.272 ;
     RECT  18.904 20.304 20.185 20.328 ;
     RECT  19.897 39.792 20.185 57.432 ;
     RECT  19.001 58.416 20.185 62.856 ;
     RECT  20.185 39.696 20.365 62.856 ;
     RECT  20.365 39.504 20.401 62.856 ;
     RECT  18.904 21.408 20.437 38.28 ;
     RECT  20.401 39.312 20.437 62.856 ;
     RECT  20.185 0.72 20.473 20.328 ;
     RECT  20.437 21.408 20.473 62.856 ;
     RECT  20.473 0.72 21.564 62.856 ;
    LAYER M5 ;
     RECT  10.704 0.016 10.824 0.085 ;
     RECT  10.32 0.085 10.824 1.763 ;
     RECT  18.528 1.765 18.552 1.861 ;
     RECT  18.48 1.861 18.552 2.137 ;
     RECT  2.4 2.137 2.52 2.151 ;
     RECT  5.1 2.137 5.22 2.151 ;
     RECT  7.8 2.137 7.92 2.151 ;
     RECT  13.2 2.137 13.32 2.151 ;
     RECT  15.9 2.137 16.02 2.151 ;
     RECT  18.48 2.137 18.72 2.151 ;
     RECT  17.472 2.197 17.496 2.485 ;
     RECT  18.48 2.151 18.912 2.485 ;
     RECT  13.2 2.151 13.512 2.821 ;
     RECT  17.472 2.485 18.912 2.821 ;
     RECT  0.192 2.581 0.216 2.867 ;
     RECT  15.9 2.151 16.212 3.109 ;
     RECT  17.328 2.821 18.912 3.109 ;
     RECT  21.408 2.485 21.432 3.395 ;
     RECT  7.8 2.151 8.112 3.445 ;
     RECT  13.104 2.821 13.512 3.539 ;
     RECT  13.2 3.539 13.512 3.541 ;
     RECT  7.8 3.445 8.808 3.829 ;
     RECT  7.8 3.829 9.144 3.971 ;
     RECT  15.9 3.109 18.912 4.307 ;
     RECT  17.184 4.307 18.912 4.835 ;
     RECT  21.36 4.885 21.384 5.075 ;
     RECT  7.8 3.971 8.808 5.221 ;
     RECT  17.808 4.835 18.912 5.459 ;
     RECT  7.8 5.221 9.192 5.555 ;
     RECT  11.856 3.109 11.88 5.557 ;
     RECT  13.2 3.541 13.848 5.557 ;
     RECT  0.144 3.061 0.168 6.035 ;
     RECT  11.856 5.557 13.848 6.277 ;
     RECT  11.808 6.277 13.848 6.419 ;
     RECT  18.096 5.459 18.912 6.757 ;
     RECT  17.712 6.757 18.912 6.995 ;
     RECT  10.32 1.763 10.812 7.429 ;
     RECT  11.856 6.419 13.848 7.429 ;
     RECT  7.8 5.555 8.808 8.437 ;
     RECT  10.32 7.429 13.848 8.437 ;
     RECT  18.6 6.995 18.912 8.677 ;
     RECT  17.28 9.733 17.304 9.829 ;
     RECT  15.9 4.307 16.212 10.021 ;
     RECT  17.232 9.829 17.496 10.021 ;
     RECT  15.9 10.021 17.496 10.117 ;
     RECT  18.48 8.677 18.912 10.117 ;
     RECT  7.8 8.437 13.848 10.259 ;
     RECT  15.9 10.117 18.912 10.259 ;
     RECT  21.312 10.549 21.336 10.691 ;
     RECT  11.856 10.259 13.848 10.741 ;
     RECT  3.888 3.877 3.912 10.789 ;
     RECT  5.1 2.151 5.412 10.789 ;
     RECT  7.8 10.259 10.812 10.979 ;
     RECT  17.856 10.259 18.912 11.221 ;
     RECT  17.76 11.221 18.912 11.365 ;
     RECT  17.184 11.365 18.912 11.555 ;
     RECT  10.128 10.979 10.812 11.557 ;
     RECT  11.856 10.741 14.28 11.557 ;
     RECT  21.408 11.701 21.432 11.987 ;
     RECT  10.128 11.557 14.28 12.131 ;
     RECT  18 11.555 18.912 12.275 ;
     RECT  7.8 10.979 8.808 12.517 ;
     RECT  10.128 12.131 10.812 12.517 ;
     RECT  18.336 12.275 18.912 12.611 ;
     RECT  0.144 13.141 0.168 13.331 ;
     RECT  7.8 12.517 10.812 13.763 ;
     RECT  11.856 12.131 14.28 13.811 ;
     RECT  7.8 13.763 9.144 13.859 ;
     RECT  6.72 13.765 6.744 14.291 ;
     RECT  7.8 13.859 8.808 14.387 ;
     RECT  11.856 13.811 13.848 14.773 ;
     RECT  18.6 12.611 18.912 15.541 ;
     RECT  7.8 14.387 8.112 15.877 ;
     RECT  15.9 10.259 16.212 15.973 ;
     RECT  10.32 13.763 10.812 16.069 ;
     RECT  15.312 15.973 16.212 16.115 ;
     RECT  17.856 15.541 18.912 16.211 ;
     RECT  11.856 14.773 14.328 16.403 ;
     RECT  11.856 16.403 14.04 16.547 ;
     RECT  7.8 15.877 8.712 17.699 ;
     RECT  9.696 16.069 10.812 17.699 ;
     RECT  18.6 16.211 18.912 18.421 ;
     RECT  18.288 18.421 18.912 18.755 ;
     RECT  11.856 16.547 13.848 18.757 ;
     RECT  0.144 17.461 0.168 18.803 ;
     RECT  10.32 17.699 10.812 18.997 ;
     RECT  9.456 18.997 10.812 19.525 ;
     RECT  11.856 18.757 14.088 19.525 ;
     RECT  2.4 2.151 2.712 21.397 ;
     RECT  2.4 21.397 2.856 21.539 ;
     RECT  9.456 19.525 14.088 21.683 ;
     RECT  18.6 18.755 18.912 21.925 ;
     RECT  3.888 10.789 5.412 21.971 ;
     RECT  18 21.925 18.912 22.451 ;
     RECT  9.696 21.683 14.088 23.125 ;
     RECT  9.648 23.125 14.088 23.507 ;
     RECT  0.144 23.701 0.168 23.891 ;
     RECT  9.648 23.507 13.848 24.469 ;
     RECT  21.408 24.277 21.432 25.379 ;
     RECT  0.144 24.901 0.168 25.667 ;
     RECT  18.6 22.451 18.912 26.965 ;
     RECT  18.48 26.965 18.912 27.635 ;
     RECT  15.9 16.115 16.212 28.165 ;
     RECT  17.232 25.717 17.256 28.165 ;
     RECT  15.9 28.165 17.256 28.355 ;
     RECT  17.376 28.357 17.4 28.499 ;
     RECT  2.4 21.539 2.712 28.501 ;
     RECT  18.6 27.635 18.912 28.741 ;
     RECT  2.4 28.501 2.856 28.787 ;
     RECT  9.408 24.469 13.848 28.933 ;
     RECT  9.312 28.933 13.848 28.979 ;
     RECT  9.312 28.979 9.336 29.699 ;
     RECT  17.808 28.741 18.912 30.085 ;
     RECT  17.472 30.085 18.912 30.227 ;
     RECT  18.048 30.227 18.912 30.517 ;
     RECT  21.408 30.517 21.432 30.707 ;
     RECT  18.048 30.517 19.032 30.803 ;
     RECT  18.048 30.803 18.912 31.429 ;
     RECT  17.568 31.429 18.912 31.715 ;
     RECT  10.32 28.979 13.848 31.763 ;
     RECT  18.24 31.715 18.912 32.387 ;
     RECT  0.144 33.301 0.168 33.587 ;
     RECT  18.6 32.387 18.912 34.117 ;
     RECT  17.808 34.117 18.912 34.259 ;
     RECT  21.408 34.549 21.432 35.125 ;
     RECT  21.36 35.125 21.432 35.173 ;
     RECT  18.48 34.259 18.912 35.219 ;
     RECT  21.264 35.173 21.432 35.315 ;
     RECT  21.408 35.315 21.432 35.843 ;
     RECT  0.144 35.173 0.168 36.419 ;
     RECT  9.216 33.013 9.24 36.421 ;
     RECT  9.12 36.421 9.24 36.467 ;
     RECT  9.12 36.467 9.144 37.429 ;
     RECT  10.5 31.763 13.848 37.429 ;
     RECT  9.12 37.429 13.848 37.475 ;
     RECT  0.144 37.381 0.168 37.571 ;
     RECT  3.888 21.971 3.912 39.395 ;
     RECT  9.936 37.475 13.848 41.365 ;
     RECT  9.168 41.365 13.848 41.411 ;
     RECT  10.5 41.411 13.848 42.851 ;
     RECT  18.6 35.219 18.912 43.573 ;
     RECT  17.808 43.573 18.912 44.051 ;
     RECT  0.144 44.101 0.168 44.149 ;
     RECT  7.8 17.699 8.112 44.149 ;
     RECT  9.168 41.411 9.192 44.149 ;
     RECT  7.8 44.149 9.192 44.195 ;
     RECT  0.144 44.149 0.264 44.291 ;
     RECT  0.24 44.291 0.264 44.435 ;
     RECT  21.408 44.629 21.432 45.011 ;
     RECT  10.5 42.851 11.88 45.013 ;
     RECT  18.6 44.051 18.912 45.397 ;
     RECT  10.5 45.013 11.976 45.827 ;
     RECT  15.9 28.355 16.212 45.829 ;
     RECT  15.9 45.829 17.16 46.069 ;
     RECT  18.48 45.397 18.912 46.069 ;
     RECT  21.408 46.261 21.432 46.643 ;
     RECT  0.144 47.653 0.168 47.843 ;
     RECT  7.8 44.195 9.048 47.845 ;
     RECT  10.5 45.827 11.88 47.845 ;
     RECT  21.408 47.701 21.432 47.891 ;
     RECT  15.9 46.069 18.912 48.419 ;
     RECT  15.9 48.419 17.208 48.659 ;
     RECT  13.2 42.851 13.848 48.757 ;
     RECT  17.184 48.659 17.208 48.851 ;
     RECT  7.8 47.845 11.88 48.997 ;
     RECT  13.104 48.757 13.848 49.043 ;
     RECT  7.8 48.997 11.928 49.235 ;
     RECT  7.8 49.235 11.88 49.859 ;
     RECT  13.2 49.043 13.848 50.101 ;
     RECT  0.144 48.997 0.168 50.147 ;
     RECT  9.168 49.859 11.88 50.389 ;
     RECT  13.2 50.101 14.28 50.389 ;
     RECT  17.184 50.485 17.352 50.627 ;
     RECT  17.184 50.627 17.208 50.675 ;
     RECT  18.6 48.419 18.912 51.109 ;
     RECT  18.48 51.109 18.912 51.299 ;
     RECT  9.168 50.389 14.28 51.347 ;
     RECT  9.168 51.347 13.848 51.971 ;
     RECT  9.168 51.971 10.812 52.115 ;
     RECT  18.6 51.299 18.912 52.261 ;
     RECT  2.4 28.787 2.712 52.357 ;
     RECT  18.288 52.261 18.912 52.403 ;
     RECT  2.304 52.357 2.712 52.499 ;
     RECT  0.144 53.365 0.168 53.555 ;
     RECT  18.48 52.403 18.912 53.557 ;
     RECT  17.76 53.557 18.912 53.749 ;
     RECT  11.856 51.971 13.848 53.795 ;
     RECT  21.408 53.557 21.432 53.843 ;
     RECT  17.424 53.749 18.912 53.891 ;
     RECT  17.76 53.891 18.912 54.323 ;
     RECT  18.6 54.323 18.912 54.565 ;
     RECT  9.84 52.115 10.812 55.283 ;
     RECT  18.6 54.565 19.032 55.475 ;
     RECT  18.6 55.475 18.912 55.621 ;
     RECT  15.9 48.659 16.212 55.909 ;
     RECT  15.9 55.909 17.112 56.051 ;
     RECT  18.48 55.621 18.912 56.581 ;
     RECT  18.384 56.581 18.912 57.011 ;
     RECT  10.128 55.283 10.812 57.059 ;
     RECT  0.144 56.053 0.168 57.395 ;
     RECT  13.2 53.795 13.848 57.683 ;
     RECT  2.4 52.499 2.712 57.973 ;
     RECT  10.32 57.059 10.812 59.219 ;
     RECT  0.144 58.981 0.168 59.267 ;
     RECT  18.6 57.011 18.912 60.133 ;
     RECT  15.9 56.051 16.212 60.325 ;
     RECT  10.368 59.219 10.812 60.419 ;
     RECT  18.432 60.133 18.912 60.565 ;
     RECT  15.792 60.325 16.212 60.949 ;
     RECT  18 60.565 18.912 61.187 ;
     RECT  18.432 61.187 18.912 61.189 ;
     RECT  18.432 61.189 19.896 61.235 ;
     RECT  2.4 57.973 2.856 61.427 ;
     RECT  15.792 60.949 16.488 61.765 ;
     RECT  15.6 61.765 16.488 61.907 ;
     RECT  18.6 61.235 19.896 61.909 ;
     RECT  0.144 61.621 0.168 62.003 ;
     RECT  18.6 61.909 20.52 62.245 ;
     RECT  11.856 53.795 11.88 62.339 ;
     RECT  17.856 62.245 20.52 62.579 ;
     RECT  17.856 62.579 18.912 62.627 ;
     RECT  2.4 61.427 2.712 62.649 ;
     RECT  5.1 21.971 5.412 62.649 ;
     RECT  7.8 49.859 8.112 62.649 ;
     RECT  10.5 60.419 10.812 62.649 ;
     RECT  13.2 57.683 13.512 62.649 ;
     RECT  18.6 62.627 18.912 62.649 ;
     RECT  2.4 62.649 2.52 62.663 ;
     RECT  5.1 62.649 5.22 62.663 ;
     RECT  7.8 62.649 7.92 62.663 ;
     RECT  10.5 62.649 10.62 62.663 ;
     RECT  13.2 62.649 13.32 62.663 ;
     RECT  15.9 61.907 16.488 62.663 ;
     RECT  18.6 62.649 18.72 62.663 ;
     RECT  20.496 62.579 20.52 62.675 ;
     RECT  16.464 62.663 16.488 62.771 ;
  END
END hbfd_rly_624_WE
END LIBRARY
